VERSION 5.8 ;
BUSBITCHARS "[]" ;
DIVIDERCHAR "/" ;
UNITS
    DATABASE MICRONS 1000 ;
END UNITS

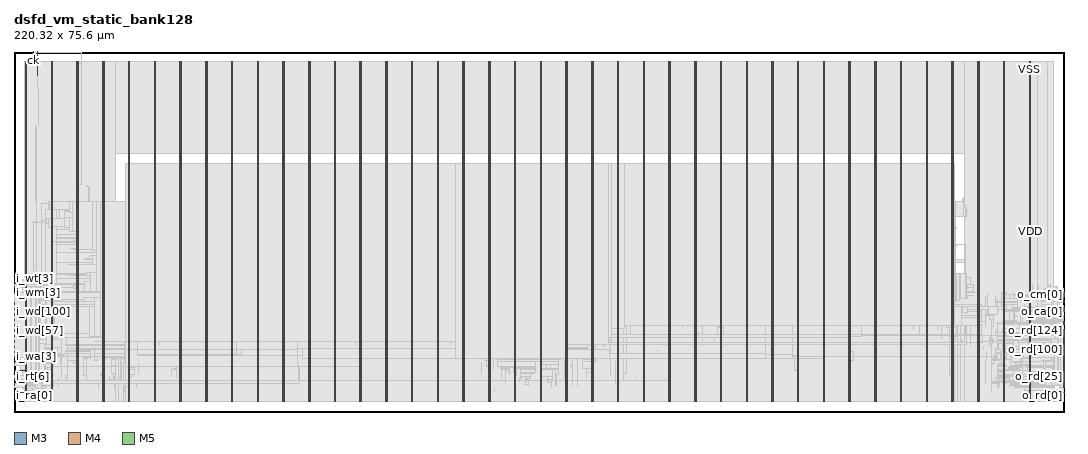
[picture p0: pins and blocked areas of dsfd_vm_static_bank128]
MACRO dsfd_vm_static_bank128
  FOREIGN dsfd_vm_static_bank128 0 0 ;
  CLASS BLOCK ;
  SIZE 220.32 BY 75.6 ;
  PIN ck
    DIRECTION INPUT ;
    USE SIGNAL ;
    PORT
      LAYER M3 ;
        RECT  4.032 75.562 4.05 75.6 ;
    END
    PORT
      LAYER M3 ;
        RECT  4.032 75.451 4.05 75.581 ;
    END
  END ck
  PIN i_ra[0]
    DIRECTION INPUT ;
    USE SIGNAL ;
    PORT
      LAYER M4 ;
        RECT  0 5.088 0.084 5.112 ;
    END
  END i_ra[0]
  PIN i_ra[1]
    DIRECTION INPUT ;
    USE SIGNAL ;
    PORT
      LAYER M4 ;
        RECT  0 5.184 0.084 5.208 ;
    END
  END i_ra[1]
  PIN i_ra[2]
    DIRECTION INPUT ;
    USE SIGNAL ;
    PORT
      LAYER M4 ;
        RECT  0 5.28 0.084 5.304 ;
    END
  END i_ra[2]
  PIN i_ra[3]
    DIRECTION INPUT ;
    USE SIGNAL ;
    PORT
      LAYER M4 ;
        RECT  0 5.376 0.084 5.4 ;
    END
  END i_ra[3]
  PIN i_ra[4]
    DIRECTION INPUT ;
    USE SIGNAL ;
    PORT
      LAYER M4 ;
        RECT  0 5.472 0.084 5.496 ;
    END
  END i_ra[4]
  PIN i_ra[5]
    DIRECTION INPUT ;
    USE SIGNAL ;
    PORT
      LAYER M4 ;
        RECT  0 5.568 0.084 5.592 ;
    END
  END i_ra[5]
  PIN i_ra[6]
    DIRECTION INPUT ;
    USE SIGNAL ;
    PORT
      LAYER M4 ;
        RECT  0 5.664 0.084 5.688 ;
    END
  END i_ra[6]
  PIN i_ra[7]
    DIRECTION INPUT ;
    USE SIGNAL ;
    PORT
      LAYER M4 ;
        RECT  0 5.76 0.084 5.784 ;
    END
  END i_ra[7]
  PIN i_ra[8]
    DIRECTION INPUT ;
    USE SIGNAL ;
    PORT
      LAYER M4 ;
        RECT  0 5.856 0.084 5.88 ;
    END
  END i_ra[8]
  PIN i_rt[0]
    DIRECTION INPUT ;
    USE SIGNAL ;
    PORT
      LAYER M4 ;
        RECT  0 6.912 0.084 6.936 ;
    END
  END i_rt[0]
  PIN i_rt[1]
    DIRECTION INPUT ;
    USE SIGNAL ;
    PORT
      LAYER M4 ;
        RECT  0 7.008 0.084 7.032 ;
    END
  END i_rt[1]
  PIN i_rt[2]
    DIRECTION INPUT ;
    USE SIGNAL ;
    PORT
      LAYER M4 ;
        RECT  0 7.104 0.084 7.128 ;
    END
  END i_rt[2]
  PIN i_rt[3]
    DIRECTION INPUT ;
    USE SIGNAL ;
    PORT
      LAYER M4 ;
        RECT  0 7.2 0.084 7.224 ;
    END
  END i_rt[3]
  PIN i_rt[4]
    DIRECTION INPUT ;
    USE SIGNAL ;
    PORT
      LAYER M4 ;
        RECT  0 7.296 0.084 7.32 ;
    END
  END i_rt[4]
  PIN i_rt[5]
    DIRECTION INPUT ;
    USE SIGNAL ;
    PORT
      LAYER M4 ;
        RECT  0 7.392 0.084 7.416 ;
    END
  END i_rt[5]
  PIN i_rt[6]
    DIRECTION INPUT ;
    USE SIGNAL ;
    PORT
      LAYER M4 ;
        RECT  0 7.488 0.084 7.512 ;
    END
  END i_rt[6]
  PIN i_rt[7]
    DIRECTION INPUT ;
    USE SIGNAL ;
    PORT
      LAYER M4 ;
        RECT  0 7.584 0.084 7.608 ;
    END
  END i_rt[7]
  PIN i_rv
    DIRECTION INPUT ;
    USE SIGNAL ;
    PORT
      LAYER M4 ;
        RECT  0 4.032 0.084 4.056 ;
    END
    PORT
      LAYER M4 ;
        RECT  0.06 4.032 2.408 4.056 ;
    END
  END i_rv
  PIN i_wa[0]
    DIRECTION INPUT ;
    USE SIGNAL ;
    PORT
      LAYER M4 ;
        RECT  0 9.696 0.084 9.72 ;
    END
  END i_wa[0]
  PIN i_wa[1]
    DIRECTION INPUT ;
    USE SIGNAL ;
    PORT
      LAYER M4 ;
        RECT  0 9.792 0.084 9.816 ;
    END
  END i_wa[1]
  PIN i_wa[2]
    DIRECTION INPUT ;
    USE SIGNAL ;
    PORT
      LAYER M4 ;
        RECT  0 9.888 0.084 9.912 ;
    END
  END i_wa[2]
  PIN i_wa[3]
    DIRECTION INPUT ;
    USE SIGNAL ;
    PORT
      LAYER M4 ;
        RECT  0 9.984 0.084 10.008 ;
    END
  END i_wa[3]
  PIN i_wa[4]
    DIRECTION INPUT ;
    USE SIGNAL ;
    PORT
      LAYER M4 ;
        RECT  0 10.08 0.084 10.104 ;
    END
  END i_wa[4]
  PIN i_wa[5]
    DIRECTION INPUT ;
    USE SIGNAL ;
    PORT
      LAYER M4 ;
        RECT  0 10.176 0.084 10.2 ;
    END
  END i_wa[5]
  PIN i_wa[6]
    DIRECTION INPUT ;
    USE SIGNAL ;
    PORT
      LAYER M4 ;
        RECT  0 10.272 0.084 10.296 ;
    END
  END i_wa[6]
  PIN i_wa[7]
    DIRECTION INPUT ;
    USE SIGNAL ;
    PORT
      LAYER M4 ;
        RECT  0 10.368 0.084 10.392 ;
    END
  END i_wa[7]
  PIN i_wa[8]
    DIRECTION INPUT ;
    USE SIGNAL ;
    PORT
      LAYER M4 ;
        RECT  0 10.464 0.084 10.488 ;
    END
  END i_wa[8]
  PIN i_wd[0]
    DIRECTION INPUT ;
    USE SIGNAL ;
    PORT
      LAYER M4 ;
        RECT  0 11.52 0.084 11.544 ;
    END
  END i_wd[0]
  PIN i_wd[100]
    DIRECTION INPUT ;
    USE SIGNAL ;
    PORT
      LAYER M4 ;
        RECT  0 21.12 0.084 21.144 ;
    END
  END i_wd[100]
  PIN i_wd[101]
    DIRECTION INPUT ;
    USE SIGNAL ;
    PORT
      LAYER M4 ;
        RECT  0 21.216 0.084 21.24 ;
    END
  END i_wd[101]
  PIN i_wd[102]
    DIRECTION INPUT ;
    USE SIGNAL ;
    PORT
      LAYER M4 ;
        RECT  0 21.312 0.084 21.336 ;
    END
  END i_wd[102]
  PIN i_wd[103]
    DIRECTION INPUT ;
    USE SIGNAL ;
    PORT
      LAYER M4 ;
        RECT  0 21.408 0.084 21.432 ;
    END
  END i_wd[103]
  PIN i_wd[104]
    DIRECTION INPUT ;
    USE SIGNAL ;
    PORT
      LAYER M4 ;
        RECT  0 21.504 0.084 21.528 ;
    END
  END i_wd[104]
  PIN i_wd[105]
    DIRECTION INPUT ;
    USE SIGNAL ;
    PORT
      LAYER M4 ;
        RECT  0 21.6 0.084 21.624 ;
    END
  END i_wd[105]
  PIN i_wd[106]
    DIRECTION INPUT ;
    USE SIGNAL ;
    PORT
      LAYER M4 ;
        RECT  0 21.696 0.084 21.72 ;
    END
  END i_wd[106]
  PIN i_wd[107]
    DIRECTION INPUT ;
    USE SIGNAL ;
    PORT
      LAYER M4 ;
        RECT  0 21.792 0.084 21.816 ;
    END
  END i_wd[107]
  PIN i_wd[108]
    DIRECTION INPUT ;
    USE SIGNAL ;
    PORT
      LAYER M4 ;
        RECT  0 21.888 0.084 21.912 ;
    END
  END i_wd[108]
  PIN i_wd[109]
    DIRECTION INPUT ;
    USE SIGNAL ;
    PORT
      LAYER M4 ;
        RECT  0 21.984 0.084 22.008 ;
    END
  END i_wd[109]
  PIN i_wd[10]
    DIRECTION INPUT ;
    USE SIGNAL ;
    PORT
      LAYER M4 ;
        RECT  0 12.48 0.084 12.504 ;
    END
  END i_wd[10]
  PIN i_wd[110]
    DIRECTION INPUT ;
    USE SIGNAL ;
    PORT
      LAYER M4 ;
        RECT  0 22.08 0.084 22.104 ;
    END
  END i_wd[110]
  PIN i_wd[111]
    DIRECTION INPUT ;
    USE SIGNAL ;
    PORT
      LAYER M4 ;
        RECT  0 22.176 0.084 22.2 ;
    END
  END i_wd[111]
  PIN i_wd[112]
    DIRECTION INPUT ;
    USE SIGNAL ;
    PORT
      LAYER M4 ;
        RECT  0 22.272 0.084 22.296 ;
    END
  END i_wd[112]
  PIN i_wd[113]
    DIRECTION INPUT ;
    USE SIGNAL ;
    PORT
      LAYER M4 ;
        RECT  0 22.368 0.084 22.392 ;
    END
  END i_wd[113]
  PIN i_wd[114]
    DIRECTION INPUT ;
    USE SIGNAL ;
    PORT
      LAYER M4 ;
        RECT  0 22.464 0.084 22.488 ;
    END
  END i_wd[114]
  PIN i_wd[115]
    DIRECTION INPUT ;
    USE SIGNAL ;
    PORT
      LAYER M4 ;
        RECT  0 22.56 0.084 22.584 ;
    END
  END i_wd[115]
  PIN i_wd[116]
    DIRECTION INPUT ;
    USE SIGNAL ;
    PORT
      LAYER M4 ;
        RECT  0 22.656 0.084 22.68 ;
    END
  END i_wd[116]
  PIN i_wd[117]
    DIRECTION INPUT ;
    USE SIGNAL ;
    PORT
      LAYER M4 ;
        RECT  0 22.752 0.084 22.776 ;
    END
  END i_wd[117]
  PIN i_wd[118]
    DIRECTION INPUT ;
    USE SIGNAL ;
    PORT
      LAYER M4 ;
        RECT  0 22.848 0.084 22.872 ;
    END
  END i_wd[118]
  PIN i_wd[119]
    DIRECTION INPUT ;
    USE SIGNAL ;
    PORT
      LAYER M4 ;
        RECT  0 22.944 0.084 22.968 ;
    END
  END i_wd[119]
  PIN i_wd[11]
    DIRECTION INPUT ;
    USE SIGNAL ;
    PORT
      LAYER M4 ;
        RECT  0 12.576 0.084 12.6 ;
    END
  END i_wd[11]
  PIN i_wd[120]
    DIRECTION INPUT ;
    USE SIGNAL ;
    PORT
      LAYER M4 ;
        RECT  0 23.04 0.084 23.064 ;
    END
  END i_wd[120]
  PIN i_wd[121]
    DIRECTION INPUT ;
    USE SIGNAL ;
    PORT
      LAYER M4 ;
        RECT  0 23.136 0.084 23.16 ;
    END
  END i_wd[121]
  PIN i_wd[122]
    DIRECTION INPUT ;
    USE SIGNAL ;
    PORT
      LAYER M4 ;
        RECT  0 23.232 0.084 23.256 ;
    END
  END i_wd[122]
  PIN i_wd[123]
    DIRECTION INPUT ;
    USE SIGNAL ;
    PORT
      LAYER M4 ;
        RECT  0 23.328 0.084 23.352 ;
    END
  END i_wd[123]
  PIN i_wd[124]
    DIRECTION INPUT ;
    USE SIGNAL ;
    PORT
      LAYER M4 ;
        RECT  0 23.424 0.084 23.448 ;
    END
  END i_wd[124]
  PIN i_wd[125]
    DIRECTION INPUT ;
    USE SIGNAL ;
    PORT
      LAYER M4 ;
        RECT  0 23.52 0.084 23.544 ;
    END
  END i_wd[125]
  PIN i_wd[126]
    DIRECTION INPUT ;
    USE SIGNAL ;
    PORT
      LAYER M4 ;
        RECT  0 23.616 0.084 23.64 ;
    END
  END i_wd[126]
  PIN i_wd[127]
    DIRECTION INPUT ;
    USE SIGNAL ;
    PORT
      LAYER M4 ;
        RECT  0 23.712 0.084 23.736 ;
    END
  END i_wd[127]
  PIN i_wd[12]
    DIRECTION INPUT ;
    USE SIGNAL ;
    PORT
      LAYER M4 ;
        RECT  0 12.672 0.084 12.696 ;
    END
  END i_wd[12]
  PIN i_wd[13]
    DIRECTION INPUT ;
    USE SIGNAL ;
    PORT
      LAYER M4 ;
        RECT  0 12.768 0.084 12.792 ;
    END
  END i_wd[13]
  PIN i_wd[14]
    DIRECTION INPUT ;
    USE SIGNAL ;
    PORT
      LAYER M4 ;
        RECT  0 12.864 0.084 12.888 ;
    END
  END i_wd[14]
  PIN i_wd[15]
    DIRECTION INPUT ;
    USE SIGNAL ;
    PORT
      LAYER M4 ;
        RECT  0 12.96 0.084 12.984 ;
    END
  END i_wd[15]
  PIN i_wd[16]
    DIRECTION INPUT ;
    USE SIGNAL ;
    PORT
      LAYER M4 ;
        RECT  0 13.056 0.084 13.08 ;
    END
  END i_wd[16]
  PIN i_wd[17]
    DIRECTION INPUT ;
    USE SIGNAL ;
    PORT
      LAYER M4 ;
        RECT  0 13.152 0.084 13.176 ;
    END
  END i_wd[17]
  PIN i_wd[18]
    DIRECTION INPUT ;
    USE SIGNAL ;
    PORT
      LAYER M4 ;
        RECT  0 13.248 0.084 13.272 ;
    END
  END i_wd[18]
  PIN i_wd[19]
    DIRECTION INPUT ;
    USE SIGNAL ;
    PORT
      LAYER M4 ;
        RECT  0 13.344 0.084 13.368 ;
    END
  END i_wd[19]
  PIN i_wd[1]
    DIRECTION INPUT ;
    USE SIGNAL ;
    PORT
      LAYER M4 ;
        RECT  0 11.616 0.084 11.64 ;
    END
  END i_wd[1]
  PIN i_wd[20]
    DIRECTION INPUT ;
    USE SIGNAL ;
    PORT
      LAYER M4 ;
        RECT  0 13.44 0.084 13.464 ;
    END
  END i_wd[20]
  PIN i_wd[21]
    DIRECTION INPUT ;
    USE SIGNAL ;
    PORT
      LAYER M4 ;
        RECT  0 13.536 0.084 13.56 ;
    END
  END i_wd[21]
  PIN i_wd[22]
    DIRECTION INPUT ;
    USE SIGNAL ;
    PORT
      LAYER M4 ;
        RECT  0 13.632 0.084 13.656 ;
    END
  END i_wd[22]
  PIN i_wd[23]
    DIRECTION INPUT ;
    USE SIGNAL ;
    PORT
      LAYER M4 ;
        RECT  0 13.728 0.084 13.752 ;
    END
  END i_wd[23]
  PIN i_wd[24]
    DIRECTION INPUT ;
    USE SIGNAL ;
    PORT
      LAYER M4 ;
        RECT  0 13.824 0.084 13.848 ;
    END
  END i_wd[24]
  PIN i_wd[25]
    DIRECTION INPUT ;
    USE SIGNAL ;
    PORT
      LAYER M4 ;
        RECT  0 13.92 0.084 13.944 ;
    END
  END i_wd[25]
  PIN i_wd[26]
    DIRECTION INPUT ;
    USE SIGNAL ;
    PORT
      LAYER M4 ;
        RECT  0 14.016 0.084 14.04 ;
    END
  END i_wd[26]
  PIN i_wd[27]
    DIRECTION INPUT ;
    USE SIGNAL ;
    PORT
      LAYER M4 ;
        RECT  0 14.112 0.084 14.136 ;
    END
  END i_wd[27]
  PIN i_wd[28]
    DIRECTION INPUT ;
    USE SIGNAL ;
    PORT
      LAYER M4 ;
        RECT  0 14.208 0.084 14.232 ;
    END
  END i_wd[28]
  PIN i_wd[29]
    DIRECTION INPUT ;
    USE SIGNAL ;
    PORT
      LAYER M4 ;
        RECT  0 14.304 0.084 14.328 ;
    END
  END i_wd[29]
  PIN i_wd[2]
    DIRECTION INPUT ;
    USE SIGNAL ;
    PORT
      LAYER M4 ;
        RECT  0 11.712 0.084 11.736 ;
    END
  END i_wd[2]
  PIN i_wd[30]
    DIRECTION INPUT ;
    USE SIGNAL ;
    PORT
      LAYER M4 ;
        RECT  0 14.4 0.084 14.424 ;
    END
  END i_wd[30]
  PIN i_wd[31]
    DIRECTION INPUT ;
    USE SIGNAL ;
    PORT
      LAYER M4 ;
        RECT  0 14.496 0.084 14.52 ;
    END
  END i_wd[31]
  PIN i_wd[32]
    DIRECTION INPUT ;
    USE SIGNAL ;
    PORT
      LAYER M4 ;
        RECT  0 14.592 0.084 14.616 ;
    END
  END i_wd[32]
  PIN i_wd[33]
    DIRECTION INPUT ;
    USE SIGNAL ;
    PORT
      LAYER M4 ;
        RECT  0 14.688 0.084 14.712 ;
    END
  END i_wd[33]
  PIN i_wd[34]
    DIRECTION INPUT ;
    USE SIGNAL ;
    PORT
      LAYER M4 ;
        RECT  0 14.784 0.084 14.808 ;
    END
  END i_wd[34]
  PIN i_wd[35]
    DIRECTION INPUT ;
    USE SIGNAL ;
    PORT
      LAYER M4 ;
        RECT  0 14.88 0.084 14.904 ;
    END
  END i_wd[35]
  PIN i_wd[36]
    DIRECTION INPUT ;
    USE SIGNAL ;
    PORT
      LAYER M4 ;
        RECT  0 14.976 0.084 15 ;
    END
  END i_wd[36]
  PIN i_wd[37]
    DIRECTION INPUT ;
    USE SIGNAL ;
    PORT
      LAYER M4 ;
        RECT  0 15.072 0.084 15.096 ;
    END
  END i_wd[37]
  PIN i_wd[38]
    DIRECTION INPUT ;
    USE SIGNAL ;
    PORT
      LAYER M4 ;
        RECT  0 15.168 0.084 15.192 ;
    END
  END i_wd[38]
  PIN i_wd[39]
    DIRECTION INPUT ;
    USE SIGNAL ;
    PORT
      LAYER M4 ;
        RECT  0 15.264 0.084 15.288 ;
    END
  END i_wd[39]
  PIN i_wd[3]
    DIRECTION INPUT ;
    USE SIGNAL ;
    PORT
      LAYER M4 ;
        RECT  0 11.808 0.084 11.832 ;
    END
  END i_wd[3]
  PIN i_wd[40]
    DIRECTION INPUT ;
    USE SIGNAL ;
    PORT
      LAYER M4 ;
        RECT  0 15.36 0.084 15.384 ;
    END
  END i_wd[40]
  PIN i_wd[41]
    DIRECTION INPUT ;
    USE SIGNAL ;
    PORT
      LAYER M4 ;
        RECT  0 15.456 0.084 15.48 ;
    END
  END i_wd[41]
  PIN i_wd[42]
    DIRECTION INPUT ;
    USE SIGNAL ;
    PORT
      LAYER M4 ;
        RECT  0 15.552 0.084 15.576 ;
    END
  END i_wd[42]
  PIN i_wd[43]
    DIRECTION INPUT ;
    USE SIGNAL ;
    PORT
      LAYER M4 ;
        RECT  0 15.648 0.084 15.672 ;
    END
  END i_wd[43]
  PIN i_wd[44]
    DIRECTION INPUT ;
    USE SIGNAL ;
    PORT
      LAYER M4 ;
        RECT  0 15.744 0.084 15.768 ;
    END
  END i_wd[44]
  PIN i_wd[45]
    DIRECTION INPUT ;
    USE SIGNAL ;
    PORT
      LAYER M4 ;
        RECT  0 15.84 0.084 15.864 ;
    END
  END i_wd[45]
  PIN i_wd[46]
    DIRECTION INPUT ;
    USE SIGNAL ;
    PORT
      LAYER M4 ;
        RECT  0 15.936 0.084 15.96 ;
    END
  END i_wd[46]
  PIN i_wd[47]
    DIRECTION INPUT ;
    USE SIGNAL ;
    PORT
      LAYER M4 ;
        RECT  0 16.032 0.084 16.056 ;
    END
  END i_wd[47]
  PIN i_wd[48]
    DIRECTION INPUT ;
    USE SIGNAL ;
    PORT
      LAYER M4 ;
        RECT  0 16.128 0.084 16.152 ;
    END
  END i_wd[48]
  PIN i_wd[49]
    DIRECTION INPUT ;
    USE SIGNAL ;
    PORT
      LAYER M4 ;
        RECT  0 16.224 0.084 16.248 ;
    END
  END i_wd[49]
  PIN i_wd[4]
    DIRECTION INPUT ;
    USE SIGNAL ;
    PORT
      LAYER M4 ;
        RECT  0 11.904 0.084 11.928 ;
    END
  END i_wd[4]
  PIN i_wd[50]
    DIRECTION INPUT ;
    USE SIGNAL ;
    PORT
      LAYER M4 ;
        RECT  0 16.32 0.084 16.344 ;
    END
  END i_wd[50]
  PIN i_wd[51]
    DIRECTION INPUT ;
    USE SIGNAL ;
    PORT
      LAYER M4 ;
        RECT  0 16.416 0.084 16.44 ;
    END
  END i_wd[51]
  PIN i_wd[52]
    DIRECTION INPUT ;
    USE SIGNAL ;
    PORT
      LAYER M4 ;
        RECT  0 16.512 0.084 16.536 ;
    END
  END i_wd[52]
  PIN i_wd[53]
    DIRECTION INPUT ;
    USE SIGNAL ;
    PORT
      LAYER M4 ;
        RECT  0 16.608 0.084 16.632 ;
    END
  END i_wd[53]
  PIN i_wd[54]
    DIRECTION INPUT ;
    USE SIGNAL ;
    PORT
      LAYER M4 ;
        RECT  0 16.704 0.084 16.728 ;
    END
  END i_wd[54]
  PIN i_wd[55]
    DIRECTION INPUT ;
    USE SIGNAL ;
    PORT
      LAYER M4 ;
        RECT  0 16.8 0.084 16.824 ;
    END
  END i_wd[55]
  PIN i_wd[56]
    DIRECTION INPUT ;
    USE SIGNAL ;
    PORT
      LAYER M4 ;
        RECT  0 16.896 0.084 16.92 ;
    END
  END i_wd[56]
  PIN i_wd[57]
    DIRECTION INPUT ;
    USE SIGNAL ;
    PORT
      LAYER M4 ;
        RECT  0 16.992 0.084 17.016 ;
    END
  END i_wd[57]
  PIN i_wd[58]
    DIRECTION INPUT ;
    USE SIGNAL ;
    PORT
      LAYER M4 ;
        RECT  0 17.088 0.084 17.112 ;
    END
  END i_wd[58]
  PIN i_wd[59]
    DIRECTION INPUT ;
    USE SIGNAL ;
    PORT
      LAYER M4 ;
        RECT  0 17.184 0.084 17.208 ;
    END
  END i_wd[59]
  PIN i_wd[5]
    DIRECTION INPUT ;
    USE SIGNAL ;
    PORT
      LAYER M4 ;
        RECT  0 12 0.084 12.024 ;
    END
  END i_wd[5]
  PIN i_wd[60]
    DIRECTION INPUT ;
    USE SIGNAL ;
    PORT
      LAYER M4 ;
        RECT  0 17.28 0.084 17.304 ;
    END
  END i_wd[60]
  PIN i_wd[61]
    DIRECTION INPUT ;
    USE SIGNAL ;
    PORT
      LAYER M4 ;
        RECT  0 17.376 0.084 17.4 ;
    END
  END i_wd[61]
  PIN i_wd[62]
    DIRECTION INPUT ;
    USE SIGNAL ;
    PORT
      LAYER M4 ;
        RECT  0 17.472 0.084 17.496 ;
    END
  END i_wd[62]
  PIN i_wd[63]
    DIRECTION INPUT ;
    USE SIGNAL ;
    PORT
      LAYER M4 ;
        RECT  0 17.568 0.084 17.592 ;
    END
  END i_wd[63]
  PIN i_wd[64]
    DIRECTION INPUT ;
    USE SIGNAL ;
    PORT
      LAYER M4 ;
        RECT  0 17.664 0.084 17.688 ;
    END
  END i_wd[64]
  PIN i_wd[65]
    DIRECTION INPUT ;
    USE SIGNAL ;
    PORT
      LAYER M4 ;
        RECT  0 17.76 0.084 17.784 ;
    END
  END i_wd[65]
  PIN i_wd[66]
    DIRECTION INPUT ;
    USE SIGNAL ;
    PORT
      LAYER M4 ;
        RECT  0 17.856 0.084 17.88 ;
    END
  END i_wd[66]
  PIN i_wd[67]
    DIRECTION INPUT ;
    USE SIGNAL ;
    PORT
      LAYER M4 ;
        RECT  0 17.952 0.084 17.976 ;
    END
  END i_wd[67]
  PIN i_wd[68]
    DIRECTION INPUT ;
    USE SIGNAL ;
    PORT
      LAYER M4 ;
        RECT  0 18.048 0.084 18.072 ;
    END
  END i_wd[68]
  PIN i_wd[69]
    DIRECTION INPUT ;
    USE SIGNAL ;
    PORT
      LAYER M4 ;
        RECT  0 18.144 0.084 18.168 ;
    END
  END i_wd[69]
  PIN i_wd[6]
    DIRECTION INPUT ;
    USE SIGNAL ;
    PORT
      LAYER M4 ;
        RECT  0 12.096 0.084 12.12 ;
    END
  END i_wd[6]
  PIN i_wd[70]
    DIRECTION INPUT ;
    USE SIGNAL ;
    PORT
      LAYER M4 ;
        RECT  0 18.24 0.084 18.264 ;
    END
  END i_wd[70]
  PIN i_wd[71]
    DIRECTION INPUT ;
    USE SIGNAL ;
    PORT
      LAYER M4 ;
        RECT  0 18.336 0.084 18.36 ;
    END
  END i_wd[71]
  PIN i_wd[72]
    DIRECTION INPUT ;
    USE SIGNAL ;
    PORT
      LAYER M4 ;
        RECT  0 18.432 0.084 18.456 ;
    END
  END i_wd[72]
  PIN i_wd[73]
    DIRECTION INPUT ;
    USE SIGNAL ;
    PORT
      LAYER M4 ;
        RECT  0 18.528 0.084 18.552 ;
    END
  END i_wd[73]
  PIN i_wd[74]
    DIRECTION INPUT ;
    USE SIGNAL ;
    PORT
      LAYER M4 ;
        RECT  0 18.624 0.084 18.648 ;
    END
  END i_wd[74]
  PIN i_wd[75]
    DIRECTION INPUT ;
    USE SIGNAL ;
    PORT
      LAYER M4 ;
        RECT  0 18.72 0.084 18.744 ;
    END
  END i_wd[75]
  PIN i_wd[76]
    DIRECTION INPUT ;
    USE SIGNAL ;
    PORT
      LAYER M4 ;
        RECT  0 18.816 0.084 18.84 ;
    END
  END i_wd[76]
  PIN i_wd[77]
    DIRECTION INPUT ;
    USE SIGNAL ;
    PORT
      LAYER M4 ;
        RECT  0 18.912 0.084 18.936 ;
    END
  END i_wd[77]
  PIN i_wd[78]
    DIRECTION INPUT ;
    USE SIGNAL ;
    PORT
      LAYER M4 ;
        RECT  0 19.008 0.084 19.032 ;
    END
  END i_wd[78]
  PIN i_wd[79]
    DIRECTION INPUT ;
    USE SIGNAL ;
    PORT
      LAYER M4 ;
        RECT  0 19.104 0.084 19.128 ;
    END
  END i_wd[79]
  PIN i_wd[7]
    DIRECTION INPUT ;
    USE SIGNAL ;
    PORT
      LAYER M4 ;
        RECT  0 12.192 0.084 12.216 ;
    END
  END i_wd[7]
  PIN i_wd[80]
    DIRECTION INPUT ;
    USE SIGNAL ;
    PORT
      LAYER M4 ;
        RECT  0 19.2 0.084 19.224 ;
    END
  END i_wd[80]
  PIN i_wd[81]
    DIRECTION INPUT ;
    USE SIGNAL ;
    PORT
      LAYER M4 ;
        RECT  0 19.296 0.084 19.32 ;
    END
  END i_wd[81]
  PIN i_wd[82]
    DIRECTION INPUT ;
    USE SIGNAL ;
    PORT
      LAYER M4 ;
        RECT  0 19.392 0.084 19.416 ;
    END
  END i_wd[82]
  PIN i_wd[83]
    DIRECTION INPUT ;
    USE SIGNAL ;
    PORT
      LAYER M4 ;
        RECT  0 19.488 0.084 19.512 ;
    END
  END i_wd[83]
  PIN i_wd[84]
    DIRECTION INPUT ;
    USE SIGNAL ;
    PORT
      LAYER M4 ;
        RECT  0 19.584 0.084 19.608 ;
    END
  END i_wd[84]
  PIN i_wd[85]
    DIRECTION INPUT ;
    USE SIGNAL ;
    PORT
      LAYER M4 ;
        RECT  0 19.68 0.084 19.704 ;
    END
  END i_wd[85]
  PIN i_wd[86]
    DIRECTION INPUT ;
    USE SIGNAL ;
    PORT
      LAYER M4 ;
        RECT  0 19.776 0.084 19.8 ;
    END
  END i_wd[86]
  PIN i_wd[87]
    DIRECTION INPUT ;
    USE SIGNAL ;
    PORT
      LAYER M4 ;
        RECT  0 19.872 0.084 19.896 ;
    END
  END i_wd[87]
  PIN i_wd[88]
    DIRECTION INPUT ;
    USE SIGNAL ;
    PORT
      LAYER M4 ;
        RECT  0 19.968 0.084 19.992 ;
    END
  END i_wd[88]
  PIN i_wd[89]
    DIRECTION INPUT ;
    USE SIGNAL ;
    PORT
      LAYER M4 ;
        RECT  0 20.064 0.084 20.088 ;
    END
  END i_wd[89]
  PIN i_wd[8]
    DIRECTION INPUT ;
    USE SIGNAL ;
    PORT
      LAYER M4 ;
        RECT  0 12.288 0.084 12.312 ;
    END
  END i_wd[8]
  PIN i_wd[90]
    DIRECTION INPUT ;
    USE SIGNAL ;
    PORT
      LAYER M4 ;
        RECT  0 20.16 0.084 20.184 ;
    END
  END i_wd[90]
  PIN i_wd[91]
    DIRECTION INPUT ;
    USE SIGNAL ;
    PORT
      LAYER M4 ;
        RECT  0 20.256 0.084 20.28 ;
    END
  END i_wd[91]
  PIN i_wd[92]
    DIRECTION INPUT ;
    USE SIGNAL ;
    PORT
      LAYER M4 ;
        RECT  0 20.352 0.084 20.376 ;
    END
  END i_wd[92]
  PIN i_wd[93]
    DIRECTION INPUT ;
    USE SIGNAL ;
    PORT
      LAYER M4 ;
        RECT  0 20.448 0.084 20.472 ;
    END
  END i_wd[93]
  PIN i_wd[94]
    DIRECTION INPUT ;
    USE SIGNAL ;
    PORT
      LAYER M4 ;
        RECT  0 20.544 0.084 20.568 ;
    END
  END i_wd[94]
  PIN i_wd[95]
    DIRECTION INPUT ;
    USE SIGNAL ;
    PORT
      LAYER M4 ;
        RECT  0 20.64 0.084 20.664 ;
    END
  END i_wd[95]
  PIN i_wd[96]
    DIRECTION INPUT ;
    USE SIGNAL ;
    PORT
      LAYER M4 ;
        RECT  0 20.736 0.084 20.76 ;
    END
  END i_wd[96]
  PIN i_wd[97]
    DIRECTION INPUT ;
    USE SIGNAL ;
    PORT
      LAYER M4 ;
        RECT  0 20.832 0.084 20.856 ;
    END
  END i_wd[97]
  PIN i_wd[98]
    DIRECTION INPUT ;
    USE SIGNAL ;
    PORT
      LAYER M4 ;
        RECT  0 20.928 0.084 20.952 ;
    END
  END i_wd[98]
  PIN i_wd[99]
    DIRECTION INPUT ;
    USE SIGNAL ;
    PORT
      LAYER M4 ;
        RECT  0 21.024 0.084 21.048 ;
    END
  END i_wd[99]
  PIN i_wd[9]
    DIRECTION INPUT ;
    USE SIGNAL ;
    PORT
      LAYER M4 ;
        RECT  0 12.384 0.084 12.408 ;
    END
  END i_wd[9]
  PIN i_wm[0]
    DIRECTION INPUT ;
    USE SIGNAL ;
    PORT
      LAYER M4 ;
        RECT  0 24.768 0.084 24.792 ;
    END
  END i_wm[0]
  PIN i_wm[1]
    DIRECTION INPUT ;
    USE SIGNAL ;
    PORT
      LAYER M4 ;
        RECT  0 24.864 0.084 24.888 ;
    END
  END i_wm[1]
  PIN i_wm[2]
    DIRECTION INPUT ;
    USE SIGNAL ;
    PORT
      LAYER M4 ;
        RECT  0 24.96 0.084 24.984 ;
    END
  END i_wm[2]
  PIN i_wm[3]
    DIRECTION INPUT ;
    USE SIGNAL ;
    PORT
      LAYER M4 ;
        RECT  0 25.056 0.084 25.08 ;
    END
  END i_wm[3]
  PIN i_wt[0]
    DIRECTION INPUT ;
    USE SIGNAL ;
    PORT
      LAYER M4 ;
        RECT  0 26.112 0.084 26.136 ;
    END
  END i_wt[0]
  PIN i_wt[1]
    DIRECTION INPUT ;
    USE SIGNAL ;
    PORT
      LAYER M4 ;
        RECT  0 26.208 0.084 26.232 ;
    END
  END i_wt[1]
  PIN i_wt[2]
    DIRECTION INPUT ;
    USE SIGNAL ;
    PORT
      LAYER M4 ;
        RECT  0 26.304 0.084 26.328 ;
    END
  END i_wt[2]
  PIN i_wt[3]
    DIRECTION INPUT ;
    USE SIGNAL ;
    PORT
      LAYER M4 ;
        RECT  0 26.4 0.084 26.424 ;
    END
  END i_wt[3]
  PIN i_wt[4]
    DIRECTION INPUT ;
    USE SIGNAL ;
    PORT
      LAYER M4 ;
        RECT  0 26.496 0.084 26.52 ;
    END
  END i_wt[4]
  PIN i_wt[5]
    DIRECTION INPUT ;
    USE SIGNAL ;
    PORT
      LAYER M4 ;
        RECT  0 26.592 0.084 26.616 ;
    END
  END i_wt[5]
  PIN i_wt[6]
    DIRECTION INPUT ;
    USE SIGNAL ;
    PORT
      LAYER M4 ;
        RECT  0 26.688 0.084 26.712 ;
    END
  END i_wt[6]
  PIN i_wt[7]
    DIRECTION INPUT ;
    USE SIGNAL ;
    PORT
      LAYER M4 ;
        RECT  0 26.784 0.084 26.808 ;
    END
  END i_wt[7]
  PIN i_wv
    DIRECTION INPUT ;
    USE SIGNAL ;
    PORT
      LAYER M4 ;
        RECT  0 8.64 0.084 8.664 ;
    END
    PORT
      LAYER M4 ;
        RECT  0.06 8.64 2.408 8.664 ;
    END
  END i_wv
  PIN o_ca[0]
    DIRECTION OUTPUT ;
    USE SIGNAL ;
    PORT
      LAYER M4 ;
        RECT  220.236 21.12 220.32 21.144 ;
    END
  END o_ca[0]
  PIN o_ca[1]
    DIRECTION OUTPUT ;
    USE SIGNAL ;
    PORT
      LAYER M4 ;
        RECT  220.236 21.216 220.32 21.24 ;
    END
  END o_ca[1]
  PIN o_ca[2]
    DIRECTION OUTPUT ;
    USE SIGNAL ;
    PORT
      LAYER M4 ;
        RECT  220.236 21.312 220.32 21.336 ;
    END
  END o_ca[2]
  PIN o_ca[3]
    DIRECTION OUTPUT ;
    USE SIGNAL ;
    PORT
      LAYER M4 ;
        RECT  220.236 21.408 220.32 21.432 ;
    END
  END o_ca[3]
  PIN o_ca[4]
    DIRECTION OUTPUT ;
    USE SIGNAL ;
    PORT
      LAYER M4 ;
        RECT  220.236 21.504 220.32 21.528 ;
    END
  END o_ca[4]
  PIN o_ca[5]
    DIRECTION OUTPUT ;
    USE SIGNAL ;
    PORT
      LAYER M4 ;
        RECT  220.236 21.6 220.32 21.624 ;
    END
  END o_ca[5]
  PIN o_ca[6]
    DIRECTION OUTPUT ;
    USE SIGNAL ;
    PORT
      LAYER M4 ;
        RECT  220.236 21.696 220.32 21.72 ;
    END
  END o_ca[6]
  PIN o_ca[7]
    DIRECTION OUTPUT ;
    USE SIGNAL ;
    PORT
      LAYER M4 ;
        RECT  220.236 21.792 220.32 21.816 ;
    END
  END o_ca[7]
  PIN o_ca[8]
    DIRECTION OUTPUT ;
    USE SIGNAL ;
    PORT
      LAYER M4 ;
        RECT  220.236 21.888 220.32 21.912 ;
    END
  END o_ca[8]
  PIN o_cm[0]
    DIRECTION OUTPUT ;
    USE SIGNAL ;
    PORT
      LAYER M4 ;
        RECT  220.236 22.944 220.32 22.968 ;
    END
  END o_cm[0]
  PIN o_cm[1]
    DIRECTION OUTPUT ;
    USE SIGNAL ;
    PORT
      LAYER M4 ;
        RECT  220.236 23.04 220.32 23.064 ;
    END
  END o_cm[1]
  PIN o_cm[2]
    DIRECTION OUTPUT ;
    USE SIGNAL ;
    PORT
      LAYER M4 ;
        RECT  220.236 23.136 220.32 23.16 ;
    END
  END o_cm[2]
  PIN o_cm[3]
    DIRECTION OUTPUT ;
    USE SIGNAL ;
    PORT
      LAYER M4 ;
        RECT  220.236 23.232 220.32 23.256 ;
    END
  END o_cm[3]
  PIN o_commit
    DIRECTION OUTPUT ;
    USE SIGNAL ;
    PORT
      LAYER M4 ;
        RECT  220.236 20.064 220.32 20.088 ;
    END
    PORT
      LAYER M4 ;
        RECT  219.409 20.064 220.284 20.088 ;
    END
  END o_commit
  PIN o_ct[0]
    DIRECTION OUTPUT ;
    USE SIGNAL ;
    PORT
      LAYER M4 ;
        RECT  220.236 24.288 220.32 24.312 ;
    END
  END o_ct[0]
  PIN o_ct[1]
    DIRECTION OUTPUT ;
    USE SIGNAL ;
    PORT
      LAYER M4 ;
        RECT  220.236 24.384 220.32 24.408 ;
    END
  END o_ct[1]
  PIN o_ct[2]
    DIRECTION OUTPUT ;
    USE SIGNAL ;
    PORT
      LAYER M4 ;
        RECT  220.236 24.48 220.32 24.504 ;
    END
  END o_ct[2]
  PIN o_ct[3]
    DIRECTION OUTPUT ;
    USE SIGNAL ;
    PORT
      LAYER M4 ;
        RECT  220.236 24.576 220.32 24.6 ;
    END
  END o_ct[3]
  PIN o_ct[4]
    DIRECTION OUTPUT ;
    USE SIGNAL ;
    PORT
      LAYER M4 ;
        RECT  220.236 24.672 220.32 24.696 ;
    END
  END o_ct[4]
  PIN o_ct[5]
    DIRECTION OUTPUT ;
    USE SIGNAL ;
    PORT
      LAYER M4 ;
        RECT  220.236 24.768 220.32 24.792 ;
    END
  END o_ct[5]
  PIN o_ct[6]
    DIRECTION OUTPUT ;
    USE SIGNAL ;
    PORT
      LAYER M4 ;
        RECT  220.236 24.864 220.32 24.888 ;
    END
  END o_ct[6]
  PIN o_ct[7]
    DIRECTION OUTPUT ;
    USE SIGNAL ;
    PORT
      LAYER M4 ;
        RECT  220.236 24.96 220.32 24.984 ;
    END
  END o_ct[7]
  PIN o_rd[0]
    DIRECTION OUTPUT ;
    USE SIGNAL ;
    PORT
      LAYER M4 ;
        RECT  220.236 5.088 220.32 5.112 ;
    END
  END o_rd[0]
  PIN o_rd[100]
    DIRECTION OUTPUT ;
    USE SIGNAL ;
    PORT
      LAYER M4 ;
        RECT  220.236 14.688 220.32 14.712 ;
    END
  END o_rd[100]
  PIN o_rd[101]
    DIRECTION OUTPUT ;
    USE SIGNAL ;
    PORT
      LAYER M4 ;
        RECT  220.236 14.784 220.32 14.808 ;
    END
  END o_rd[101]
  PIN o_rd[102]
    DIRECTION OUTPUT ;
    USE SIGNAL ;
    PORT
      LAYER M4 ;
        RECT  220.236 14.88 220.32 14.904 ;
    END
  END o_rd[102]
  PIN o_rd[103]
    DIRECTION OUTPUT ;
    USE SIGNAL ;
    PORT
      LAYER M4 ;
        RECT  220.236 14.976 220.32 15 ;
    END
  END o_rd[103]
  PIN o_rd[104]
    DIRECTION OUTPUT ;
    USE SIGNAL ;
    PORT
      LAYER M4 ;
        RECT  220.236 15.072 220.32 15.096 ;
    END
  END o_rd[104]
  PIN o_rd[105]
    DIRECTION OUTPUT ;
    USE SIGNAL ;
    PORT
      LAYER M4 ;
        RECT  220.236 15.168 220.32 15.192 ;
    END
  END o_rd[105]
  PIN o_rd[106]
    DIRECTION OUTPUT ;
    USE SIGNAL ;
    PORT
      LAYER M4 ;
        RECT  220.236 15.264 220.32 15.288 ;
    END
  END o_rd[106]
  PIN o_rd[107]
    DIRECTION OUTPUT ;
    USE SIGNAL ;
    PORT
      LAYER M4 ;
        RECT  220.236 15.36 220.32 15.384 ;
    END
  END o_rd[107]
  PIN o_rd[108]
    DIRECTION OUTPUT ;
    USE SIGNAL ;
    PORT
      LAYER M4 ;
        RECT  220.236 15.456 220.32 15.48 ;
    END
  END o_rd[108]
  PIN o_rd[109]
    DIRECTION OUTPUT ;
    USE SIGNAL ;
    PORT
      LAYER M4 ;
        RECT  220.236 15.552 220.32 15.576 ;
    END
  END o_rd[109]
  PIN o_rd[10]
    DIRECTION OUTPUT ;
    USE SIGNAL ;
    PORT
      LAYER M4 ;
        RECT  220.236 6.048 220.32 6.072 ;
    END
  END o_rd[10]
  PIN o_rd[110]
    DIRECTION OUTPUT ;
    USE SIGNAL ;
    PORT
      LAYER M4 ;
        RECT  220.236 15.648 220.32 15.672 ;
    END
  END o_rd[110]
  PIN o_rd[111]
    DIRECTION OUTPUT ;
    USE SIGNAL ;
    PORT
      LAYER M4 ;
        RECT  220.236 15.744 220.32 15.768 ;
    END
  END o_rd[111]
  PIN o_rd[112]
    DIRECTION OUTPUT ;
    USE SIGNAL ;
    PORT
      LAYER M4 ;
        RECT  220.236 15.84 220.32 15.864 ;
    END
  END o_rd[112]
  PIN o_rd[113]
    DIRECTION OUTPUT ;
    USE SIGNAL ;
    PORT
      LAYER M4 ;
        RECT  220.236 15.936 220.32 15.96 ;
    END
  END o_rd[113]
  PIN o_rd[114]
    DIRECTION OUTPUT ;
    USE SIGNAL ;
    PORT
      LAYER M4 ;
        RECT  220.236 16.032 220.32 16.056 ;
    END
  END o_rd[114]
  PIN o_rd[115]
    DIRECTION OUTPUT ;
    USE SIGNAL ;
    PORT
      LAYER M4 ;
        RECT  220.236 16.128 220.32 16.152 ;
    END
  END o_rd[115]
  PIN o_rd[116]
    DIRECTION OUTPUT ;
    USE SIGNAL ;
    PORT
      LAYER M4 ;
        RECT  220.236 16.224 220.32 16.248 ;
    END
  END o_rd[116]
  PIN o_rd[117]
    DIRECTION OUTPUT ;
    USE SIGNAL ;
    PORT
      LAYER M4 ;
        RECT  220.236 16.32 220.32 16.344 ;
    END
  END o_rd[117]
  PIN o_rd[118]
    DIRECTION OUTPUT ;
    USE SIGNAL ;
    PORT
      LAYER M4 ;
        RECT  220.236 16.416 220.32 16.44 ;
    END
  END o_rd[118]
  PIN o_rd[119]
    DIRECTION OUTPUT ;
    USE SIGNAL ;
    PORT
      LAYER M4 ;
        RECT  220.236 16.512 220.32 16.536 ;
    END
  END o_rd[119]
  PIN o_rd[11]
    DIRECTION OUTPUT ;
    USE SIGNAL ;
    PORT
      LAYER M4 ;
        RECT  220.236 6.144 220.32 6.168 ;
    END
  END o_rd[11]
  PIN o_rd[120]
    DIRECTION OUTPUT ;
    USE SIGNAL ;
    PORT
      LAYER M4 ;
        RECT  220.236 16.608 220.32 16.632 ;
    END
  END o_rd[120]
  PIN o_rd[121]
    DIRECTION OUTPUT ;
    USE SIGNAL ;
    PORT
      LAYER M4 ;
        RECT  220.236 16.704 220.32 16.728 ;
    END
  END o_rd[121]
  PIN o_rd[122]
    DIRECTION OUTPUT ;
    USE SIGNAL ;
    PORT
      LAYER M4 ;
        RECT  220.236 16.8 220.32 16.824 ;
    END
  END o_rd[122]
  PIN o_rd[123]
    DIRECTION OUTPUT ;
    USE SIGNAL ;
    PORT
      LAYER M4 ;
        RECT  220.236 16.896 220.32 16.92 ;
    END
  END o_rd[123]
  PIN o_rd[124]
    DIRECTION OUTPUT ;
    USE SIGNAL ;
    PORT
      LAYER M4 ;
        RECT  220.236 16.992 220.32 17.016 ;
    END
  END o_rd[124]
  PIN o_rd[125]
    DIRECTION OUTPUT ;
    USE SIGNAL ;
    PORT
      LAYER M4 ;
        RECT  220.236 17.088 220.32 17.112 ;
    END
  END o_rd[125]
  PIN o_rd[126]
    DIRECTION OUTPUT ;
    USE SIGNAL ;
    PORT
      LAYER M4 ;
        RECT  220.236 17.184 220.32 17.208 ;
    END
  END o_rd[126]
  PIN o_rd[127]
    DIRECTION OUTPUT ;
    USE SIGNAL ;
    PORT
      LAYER M4 ;
        RECT  220.236 17.28 220.32 17.304 ;
    END
  END o_rd[127]
  PIN o_rd[12]
    DIRECTION OUTPUT ;
    USE SIGNAL ;
    PORT
      LAYER M4 ;
        RECT  220.236 6.24 220.32 6.264 ;
    END
  END o_rd[12]
  PIN o_rd[13]
    DIRECTION OUTPUT ;
    USE SIGNAL ;
    PORT
      LAYER M4 ;
        RECT  220.236 6.336 220.32 6.36 ;
    END
  END o_rd[13]
  PIN o_rd[14]
    DIRECTION OUTPUT ;
    USE SIGNAL ;
    PORT
      LAYER M4 ;
        RECT  220.236 6.432 220.32 6.456 ;
    END
  END o_rd[14]
  PIN o_rd[15]
    DIRECTION OUTPUT ;
    USE SIGNAL ;
    PORT
      LAYER M4 ;
        RECT  220.236 6.528 220.32 6.552 ;
    END
  END o_rd[15]
  PIN o_rd[16]
    DIRECTION OUTPUT ;
    USE SIGNAL ;
    PORT
      LAYER M4 ;
        RECT  220.236 6.624 220.32 6.648 ;
    END
  END o_rd[16]
  PIN o_rd[17]
    DIRECTION OUTPUT ;
    USE SIGNAL ;
    PORT
      LAYER M4 ;
        RECT  220.236 6.72 220.32 6.744 ;
    END
  END o_rd[17]
  PIN o_rd[18]
    DIRECTION OUTPUT ;
    USE SIGNAL ;
    PORT
      LAYER M4 ;
        RECT  220.236 6.816 220.32 6.84 ;
    END
  END o_rd[18]
  PIN o_rd[19]
    DIRECTION OUTPUT ;
    USE SIGNAL ;
    PORT
      LAYER M4 ;
        RECT  220.236 6.912 220.32 6.936 ;
    END
  END o_rd[19]
  PIN o_rd[1]
    DIRECTION OUTPUT ;
    USE SIGNAL ;
    PORT
      LAYER M4 ;
        RECT  220.236 5.184 220.32 5.208 ;
    END
  END o_rd[1]
  PIN o_rd[20]
    DIRECTION OUTPUT ;
    USE SIGNAL ;
    PORT
      LAYER M4 ;
        RECT  220.236 7.008 220.32 7.032 ;
    END
  END o_rd[20]
  PIN o_rd[21]
    DIRECTION OUTPUT ;
    USE SIGNAL ;
    PORT
      LAYER M4 ;
        RECT  220.236 7.104 220.32 7.128 ;
    END
  END o_rd[21]
  PIN o_rd[22]
    DIRECTION OUTPUT ;
    USE SIGNAL ;
    PORT
      LAYER M4 ;
        RECT  220.236 7.2 220.32 7.224 ;
    END
  END o_rd[22]
  PIN o_rd[23]
    DIRECTION OUTPUT ;
    USE SIGNAL ;
    PORT
      LAYER M4 ;
        RECT  220.236 7.296 220.32 7.32 ;
    END
  END o_rd[23]
  PIN o_rd[24]
    DIRECTION OUTPUT ;
    USE SIGNAL ;
    PORT
      LAYER M4 ;
        RECT  220.236 7.392 220.32 7.416 ;
    END
  END o_rd[24]
  PIN o_rd[25]
    DIRECTION OUTPUT ;
    USE SIGNAL ;
    PORT
      LAYER M4 ;
        RECT  220.236 7.488 220.32 7.512 ;
    END
  END o_rd[25]
  PIN o_rd[26]
    DIRECTION OUTPUT ;
    USE SIGNAL ;
    PORT
      LAYER M4 ;
        RECT  220.236 7.584 220.32 7.608 ;
    END
  END o_rd[26]
  PIN o_rd[27]
    DIRECTION OUTPUT ;
    USE SIGNAL ;
    PORT
      LAYER M4 ;
        RECT  220.236 7.68 220.32 7.704 ;
    END
  END o_rd[27]
  PIN o_rd[28]
    DIRECTION OUTPUT ;
    USE SIGNAL ;
    PORT
      LAYER M4 ;
        RECT  220.236 7.776 220.32 7.8 ;
    END
  END o_rd[28]
  PIN o_rd[29]
    DIRECTION OUTPUT ;
    USE SIGNAL ;
    PORT
      LAYER M4 ;
        RECT  220.236 7.872 220.32 7.896 ;
    END
  END o_rd[29]
  PIN o_rd[2]
    DIRECTION OUTPUT ;
    USE SIGNAL ;
    PORT
      LAYER M4 ;
        RECT  220.236 5.28 220.32 5.304 ;
    END
  END o_rd[2]
  PIN o_rd[30]
    DIRECTION OUTPUT ;
    USE SIGNAL ;
    PORT
      LAYER M4 ;
        RECT  220.236 7.968 220.32 7.992 ;
    END
  END o_rd[30]
  PIN o_rd[31]
    DIRECTION OUTPUT ;
    USE SIGNAL ;
    PORT
      LAYER M4 ;
        RECT  220.236 8.064 220.32 8.088 ;
    END
  END o_rd[31]
  PIN o_rd[32]
    DIRECTION OUTPUT ;
    USE SIGNAL ;
    PORT
      LAYER M4 ;
        RECT  220.236 8.16 220.32 8.184 ;
    END
  END o_rd[32]
  PIN o_rd[33]
    DIRECTION OUTPUT ;
    USE SIGNAL ;
    PORT
      LAYER M4 ;
        RECT  220.236 8.256 220.32 8.28 ;
    END
  END o_rd[33]
  PIN o_rd[34]
    DIRECTION OUTPUT ;
    USE SIGNAL ;
    PORT
      LAYER M4 ;
        RECT  220.236 8.352 220.32 8.376 ;
    END
  END o_rd[34]
  PIN o_rd[35]
    DIRECTION OUTPUT ;
    USE SIGNAL ;
    PORT
      LAYER M4 ;
        RECT  220.236 8.448 220.32 8.472 ;
    END
  END o_rd[35]
  PIN o_rd[36]
    DIRECTION OUTPUT ;
    USE SIGNAL ;
    PORT
      LAYER M4 ;
        RECT  220.236 8.544 220.32 8.568 ;
    END
  END o_rd[36]
  PIN o_rd[37]
    DIRECTION OUTPUT ;
    USE SIGNAL ;
    PORT
      LAYER M4 ;
        RECT  220.236 8.64 220.32 8.664 ;
    END
  END o_rd[37]
  PIN o_rd[38]
    DIRECTION OUTPUT ;
    USE SIGNAL ;
    PORT
      LAYER M4 ;
        RECT  220.236 8.736 220.32 8.76 ;
    END
  END o_rd[38]
  PIN o_rd[39]
    DIRECTION OUTPUT ;
    USE SIGNAL ;
    PORT
      LAYER M4 ;
        RECT  220.236 8.832 220.32 8.856 ;
    END
  END o_rd[39]
  PIN o_rd[3]
    DIRECTION OUTPUT ;
    USE SIGNAL ;
    PORT
      LAYER M4 ;
        RECT  220.236 5.376 220.32 5.4 ;
    END
  END o_rd[3]
  PIN o_rd[40]
    DIRECTION OUTPUT ;
    USE SIGNAL ;
    PORT
      LAYER M4 ;
        RECT  220.236 8.928 220.32 8.952 ;
    END
  END o_rd[40]
  PIN o_rd[41]
    DIRECTION OUTPUT ;
    USE SIGNAL ;
    PORT
      LAYER M4 ;
        RECT  220.236 9.024 220.32 9.048 ;
    END
  END o_rd[41]
  PIN o_rd[42]
    DIRECTION OUTPUT ;
    USE SIGNAL ;
    PORT
      LAYER M4 ;
        RECT  220.236 9.12 220.32 9.144 ;
    END
  END o_rd[42]
  PIN o_rd[43]
    DIRECTION OUTPUT ;
    USE SIGNAL ;
    PORT
      LAYER M4 ;
        RECT  220.236 9.216 220.32 9.24 ;
    END
  END o_rd[43]
  PIN o_rd[44]
    DIRECTION OUTPUT ;
    USE SIGNAL ;
    PORT
      LAYER M4 ;
        RECT  220.236 9.312 220.32 9.336 ;
    END
  END o_rd[44]
  PIN o_rd[45]
    DIRECTION OUTPUT ;
    USE SIGNAL ;
    PORT
      LAYER M4 ;
        RECT  220.236 9.408 220.32 9.432 ;
    END
  END o_rd[45]
  PIN o_rd[46]
    DIRECTION OUTPUT ;
    USE SIGNAL ;
    PORT
      LAYER M4 ;
        RECT  220.236 9.504 220.32 9.528 ;
    END
  END o_rd[46]
  PIN o_rd[47]
    DIRECTION OUTPUT ;
    USE SIGNAL ;
    PORT
      LAYER M4 ;
        RECT  220.236 9.6 220.32 9.624 ;
    END
  END o_rd[47]
  PIN o_rd[48]
    DIRECTION OUTPUT ;
    USE SIGNAL ;
    PORT
      LAYER M4 ;
        RECT  220.236 9.696 220.32 9.72 ;
    END
  END o_rd[48]
  PIN o_rd[49]
    DIRECTION OUTPUT ;
    USE SIGNAL ;
    PORT
      LAYER M4 ;
        RECT  220.236 9.792 220.32 9.816 ;
    END
  END o_rd[49]
  PIN o_rd[4]
    DIRECTION OUTPUT ;
    USE SIGNAL ;
    PORT
      LAYER M4 ;
        RECT  220.236 5.472 220.32 5.496 ;
    END
  END o_rd[4]
  PIN o_rd[50]
    DIRECTION OUTPUT ;
    USE SIGNAL ;
    PORT
      LAYER M4 ;
        RECT  220.236 9.888 220.32 9.912 ;
    END
  END o_rd[50]
  PIN o_rd[51]
    DIRECTION OUTPUT ;
    USE SIGNAL ;
    PORT
      LAYER M4 ;
        RECT  220.236 9.984 220.32 10.008 ;
    END
  END o_rd[51]
  PIN o_rd[52]
    DIRECTION OUTPUT ;
    USE SIGNAL ;
    PORT
      LAYER M4 ;
        RECT  220.236 10.08 220.32 10.104 ;
    END
  END o_rd[52]
  PIN o_rd[53]
    DIRECTION OUTPUT ;
    USE SIGNAL ;
    PORT
      LAYER M4 ;
        RECT  220.236 10.176 220.32 10.2 ;
    END
  END o_rd[53]
  PIN o_rd[54]
    DIRECTION OUTPUT ;
    USE SIGNAL ;
    PORT
      LAYER M4 ;
        RECT  220.236 10.272 220.32 10.296 ;
    END
  END o_rd[54]
  PIN o_rd[55]
    DIRECTION OUTPUT ;
    USE SIGNAL ;
    PORT
      LAYER M4 ;
        RECT  220.236 10.368 220.32 10.392 ;
    END
  END o_rd[55]
  PIN o_rd[56]
    DIRECTION OUTPUT ;
    USE SIGNAL ;
    PORT
      LAYER M4 ;
        RECT  220.236 10.464 220.32 10.488 ;
    END
  END o_rd[56]
  PIN o_rd[57]
    DIRECTION OUTPUT ;
    USE SIGNAL ;
    PORT
      LAYER M4 ;
        RECT  220.236 10.56 220.32 10.584 ;
    END
  END o_rd[57]
  PIN o_rd[58]
    DIRECTION OUTPUT ;
    USE SIGNAL ;
    PORT
      LAYER M4 ;
        RECT  220.236 10.656 220.32 10.68 ;
    END
  END o_rd[58]
  PIN o_rd[59]
    DIRECTION OUTPUT ;
    USE SIGNAL ;
    PORT
      LAYER M4 ;
        RECT  220.236 10.752 220.32 10.776 ;
    END
  END o_rd[59]
  PIN o_rd[5]
    DIRECTION OUTPUT ;
    USE SIGNAL ;
    PORT
      LAYER M4 ;
        RECT  220.236 5.568 220.32 5.592 ;
    END
  END o_rd[5]
  PIN o_rd[60]
    DIRECTION OUTPUT ;
    USE SIGNAL ;
    PORT
      LAYER M4 ;
        RECT  220.236 10.848 220.32 10.872 ;
    END
  END o_rd[60]
  PIN o_rd[61]
    DIRECTION OUTPUT ;
    USE SIGNAL ;
    PORT
      LAYER M4 ;
        RECT  220.236 10.944 220.32 10.968 ;
    END
  END o_rd[61]
  PIN o_rd[62]
    DIRECTION OUTPUT ;
    USE SIGNAL ;
    PORT
      LAYER M4 ;
        RECT  220.236 11.04 220.32 11.064 ;
    END
  END o_rd[62]
  PIN o_rd[63]
    DIRECTION OUTPUT ;
    USE SIGNAL ;
    PORT
      LAYER M4 ;
        RECT  220.236 11.136 220.32 11.16 ;
    END
  END o_rd[63]
  PIN o_rd[64]
    DIRECTION OUTPUT ;
    USE SIGNAL ;
    PORT
      LAYER M4 ;
        RECT  220.236 11.232 220.32 11.256 ;
    END
  END o_rd[64]
  PIN o_rd[65]
    DIRECTION OUTPUT ;
    USE SIGNAL ;
    PORT
      LAYER M4 ;
        RECT  220.236 11.328 220.32 11.352 ;
    END
  END o_rd[65]
  PIN o_rd[66]
    DIRECTION OUTPUT ;
    USE SIGNAL ;
    PORT
      LAYER M4 ;
        RECT  220.236 11.424 220.32 11.448 ;
    END
  END o_rd[66]
  PIN o_rd[67]
    DIRECTION OUTPUT ;
    USE SIGNAL ;
    PORT
      LAYER M4 ;
        RECT  220.236 11.52 220.32 11.544 ;
    END
  END o_rd[67]
  PIN o_rd[68]
    DIRECTION OUTPUT ;
    USE SIGNAL ;
    PORT
      LAYER M4 ;
        RECT  220.236 11.616 220.32 11.64 ;
    END
  END o_rd[68]
  PIN o_rd[69]
    DIRECTION OUTPUT ;
    USE SIGNAL ;
    PORT
      LAYER M4 ;
        RECT  220.236 11.712 220.32 11.736 ;
    END
  END o_rd[69]
  PIN o_rd[6]
    DIRECTION OUTPUT ;
    USE SIGNAL ;
    PORT
      LAYER M4 ;
        RECT  220.236 5.664 220.32 5.688 ;
    END
  END o_rd[6]
  PIN o_rd[70]
    DIRECTION OUTPUT ;
    USE SIGNAL ;
    PORT
      LAYER M4 ;
        RECT  220.236 11.808 220.32 11.832 ;
    END
  END o_rd[70]
  PIN o_rd[71]
    DIRECTION OUTPUT ;
    USE SIGNAL ;
    PORT
      LAYER M4 ;
        RECT  220.236 11.904 220.32 11.928 ;
    END
  END o_rd[71]
  PIN o_rd[72]
    DIRECTION OUTPUT ;
    USE SIGNAL ;
    PORT
      LAYER M4 ;
        RECT  220.236 12 220.32 12.024 ;
    END
  END o_rd[72]
  PIN o_rd[73]
    DIRECTION OUTPUT ;
    USE SIGNAL ;
    PORT
      LAYER M4 ;
        RECT  220.236 12.096 220.32 12.12 ;
    END
  END o_rd[73]
  PIN o_rd[74]
    DIRECTION OUTPUT ;
    USE SIGNAL ;
    PORT
      LAYER M4 ;
        RECT  220.236 12.192 220.32 12.216 ;
    END
  END o_rd[74]
  PIN o_rd[75]
    DIRECTION OUTPUT ;
    USE SIGNAL ;
    PORT
      LAYER M4 ;
        RECT  220.236 12.288 220.32 12.312 ;
    END
  END o_rd[75]
  PIN o_rd[76]
    DIRECTION OUTPUT ;
    USE SIGNAL ;
    PORT
      LAYER M4 ;
        RECT  220.236 12.384 220.32 12.408 ;
    END
  END o_rd[76]
  PIN o_rd[77]
    DIRECTION OUTPUT ;
    USE SIGNAL ;
    PORT
      LAYER M4 ;
        RECT  220.236 12.48 220.32 12.504 ;
    END
  END o_rd[77]
  PIN o_rd[78]
    DIRECTION OUTPUT ;
    USE SIGNAL ;
    PORT
      LAYER M4 ;
        RECT  220.236 12.576 220.32 12.6 ;
    END
  END o_rd[78]
  PIN o_rd[79]
    DIRECTION OUTPUT ;
    USE SIGNAL ;
    PORT
      LAYER M4 ;
        RECT  220.236 12.672 220.32 12.696 ;
    END
  END o_rd[79]
  PIN o_rd[7]
    DIRECTION OUTPUT ;
    USE SIGNAL ;
    PORT
      LAYER M4 ;
        RECT  220.236 5.76 220.32 5.784 ;
    END
  END o_rd[7]
  PIN o_rd[80]
    DIRECTION OUTPUT ;
    USE SIGNAL ;
    PORT
      LAYER M4 ;
        RECT  220.236 12.768 220.32 12.792 ;
    END
  END o_rd[80]
  PIN o_rd[81]
    DIRECTION OUTPUT ;
    USE SIGNAL ;
    PORT
      LAYER M4 ;
        RECT  220.236 12.864 220.32 12.888 ;
    END
  END o_rd[81]
  PIN o_rd[82]
    DIRECTION OUTPUT ;
    USE SIGNAL ;
    PORT
      LAYER M4 ;
        RECT  220.236 12.96 220.32 12.984 ;
    END
  END o_rd[82]
  PIN o_rd[83]
    DIRECTION OUTPUT ;
    USE SIGNAL ;
    PORT
      LAYER M4 ;
        RECT  220.236 13.056 220.32 13.08 ;
    END
  END o_rd[83]
  PIN o_rd[84]
    DIRECTION OUTPUT ;
    USE SIGNAL ;
    PORT
      LAYER M4 ;
        RECT  220.236 13.152 220.32 13.176 ;
    END
  END o_rd[84]
  PIN o_rd[85]
    DIRECTION OUTPUT ;
    USE SIGNAL ;
    PORT
      LAYER M4 ;
        RECT  220.236 13.248 220.32 13.272 ;
    END
  END o_rd[85]
  PIN o_rd[86]
    DIRECTION OUTPUT ;
    USE SIGNAL ;
    PORT
      LAYER M4 ;
        RECT  220.236 13.344 220.32 13.368 ;
    END
  END o_rd[86]
  PIN o_rd[87]
    DIRECTION OUTPUT ;
    USE SIGNAL ;
    PORT
      LAYER M4 ;
        RECT  220.236 13.44 220.32 13.464 ;
    END
  END o_rd[87]
  PIN o_rd[88]
    DIRECTION OUTPUT ;
    USE SIGNAL ;
    PORT
      LAYER M4 ;
        RECT  220.236 13.536 220.32 13.56 ;
    END
  END o_rd[88]
  PIN o_rd[89]
    DIRECTION OUTPUT ;
    USE SIGNAL ;
    PORT
      LAYER M4 ;
        RECT  220.236 13.632 220.32 13.656 ;
    END
  END o_rd[89]
  PIN o_rd[8]
    DIRECTION OUTPUT ;
    USE SIGNAL ;
    PORT
      LAYER M4 ;
        RECT  220.236 5.856 220.32 5.88 ;
    END
  END o_rd[8]
  PIN o_rd[90]
    DIRECTION OUTPUT ;
    USE SIGNAL ;
    PORT
      LAYER M4 ;
        RECT  220.236 13.728 220.32 13.752 ;
    END
  END o_rd[90]
  PIN o_rd[91]
    DIRECTION OUTPUT ;
    USE SIGNAL ;
    PORT
      LAYER M4 ;
        RECT  220.236 13.824 220.32 13.848 ;
    END
  END o_rd[91]
  PIN o_rd[92]
    DIRECTION OUTPUT ;
    USE SIGNAL ;
    PORT
      LAYER M4 ;
        RECT  220.236 13.92 220.32 13.944 ;
    END
  END o_rd[92]
  PIN o_rd[93]
    DIRECTION OUTPUT ;
    USE SIGNAL ;
    PORT
      LAYER M4 ;
        RECT  220.236 14.016 220.32 14.04 ;
    END
  END o_rd[93]
  PIN o_rd[94]
    DIRECTION OUTPUT ;
    USE SIGNAL ;
    PORT
      LAYER M4 ;
        RECT  220.236 14.112 220.32 14.136 ;
    END
  END o_rd[94]
  PIN o_rd[95]
    DIRECTION OUTPUT ;
    USE SIGNAL ;
    PORT
      LAYER M4 ;
        RECT  220.236 14.208 220.32 14.232 ;
    END
  END o_rd[95]
  PIN o_rd[96]
    DIRECTION OUTPUT ;
    USE SIGNAL ;
    PORT
      LAYER M4 ;
        RECT  220.236 14.304 220.32 14.328 ;
    END
  END o_rd[96]
  PIN o_rd[97]
    DIRECTION OUTPUT ;
    USE SIGNAL ;
    PORT
      LAYER M4 ;
        RECT  220.236 14.4 220.32 14.424 ;
    END
  END o_rd[97]
  PIN o_rd[98]
    DIRECTION OUTPUT ;
    USE SIGNAL ;
    PORT
      LAYER M4 ;
        RECT  220.236 14.496 220.32 14.52 ;
    END
  END o_rd[98]
  PIN o_rd[99]
    DIRECTION OUTPUT ;
    USE SIGNAL ;
    PORT
      LAYER M4 ;
        RECT  220.236 14.592 220.32 14.616 ;
    END
  END o_rd[99]
  PIN o_rd[9]
    DIRECTION OUTPUT ;
    USE SIGNAL ;
    PORT
      LAYER M4 ;
        RECT  220.236 5.952 220.32 5.976 ;
    END
  END o_rd[9]
  PIN o_rt[0]
    DIRECTION OUTPUT ;
    USE SIGNAL ;
    PORT
      LAYER M4 ;
        RECT  220.236 18.336 220.32 18.36 ;
    END
  END o_rt[0]
  PIN o_rt[1]
    DIRECTION OUTPUT ;
    USE SIGNAL ;
    PORT
      LAYER M4 ;
        RECT  220.236 18.432 220.32 18.456 ;
    END
  END o_rt[1]
  PIN o_rt[2]
    DIRECTION OUTPUT ;
    USE SIGNAL ;
    PORT
      LAYER M4 ;
        RECT  220.236 18.528 220.32 18.552 ;
    END
  END o_rt[2]
  PIN o_rt[3]
    DIRECTION OUTPUT ;
    USE SIGNAL ;
    PORT
      LAYER M4 ;
        RECT  220.236 18.624 220.32 18.648 ;
    END
  END o_rt[3]
  PIN o_rt[4]
    DIRECTION OUTPUT ;
    USE SIGNAL ;
    PORT
      LAYER M4 ;
        RECT  220.236 18.72 220.32 18.744 ;
    END
  END o_rt[4]
  PIN o_rt[5]
    DIRECTION OUTPUT ;
    USE SIGNAL ;
    PORT
      LAYER M4 ;
        RECT  220.236 18.816 220.32 18.84 ;
    END
  END o_rt[5]
  PIN o_rt[6]
    DIRECTION OUTPUT ;
    USE SIGNAL ;
    PORT
      LAYER M4 ;
        RECT  220.236 18.912 220.32 18.936 ;
    END
  END o_rt[6]
  PIN o_rt[7]
    DIRECTION OUTPUT ;
    USE SIGNAL ;
    PORT
      LAYER M4 ;
        RECT  220.236 19.008 220.32 19.032 ;
    END
  END o_rt[7]
  PIN o_rv
    DIRECTION OUTPUT ;
    USE SIGNAL ;
    PORT
      LAYER M4 ;
        RECT  220.236 4.032 220.32 4.056 ;
    END
    PORT
      LAYER M4 ;
        RECT  220.277 4.032 220.284 4.056 ;
    END
  END o_rv
  PIN rst_n
    DIRECTION INPUT ;
    USE SIGNAL ;
    PORT
      LAYER M3 ;
        RECT  5.004 75.562 5.022 75.6 ;
    END
    PORT
      LAYER M3 ;
        RECT  5.004 70.709 5.022 75.581 ;
    END
  END rst_n
  PIN VDD
    DIRECTION INOUT ;
    USE POWER ;
    PORT
      LAYER M5 ;
        RECT  213.192 2.151 213.312 73.449 ;
        RECT  207.792 2.151 207.912 73.449 ;
        RECT  202.392 2.151 202.512 73.449 ;
        RECT  196.992 2.151 197.112 73.449 ;
        RECT  191.592 2.151 191.712 73.449 ;
        RECT  186.192 2.151 186.312 73.449 ;
        RECT  180.792 2.151 180.912 73.449 ;
        RECT  175.392 2.151 175.512 73.449 ;
        RECT  169.992 2.151 170.112 73.449 ;
        RECT  164.592 2.151 164.712 73.449 ;
        RECT  159.192 2.151 159.312 73.449 ;
        RECT  153.792 2.151 153.912 73.449 ;
        RECT  148.392 2.151 148.512 73.449 ;
        RECT  142.992 2.151 143.112 73.449 ;
        RECT  137.592 2.151 137.712 73.449 ;
        RECT  132.192 2.151 132.312 73.449 ;
        RECT  126.792 2.151 126.912 73.449 ;
        RECT  121.392 2.151 121.512 73.449 ;
        RECT  115.992 2.151 116.112 73.449 ;
        RECT  110.592 2.151 110.712 73.449 ;
        RECT  105.192 2.151 105.312 73.449 ;
        RECT  99.792 2.151 99.912 73.449 ;
        RECT  94.392 2.151 94.512 73.449 ;
        RECT  88.992 2.151 89.112 73.449 ;
        RECT  83.592 2.151 83.712 73.449 ;
        RECT  78.192 2.151 78.312 73.449 ;
        RECT  72.792 2.151 72.912 73.449 ;
        RECT  67.392 2.151 67.512 73.449 ;
        RECT  61.992 2.151 62.112 73.449 ;
        RECT  56.592 2.151 56.712 73.449 ;
        RECT  51.192 2.151 51.312 73.449 ;
        RECT  45.792 2.151 45.912 73.449 ;
        RECT  40.392 2.151 40.512 73.449 ;
        RECT  34.992 2.151 35.112 73.449 ;
        RECT  29.592 2.151 29.712 73.449 ;
        RECT  24.192 2.151 24.312 73.449 ;
        RECT  18.792 2.151 18.912 73.449 ;
        RECT  13.392 2.151 13.512 73.449 ;
        RECT  7.992 2.151 8.112 73.449 ;
        RECT  2.592 2.151 2.712 73.449 ;
    END
  END VDD
  PIN VSS
    DIRECTION INOUT ;
    USE GROUND ;
    PORT
      LAYER M5 ;
        RECT  213 2.137 213.12 73.463 ;
        RECT  207.6 2.137 207.72 73.463 ;
        RECT  202.2 2.137 202.32 73.463 ;
        RECT  196.8 2.137 196.92 73.463 ;
        RECT  191.4 2.137 191.52 73.463 ;
        RECT  186 2.137 186.12 73.463 ;
        RECT  180.6 2.137 180.72 73.463 ;
        RECT  175.2 2.137 175.32 73.463 ;
        RECT  169.8 2.137 169.92 73.463 ;
        RECT  164.4 2.137 164.52 73.463 ;
        RECT  159 2.137 159.12 73.463 ;
        RECT  153.6 2.137 153.72 73.463 ;
        RECT  148.2 2.137 148.32 73.463 ;
        RECT  142.8 2.137 142.92 73.463 ;
        RECT  137.4 2.137 137.52 73.463 ;
        RECT  132 2.137 132.12 73.463 ;
        RECT  126.6 2.137 126.72 73.463 ;
        RECT  121.2 2.137 121.32 73.463 ;
        RECT  115.8 2.137 115.92 73.463 ;
        RECT  110.4 2.137 110.52 73.463 ;
        RECT  105 2.137 105.12 73.463 ;
        RECT  99.6 2.137 99.72 73.463 ;
        RECT  94.2 2.137 94.32 73.463 ;
        RECT  88.8 2.137 88.92 73.463 ;
        RECT  83.4 2.137 83.52 73.463 ;
        RECT  78 2.137 78.12 73.463 ;
        RECT  72.6 2.137 72.72 73.463 ;
        RECT  67.2 2.137 67.32 73.463 ;
        RECT  61.8 2.137 61.92 73.463 ;
        RECT  56.4 2.137 56.52 73.463 ;
        RECT  51 2.137 51.12 73.463 ;
        RECT  45.6 2.137 45.72 73.463 ;
        RECT  40.2 2.137 40.32 73.463 ;
        RECT  34.8 2.137 34.92 73.463 ;
        RECT  29.4 2.137 29.52 73.463 ;
        RECT  24 2.137 24.12 73.463 ;
        RECT  18.6 2.137 18.72 73.463 ;
        RECT  13.2 2.137 13.32 73.463 ;
        RECT  7.8 2.137 7.92 73.463 ;
        RECT  2.4 2.137 2.52 73.463 ;
    END
  END VSS
  # OT_OBS_CLOSED layer=M5 d_um=1.536 added=0
  OBS
    LAYER RVTN ;
     RECT  2.16 2.16 218.16 2.295 ;
     RECT  2.16 2.565 218.16 2.835 ;
     RECT  2.16 3.105 218.16 3.375 ;
     RECT  2.16 3.645 218.16 3.915 ;
     RECT  2.16 4.185 218.16 4.455 ;
     RECT  2.16 4.725 218.16 4.995 ;
     RECT  2.16 5.265 218.16 5.535 ;
     RECT  2.16 5.805 218.16 6.075 ;
     RECT  2.16 6.345 218.16 6.615 ;
     RECT  2.16 6.885 218.16 7.155 ;
     RECT  2.16 7.425 218.16 7.695 ;
     RECT  2.16 7.965 218.16 8.235 ;
     RECT  2.16 8.505 218.16 8.775 ;
     RECT  2.16 9.045 218.16 9.315 ;
     RECT  2.16 9.585 218.16 9.855 ;
     RECT  2.16 10.125 218.16 10.395 ;
     RECT  2.16 10.665 218.16 10.935 ;
     RECT  2.16 11.205 218.16 11.475 ;
     RECT  2.16 11.745 218.16 12.015 ;
     RECT  2.16 12.285 218.16 12.555 ;
     RECT  2.16 12.825 218.16 13.095 ;
     RECT  2.16 13.365 218.16 13.635 ;
     RECT  2.16 13.905 218.16 14.175 ;
     RECT  2.16 14.445 218.16 14.715 ;
     RECT  2.16 14.985 218.16 15.255 ;
     RECT  2.16 15.525 218.16 15.795 ;
     RECT  2.16 16.065 218.16 16.335 ;
     RECT  2.16 16.605 218.16 16.875 ;
     RECT  2.16 17.145 218.16 17.415 ;
     RECT  2.16 17.685 218.16 17.955 ;
     RECT  2.16 18.225 218.16 18.495 ;
     RECT  2.16 18.765 218.16 19.035 ;
     RECT  2.16 19.305 218.16 19.575 ;
     RECT  2.16 19.845 218.16 20.115 ;
     RECT  2.16 20.385 21.276 20.655 ;
     RECT  199.476 20.385 218.16 20.655 ;
     RECT  2.16 20.925 21.276 21.195 ;
     RECT  199.476 20.925 218.16 21.195 ;
     RECT  2.16 21.465 21.276 21.735 ;
     RECT  199.476 21.465 218.16 21.735 ;
     RECT  2.16 22.005 21.276 22.275 ;
     RECT  199.476 22.005 218.16 22.275 ;
     RECT  2.16 22.545 21.276 22.815 ;
     RECT  199.476 22.545 218.16 22.815 ;
     RECT  2.16 23.085 21.276 23.355 ;
     RECT  199.476 23.085 218.16 23.355 ;
     RECT  2.16 23.625 21.276 23.895 ;
     RECT  199.476 23.625 218.16 23.895 ;
     RECT  2.16 24.165 21.276 24.435 ;
     RECT  199.476 24.165 218.16 24.435 ;
     RECT  2.16 24.705 21.276 24.975 ;
     RECT  199.476 24.705 218.16 24.975 ;
     RECT  2.16 25.245 21.276 25.515 ;
     RECT  199.476 25.245 218.16 25.515 ;
     RECT  2.16 25.785 21.276 26.055 ;
     RECT  199.476 25.785 218.16 26.055 ;
     RECT  2.16 26.325 21.276 26.595 ;
     RECT  199.476 26.325 218.16 26.595 ;
     RECT  2.16 26.865 21.276 27.135 ;
     RECT  199.476 26.865 218.16 27.135 ;
     RECT  2.16 27.405 21.276 27.675 ;
     RECT  199.476 27.405 218.16 27.675 ;
     RECT  2.16 27.945 21.276 28.215 ;
     RECT  199.476 27.945 218.16 28.215 ;
     RECT  2.16 28.485 21.276 28.755 ;
     RECT  199.476 28.485 218.16 28.755 ;
     RECT  2.16 29.025 21.276 29.295 ;
     RECT  199.476 29.025 218.16 29.295 ;
     RECT  2.16 29.565 21.276 29.835 ;
     RECT  199.476 29.565 218.16 29.835 ;
     RECT  2.16 30.105 21.276 30.375 ;
     RECT  199.476 30.105 218.16 30.375 ;
     RECT  2.16 30.645 21.276 30.915 ;
     RECT  199.476 30.645 218.16 30.915 ;
     RECT  2.16 31.185 21.276 31.455 ;
     RECT  199.476 31.185 218.16 31.455 ;
     RECT  2.16 31.725 21.276 31.995 ;
     RECT  199.476 31.725 218.16 31.995 ;
     RECT  2.16 32.265 21.276 32.535 ;
     RECT  199.476 32.265 218.16 32.535 ;
     RECT  2.16 32.805 21.276 33.075 ;
     RECT  199.476 32.805 218.16 33.075 ;
     RECT  2.16 33.345 21.276 33.615 ;
     RECT  199.476 33.345 218.16 33.615 ;
     RECT  2.16 33.885 21.276 34.155 ;
     RECT  199.476 33.885 218.16 34.155 ;
     RECT  2.16 34.425 21.276 34.695 ;
     RECT  199.476 34.425 218.16 34.695 ;
     RECT  2.16 34.965 21.276 35.235 ;
     RECT  199.476 34.965 218.16 35.235 ;
     RECT  2.16 35.505 21.276 35.775 ;
     RECT  199.476 35.505 218.16 35.775 ;
     RECT  2.16 36.045 21.276 36.315 ;
     RECT  199.476 36.045 218.16 36.315 ;
     RECT  2.16 36.585 21.276 36.855 ;
     RECT  199.476 36.585 218.16 36.855 ;
     RECT  2.16 37.125 21.276 37.395 ;
     RECT  199.476 37.125 218.16 37.395 ;
     RECT  2.16 37.665 21.276 37.935 ;
     RECT  199.476 37.665 218.16 37.935 ;
     RECT  2.16 38.205 21.276 38.475 ;
     RECT  199.476 38.205 218.16 38.475 ;
     RECT  2.16 38.745 21.276 39.015 ;
     RECT  199.476 38.745 218.16 39.015 ;
     RECT  2.16 39.285 21.276 39.555 ;
     RECT  199.476 39.285 218.16 39.555 ;
     RECT  2.16 39.825 21.276 40.095 ;
     RECT  199.476 39.825 218.16 40.095 ;
     RECT  2.16 40.365 21.276 40.635 ;
     RECT  199.476 40.365 218.16 40.635 ;
     RECT  2.16 40.905 21.276 41.175 ;
     RECT  199.476 40.905 218.16 41.175 ;
     RECT  2.16 41.445 21.276 41.715 ;
     RECT  199.476 41.445 218.16 41.715 ;
     RECT  2.16 41.985 21.276 42.255 ;
     RECT  199.476 41.985 218.16 42.255 ;
     RECT  2.16 42.525 21.276 42.795 ;
     RECT  199.476 42.525 218.16 42.795 ;
     RECT  2.16 43.065 21.276 43.335 ;
     RECT  199.476 43.065 218.16 43.335 ;
     RECT  2.16 43.605 21.276 43.875 ;
     RECT  199.476 43.605 218.16 43.875 ;
     RECT  2.16 44.145 21.276 44.415 ;
     RECT  199.476 44.145 218.16 44.415 ;
     RECT  2.16 44.685 21.276 44.955 ;
     RECT  199.476 44.685 218.16 44.955 ;
     RECT  2.16 45.225 21.276 45.495 ;
     RECT  199.476 45.225 218.16 45.495 ;
     RECT  2.16 45.765 21.276 46.035 ;
     RECT  199.476 45.765 218.16 46.035 ;
     RECT  2.16 46.305 21.276 46.575 ;
     RECT  199.476 46.305 218.16 46.575 ;
     RECT  2.16 46.845 21.276 47.115 ;
     RECT  199.476 46.845 218.16 47.115 ;
     RECT  2.16 47.385 21.276 47.655 ;
     RECT  199.476 47.385 218.16 47.655 ;
     RECT  2.16 47.925 21.276 48.195 ;
     RECT  199.476 47.925 218.16 48.195 ;
     RECT  2.16 48.465 21.276 48.735 ;
     RECT  199.476 48.465 218.16 48.735 ;
     RECT  2.16 49.005 21.276 49.275 ;
     RECT  199.476 49.005 218.16 49.275 ;
     RECT  2.16 49.545 21.276 49.815 ;
     RECT  199.476 49.545 218.16 49.815 ;
     RECT  2.16 50.085 21.276 50.355 ;
     RECT  199.476 50.085 218.16 50.355 ;
     RECT  2.16 50.625 21.276 50.895 ;
     RECT  199.476 50.625 218.16 50.895 ;
     RECT  2.16 51.165 21.276 51.435 ;
     RECT  199.476 51.165 218.16 51.435 ;
     RECT  2.16 51.705 21.276 51.975 ;
     RECT  199.476 51.705 218.16 51.975 ;
     RECT  2.16 52.245 21.276 52.515 ;
     RECT  199.476 52.245 218.16 52.515 ;
     RECT  2.16 52.785 21.276 53.055 ;
     RECT  199.476 52.785 218.16 53.055 ;
     RECT  2.16 53.325 21.276 53.595 ;
     RECT  199.476 53.325 218.16 53.595 ;
     RECT  2.16 53.865 21.276 54.135 ;
     RECT  199.476 53.865 218.16 54.135 ;
     RECT  2.16 54.405 218.16 54.675 ;
     RECT  2.16 54.945 218.16 55.215 ;
     RECT  2.16 55.485 218.16 55.755 ;
     RECT  2.16 56.025 218.16 56.295 ;
     RECT  2.16 56.565 218.16 56.835 ;
     RECT  2.16 57.105 218.16 57.375 ;
     RECT  2.16 57.645 218.16 57.915 ;
     RECT  2.16 58.185 218.16 58.455 ;
     RECT  2.16 58.725 218.16 58.995 ;
     RECT  2.16 59.265 218.16 59.535 ;
     RECT  2.16 59.805 218.16 60.075 ;
     RECT  2.16 60.345 218.16 60.615 ;
     RECT  2.16 60.885 218.16 61.155 ;
     RECT  2.16 61.425 218.16 61.695 ;
     RECT  2.16 61.965 218.16 62.235 ;
     RECT  2.16 62.505 218.16 62.775 ;
     RECT  2.16 63.045 218.16 63.315 ;
     RECT  2.16 63.585 218.16 63.855 ;
     RECT  2.16 64.125 218.16 64.395 ;
     RECT  2.16 64.665 218.16 64.935 ;
     RECT  2.16 65.205 218.16 65.475 ;
     RECT  2.16 65.745 218.16 66.015 ;
     RECT  2.16 66.285 218.16 66.555 ;
     RECT  2.16 66.825 218.16 67.095 ;
     RECT  2.16 67.365 218.16 67.635 ;
     RECT  2.16 67.905 218.16 68.175 ;
     RECT  2.16 68.445 218.16 68.715 ;
     RECT  2.16 68.985 218.16 69.255 ;
     RECT  2.16 69.525 218.16 69.795 ;
     RECT  2.16 70.065 218.16 70.335 ;
     RECT  2.16 70.605 218.16 70.875 ;
     RECT  2.16 71.145 218.16 71.415 ;
     RECT  2.16 71.685 218.16 71.955 ;
     RECT  2.16 72.225 218.16 72.495 ;
     RECT  2.16 72.765 218.16 73.035 ;
     RECT  2.16 73.305 218.16 73.44 ;
    LAYER RVTP ;
     RECT  2.16 2.295 218.16 2.565 ;
     RECT  2.16 2.835 218.16 3.105 ;
     RECT  2.16 3.375 218.16 3.645 ;
     RECT  2.16 3.915 218.16 4.185 ;
     RECT  2.16 4.455 218.16 4.725 ;
     RECT  2.16 4.995 218.16 5.265 ;
     RECT  2.16 5.535 218.16 5.805 ;
     RECT  2.16 6.075 218.16 6.345 ;
     RECT  2.16 6.615 218.16 6.885 ;
     RECT  2.16 7.155 218.16 7.425 ;
     RECT  2.16 7.695 218.16 7.965 ;
     RECT  2.16 8.235 218.16 8.505 ;
     RECT  2.16 8.775 218.16 9.045 ;
     RECT  2.16 9.315 218.16 9.585 ;
     RECT  2.16 9.855 218.16 10.125 ;
     RECT  2.16 10.395 218.16 10.665 ;
     RECT  2.16 10.935 218.16 11.205 ;
     RECT  2.16 11.475 218.16 11.745 ;
     RECT  2.16 12.015 218.16 12.285 ;
     RECT  2.16 12.555 218.16 12.825 ;
     RECT  2.16 13.095 218.16 13.365 ;
     RECT  2.16 13.635 218.16 13.905 ;
     RECT  2.16 14.175 218.16 14.445 ;
     RECT  2.16 14.715 218.16 14.985 ;
     RECT  2.16 15.255 218.16 15.525 ;
     RECT  2.16 15.795 218.16 16.065 ;
     RECT  2.16 16.335 218.16 16.605 ;
     RECT  2.16 16.875 218.16 17.145 ;
     RECT  2.16 17.415 218.16 17.685 ;
     RECT  2.16 17.955 218.16 18.225 ;
     RECT  2.16 18.495 218.16 18.765 ;
     RECT  2.16 19.035 218.16 19.305 ;
     RECT  2.16 19.575 218.16 19.845 ;
     RECT  2.16 20.115 218.16 20.25 ;
     RECT  2.16 20.25 21.276 20.385 ;
     RECT  199.476 20.25 218.16 20.385 ;
     RECT  2.16 20.655 21.276 20.925 ;
     RECT  199.476 20.655 218.16 20.925 ;
     RECT  2.16 21.195 21.276 21.465 ;
     RECT  199.476 21.195 218.16 21.465 ;
     RECT  2.16 21.735 21.276 22.005 ;
     RECT  199.476 21.735 218.16 22.005 ;
     RECT  2.16 22.275 21.276 22.545 ;
     RECT  199.476 22.275 218.16 22.545 ;
     RECT  2.16 22.815 21.276 23.085 ;
     RECT  199.476 22.815 218.16 23.085 ;
     RECT  2.16 23.355 21.276 23.625 ;
     RECT  199.476 23.355 218.16 23.625 ;
     RECT  2.16 23.895 21.276 24.165 ;
     RECT  199.476 23.895 218.16 24.165 ;
     RECT  2.16 24.435 21.276 24.705 ;
     RECT  199.476 24.435 218.16 24.705 ;
     RECT  2.16 24.975 21.276 25.245 ;
     RECT  199.476 24.975 218.16 25.245 ;
     RECT  2.16 25.515 21.276 25.785 ;
     RECT  199.476 25.515 218.16 25.785 ;
     RECT  2.16 26.055 21.276 26.325 ;
     RECT  199.476 26.055 218.16 26.325 ;
     RECT  2.16 26.595 21.276 26.865 ;
     RECT  199.476 26.595 218.16 26.865 ;
     RECT  2.16 27.135 21.276 27.405 ;
     RECT  199.476 27.135 218.16 27.405 ;
     RECT  2.16 27.675 21.276 27.945 ;
     RECT  199.476 27.675 218.16 27.945 ;
     RECT  2.16 28.215 21.276 28.485 ;
     RECT  199.476 28.215 218.16 28.485 ;
     RECT  2.16 28.755 21.276 29.025 ;
     RECT  199.476 28.755 218.16 29.025 ;
     RECT  2.16 29.295 21.276 29.565 ;
     RECT  199.476 29.295 218.16 29.565 ;
     RECT  2.16 29.835 21.276 30.105 ;
     RECT  199.476 29.835 218.16 30.105 ;
     RECT  2.16 30.375 21.276 30.645 ;
     RECT  199.476 30.375 218.16 30.645 ;
     RECT  2.16 30.915 21.276 31.185 ;
     RECT  199.476 30.915 218.16 31.185 ;
     RECT  2.16 31.455 21.276 31.725 ;
     RECT  199.476 31.455 218.16 31.725 ;
     RECT  2.16 31.995 21.276 32.265 ;
     RECT  199.476 31.995 218.16 32.265 ;
     RECT  2.16 32.535 21.276 32.805 ;
     RECT  199.476 32.535 218.16 32.805 ;
     RECT  2.16 33.075 21.276 33.345 ;
     RECT  199.476 33.075 218.16 33.345 ;
     RECT  2.16 33.615 21.276 33.885 ;
     RECT  199.476 33.615 218.16 33.885 ;
     RECT  2.16 34.155 21.276 34.425 ;
     RECT  199.476 34.155 218.16 34.425 ;
     RECT  2.16 34.695 21.276 34.965 ;
     RECT  199.476 34.695 218.16 34.965 ;
     RECT  2.16 35.235 21.276 35.505 ;
     RECT  199.476 35.235 218.16 35.505 ;
     RECT  2.16 35.775 21.276 36.045 ;
     RECT  199.476 35.775 218.16 36.045 ;
     RECT  2.16 36.315 21.276 36.585 ;
     RECT  199.476 36.315 218.16 36.585 ;
     RECT  2.16 36.855 21.276 37.125 ;
     RECT  199.476 36.855 218.16 37.125 ;
     RECT  2.16 37.395 21.276 37.665 ;
     RECT  199.476 37.395 218.16 37.665 ;
     RECT  2.16 37.935 21.276 38.205 ;
     RECT  199.476 37.935 218.16 38.205 ;
     RECT  2.16 38.475 21.276 38.745 ;
     RECT  199.476 38.475 218.16 38.745 ;
     RECT  2.16 39.015 21.276 39.285 ;
     RECT  199.476 39.015 218.16 39.285 ;
     RECT  2.16 39.555 21.276 39.825 ;
     RECT  199.476 39.555 218.16 39.825 ;
     RECT  2.16 40.095 21.276 40.365 ;
     RECT  199.476 40.095 218.16 40.365 ;
     RECT  2.16 40.635 21.276 40.905 ;
     RECT  199.476 40.635 218.16 40.905 ;
     RECT  2.16 41.175 21.276 41.445 ;
     RECT  199.476 41.175 218.16 41.445 ;
     RECT  2.16 41.715 21.276 41.985 ;
     RECT  199.476 41.715 218.16 41.985 ;
     RECT  2.16 42.255 21.276 42.525 ;
     RECT  199.476 42.255 218.16 42.525 ;
     RECT  2.16 42.795 21.276 43.065 ;
     RECT  199.476 42.795 218.16 43.065 ;
     RECT  2.16 43.335 21.276 43.605 ;
     RECT  199.476 43.335 218.16 43.605 ;
     RECT  2.16 43.875 21.276 44.145 ;
     RECT  199.476 43.875 218.16 44.145 ;
     RECT  2.16 44.415 21.276 44.685 ;
     RECT  199.476 44.415 218.16 44.685 ;
     RECT  2.16 44.955 21.276 45.225 ;
     RECT  199.476 44.955 218.16 45.225 ;
     RECT  2.16 45.495 21.276 45.765 ;
     RECT  199.476 45.495 218.16 45.765 ;
     RECT  2.16 46.035 21.276 46.305 ;
     RECT  199.476 46.035 218.16 46.305 ;
     RECT  2.16 46.575 21.276 46.845 ;
     RECT  199.476 46.575 218.16 46.845 ;
     RECT  2.16 47.115 21.276 47.385 ;
     RECT  199.476 47.115 218.16 47.385 ;
     RECT  2.16 47.655 21.276 47.925 ;
     RECT  199.476 47.655 218.16 47.925 ;
     RECT  2.16 48.195 21.276 48.465 ;
     RECT  199.476 48.195 218.16 48.465 ;
     RECT  2.16 48.735 21.276 49.005 ;
     RECT  199.476 48.735 218.16 49.005 ;
     RECT  2.16 49.275 21.276 49.545 ;
     RECT  199.476 49.275 218.16 49.545 ;
     RECT  2.16 49.815 21.276 50.085 ;
     RECT  199.476 49.815 218.16 50.085 ;
     RECT  2.16 50.355 21.276 50.625 ;
     RECT  199.476 50.355 218.16 50.625 ;
     RECT  2.16 50.895 21.276 51.165 ;
     RECT  199.476 50.895 218.16 51.165 ;
     RECT  2.16 51.435 21.276 51.705 ;
     RECT  199.476 51.435 218.16 51.705 ;
     RECT  2.16 51.975 21.276 52.245 ;
     RECT  199.476 51.975 218.16 52.245 ;
     RECT  2.16 52.515 21.276 52.785 ;
     RECT  199.476 52.515 218.16 52.785 ;
     RECT  2.16 53.055 21.276 53.325 ;
     RECT  199.476 53.055 218.16 53.325 ;
     RECT  2.16 53.595 21.276 53.865 ;
     RECT  199.476 53.595 218.16 53.865 ;
     RECT  2.16 54.135 21.276 54.27 ;
     RECT  199.476 54.135 218.16 54.27 ;
     RECT  2.16 54.27 218.16 54.405 ;
     RECT  2.16 54.675 218.16 54.945 ;
     RECT  2.16 55.215 218.16 55.485 ;
     RECT  2.16 55.755 218.16 56.025 ;
     RECT  2.16 56.295 218.16 56.565 ;
     RECT  2.16 56.835 218.16 57.105 ;
     RECT  2.16 57.375 218.16 57.645 ;
     RECT  2.16 57.915 218.16 58.185 ;
     RECT  2.16 58.455 218.16 58.725 ;
     RECT  2.16 58.995 218.16 59.265 ;
     RECT  2.16 59.535 218.16 59.805 ;
     RECT  2.16 60.075 218.16 60.345 ;
     RECT  2.16 60.615 218.16 60.885 ;
     RECT  2.16 61.155 218.16 61.425 ;
     RECT  2.16 61.695 218.16 61.965 ;
     RECT  2.16 62.235 218.16 62.505 ;
     RECT  2.16 62.775 218.16 63.045 ;
     RECT  2.16 63.315 218.16 63.585 ;
     RECT  2.16 63.855 218.16 64.125 ;
     RECT  2.16 64.395 218.16 64.665 ;
     RECT  2.16 64.935 218.16 65.205 ;
     RECT  2.16 65.475 218.16 65.745 ;
     RECT  2.16 66.015 218.16 66.285 ;
     RECT  2.16 66.555 218.16 66.825 ;
     RECT  2.16 67.095 218.16 67.365 ;
     RECT  2.16 67.635 218.16 67.905 ;
     RECT  2.16 68.175 218.16 68.445 ;
     RECT  2.16 68.715 218.16 68.985 ;
     RECT  2.16 69.255 218.16 69.525 ;
     RECT  2.16 69.795 218.16 70.065 ;
     RECT  2.16 70.335 218.16 70.605 ;
     RECT  2.16 70.875 218.16 71.145 ;
     RECT  2.16 71.415 218.16 71.685 ;
     RECT  2.16 71.955 218.16 72.225 ;
     RECT  2.16 72.495 218.16 72.765 ;
     RECT  2.16 73.035 218.16 73.305 ;
    LAYER M1 ;
     RECT  2.16 2.151 218.16 20.259 ;
     RECT  23.328 22.464 197.448 52.2 ;
     RECT  2.16 20.259 21.276 54.261 ;
     RECT  199.476 20.259 218.16 54.261 ;
     RECT  2.16 54.261 218.16 73.449 ;
    LAYER M2 ;
     RECT  1.399 8.82 1.723 8.838 ;
     RECT  1.651 25.056 1.723 25.074 ;
     RECT  0.571 26.532 1.723 26.55 ;
     RECT  1.723 5.04 1.759 5.328 ;
     RECT  1.723 6.12 1.759 6.138 ;
     RECT  1.723 7.362 1.759 7.65 ;
     RECT  1.723 8.748 1.759 8.838 ;
     RECT  1.723 11.682 1.759 15.012 ;
     RECT  1.723 16.11 1.759 16.56 ;
     RECT  1.723 17.622 1.759 18.99 ;
     RECT  1.723 19.782 1.759 20.88 ;
     RECT  1.723 22.788 1.759 23.58 ;
     RECT  1.723 24.642 1.759 25.2 ;
     RECT  1.723 27.612 1.759 27.63 ;
     RECT  1.759 7.092 1.795 7.758 ;
     RECT  1.723 9.864 1.795 9.882 ;
     RECT  1.759 11.682 1.795 15.21 ;
     RECT  1.759 16.11 1.795 20.88 ;
     RECT  1.723 21.672 1.795 21.69 ;
     RECT  1.759 22.626 1.795 23.58 ;
     RECT  1.723 26.262 1.795 26.55 ;
     RECT  1.759 8.748 1.831 9.108 ;
     RECT  1.795 9.864 1.831 9.918 ;
     RECT  1.759 24.642 1.831 25.308 ;
     RECT  1.795 26.064 1.831 26.55 ;
     RECT  1.831 24.642 2.011 26.55 ;
     RECT  2.011 24.642 2.047 26.658 ;
     RECT  1.759 27.612 2.047 27.9 ;
     RECT  1.759 5.04 2.16 6.138 ;
     RECT  1.795 7.092 2.16 7.92 ;
     RECT  1.831 8.748 2.16 9.918 ;
     RECT  1.795 11.682 2.16 20.88 ;
     RECT  1.795 21.672 2.16 23.85 ;
     RECT  2.047 24.642 2.16 27.9 ;
     RECT  2.16 2.151 21.276 73.449 ;
     RECT  21.276 28.494 21.551 28.512 ;
     RECT  21.276 2.151 21.947 23.382 ;
     RECT  22.999 36.594 23.035 36.612 ;
     RECT  21.947 2.151 23.071 22.806 ;
     RECT  23.035 24.876 23.107 25.119 ;
     RECT  23.071 2.151 23.328 22.878 ;
     RECT  23.107 24.876 23.328 25.2 ;
     RECT  23.035 26.946 23.328 26.964 ;
     RECT  23.035 29.07 23.328 29.088 ;
     RECT  23.035 31.23 23.328 31.248 ;
     RECT  23.107 33.084 23.328 33.102 ;
     RECT  21.276 35.046 23.328 35.064 ;
     RECT  23.035 36.594 23.328 36.684 ;
     RECT  23.328 2.151 197.448 52.2 ;
     RECT  197.448 34.74 197.663 35.154 ;
     RECT  197.448 2.151 197.879 22.914 ;
     RECT  197.879 2.151 198.599 22.032 ;
     RECT  198.679 26.226 198.715 26.244 ;
     RECT  198.859 25.146 198.895 25.164 ;
     RECT  197.879 22.824 198.931 22.914 ;
     RECT  198.931 41.382 198.967 43.56 ;
     RECT  198.967 41.382 199.003 44.1 ;
     RECT  198.931 44.856 199.003 44.874 ;
     RECT  199.003 41.382 199.147 44.874 ;
     RECT  198.931 22.824 199.183 23.274 ;
     RECT  199.147 41.382 199.435 44.946 ;
     RECT  198.599 2.151 199.476 21.996 ;
     RECT  199.183 22.788 199.476 23.274 ;
     RECT  198.895 24.606 199.476 25.164 ;
     RECT  198.715 26.136 199.476 26.244 ;
     RECT  197.448 28.656 199.476 28.674 ;
     RECT  197.448 31.356 199.476 32.022 ;
     RECT  197.663 35.136 199.476 35.154 ;
     RECT  199.399 40.14 199.476 40.158 ;
     RECT  199.435 41.076 199.476 44.946 ;
     RECT  21.276 54.261 199.476 73.449 ;
     RECT  199.476 2.151 214.663 73.449 ;
     RECT  214.663 2.106 216.923 73.449 ;
     RECT  216.923 2.151 218.16 73.449 ;
     RECT  218.16 3.348 218.327 18.684 ;
     RECT  218.16 19.548 218.867 23.274 ;
     RECT  218.16 24.174 218.867 26.244 ;
     RECT  218.327 5.58 218.903 18.684 ;
     RECT  218.867 19.656 218.903 23.274 ;
     RECT  218.903 5.58 218.939 9.954 ;
     RECT  218.903 10.836 218.939 18.684 ;
     RECT  218.939 7.596 218.975 8.424 ;
     RECT  218.939 5.58 219.191 6.642 ;
     RECT  218.939 15.426 219.335 18.684 ;
     RECT  219.335 15.426 219.371 18.594 ;
     RECT  218.903 19.89 219.407 23.274 ;
     RECT  218.939 9.216 219.443 9.846 ;
     RECT  218.939 10.836 219.443 11.394 ;
     RECT  218.939 12.186 219.443 14.634 ;
     RECT  219.371 15.426 219.443 18.054 ;
     RECT  218.867 24.174 219.443 25.974 ;
     RECT  219.443 10.836 219.479 11.304 ;
     RECT  218.327 3.348 219.551 4.752 ;
     RECT  219.191 5.58 219.551 6.138 ;
     RECT  218.975 7.596 219.551 8.226 ;
     RECT  219.551 4.086 219.587 4.752 ;
     RECT  219.551 8.208 219.587 8.226 ;
     RECT  219.587 4.086 219.623 4.374 ;
     RECT  219.551 5.58 219.623 6.102 ;
     RECT  219.623 5.58 219.659 5.598 ;
     RECT  219.623 4.356 219.695 4.374 ;
     RECT  219.443 15.534 220.055 17.244 ;
     RECT  219.443 18 220.091 18.054 ;
     RECT  220.091 18 220.127 18.018 ;
     RECT  219.407 19.89 220.127 22.374 ;
     RECT  219.443 14.184 220.163 14.634 ;
     RECT  220.055 15.534 220.163 16.668 ;
     RECT  220.127 19.926 220.163 22.374 ;
     RECT  219.443 25.146 220.163 25.974 ;
     RECT  219.479 10.836 220.199 11.232 ;
     RECT  220.163 14.454 220.199 14.634 ;
     RECT  220.163 15.606 220.199 16.479 ;
     RECT  220.163 20.016 220.199 22.374 ;
     RECT  220.163 25.146 220.199 25.704 ;
     RECT  219.443 9.828 220.235 9.846 ;
     RECT  220.199 10.836 220.235 10.854 ;
     RECT  219.443 12.33 220.235 12.654 ;
     RECT  220.199 14.454 220.235 14.472 ;
     RECT  220.199 15.876 220.235 16.479 ;
     RECT  220.199 20.016 220.235 20.178 ;
     RECT  220.199 21.24 220.235 21.762 ;
     RECT  220.199 25.146 220.235 25.164 ;
     RECT  218.16 2.232 220.271 2.592 ;
     RECT  220.271 2.232 220.307 2.25 ;
     RECT  220.207 5.274 220.307 5.292 ;
     RECT  220.235 16.461 220.307 16.479 ;
     RECT  220.235 20.16 220.307 20.178 ;
    LAYER M3 ;
     RECT  214.668 2.101 214.686 2.191 ;
     RECT  216.9 2.101 216.918 2.227 ;
     RECT  214.668 2.191 214.83 2.263 ;
     RECT  216.9 2.227 217.53 2.299 ;
     RECT  216.9 2.299 217.782 2.335 ;
     RECT  2.415 2.143 2.505 2.413 ;
     RECT  7.815 2.143 7.905 2.413 ;
     RECT  13.215 2.143 13.305 2.413 ;
     RECT  18.615 2.143 18.705 2.413 ;
     RECT  24.015 2.143 24.105 2.413 ;
     RECT  29.415 2.143 29.505 2.413 ;
     RECT  34.815 2.143 34.905 2.413 ;
     RECT  40.215 2.143 40.305 2.413 ;
     RECT  45.615 2.143 45.705 2.413 ;
     RECT  51.015 2.143 51.105 2.413 ;
     RECT  56.415 2.143 56.505 2.413 ;
     RECT  61.815 2.143 61.905 2.413 ;
     RECT  67.215 2.143 67.305 2.413 ;
     RECT  72.615 2.143 72.705 2.413 ;
     RECT  78.015 2.143 78.105 2.413 ;
     RECT  83.415 2.143 83.505 2.413 ;
     RECT  88.815 2.143 88.905 2.413 ;
     RECT  94.215 2.143 94.305 2.413 ;
     RECT  99.615 2.143 99.705 2.413 ;
     RECT  105.015 2.143 105.105 2.413 ;
     RECT  110.415 2.143 110.505 2.413 ;
     RECT  115.815 2.143 115.905 2.413 ;
     RECT  121.215 2.143 121.305 2.413 ;
     RECT  126.615 2.143 126.705 2.413 ;
     RECT  132.015 2.143 132.105 2.413 ;
     RECT  137.415 2.143 137.505 2.413 ;
     RECT  142.815 2.143 142.905 2.413 ;
     RECT  148.215 2.143 148.305 2.413 ;
     RECT  153.615 2.143 153.705 2.413 ;
     RECT  159.015 2.143 159.105 2.413 ;
     RECT  164.415 2.143 164.505 2.413 ;
     RECT  169.815 2.143 169.905 2.413 ;
     RECT  175.215 2.143 175.305 2.413 ;
     RECT  180.615 2.143 180.705 2.413 ;
     RECT  186.015 2.143 186.105 2.413 ;
     RECT  191.415 2.143 191.505 2.413 ;
     RECT  196.815 2.143 196.905 2.413 ;
     RECT  202.215 2.143 202.305 2.413 ;
     RECT  207.615 2.143 207.705 2.413 ;
     RECT  213.015 2.143 213.105 2.413 ;
     RECT  214.452 2.263 214.83 2.461 ;
     RECT  216.576 2.335 217.782 2.461 ;
     RECT  214.272 2.461 214.83 2.533 ;
     RECT  216.108 2.461 217.782 2.533 ;
     RECT  213.015 2.413 213.297 2.569 ;
     RECT  220.284 2.227 220.302 2.569 ;
     RECT  214.272 2.533 217.782 2.641 ;
     RECT  214.272 2.641 217.998 2.803 ;
     RECT  214.128 2.803 217.998 3.145 ;
     RECT  220.248 2.569 220.302 3.343 ;
     RECT  219.528 3.343 220.302 3.721 ;
     RECT  2.415 2.413 2.697 3.955 ;
     RECT  212.904 2.569 213.297 3.955 ;
     RECT  2.304 3.955 2.697 3.991 ;
     RECT  2.304 3.991 3.294 4.117 ;
     RECT  2.304 4.117 4.05 4.153 ;
     RECT  212.616 3.955 213.297 4.387 ;
     RECT  2.304 4.153 4.194 4.415 ;
     RECT  214.128 3.145 218.034 4.459 ;
     RECT  212.616 4.387 213.39 4.495 ;
     RECT  219.456 3.721 220.302 4.495 ;
     RECT  211.932 4.495 213.39 4.531 ;
     RECT  214.128 4.459 218.43 4.531 ;
     RECT  6.552 4.261 6.57 4.801 ;
     RECT  5.976 4.801 6.57 4.891 ;
     RECT  100.908 4.387 100.926 4.919 ;
     RECT  2.304 4.415 3.906 5.035 ;
     RECT  211.932 4.531 218.43 5.161 ;
     RECT  23.184 4.117 23.202 5.189 ;
     RECT  210.168 4.891 210.186 5.197 ;
     RECT  206.46 5.197 206.478 5.233 ;
     RECT  210.168 5.197 210.222 5.233 ;
     RECT  211.356 5.161 218.43 5.233 ;
     RECT  206.388 5.233 206.478 5.269 ;
     RECT  210.168 5.233 218.43 5.269 ;
     RECT  219.348 4.495 220.302 5.297 ;
     RECT  7.815 2.413 8.097 5.305 ;
     RECT  219.348 5.297 220.23 5.309 ;
     RECT  7.815 5.305 8.154 5.341 ;
     RECT  24.015 2.413 24.297 5.341 ;
     RECT  5.796 4.891 6.57 5.419 ;
     RECT  208.836 5.341 208.854 5.459 ;
     RECT  210.024 5.269 218.43 5.467 ;
     RECT  7.815 5.341 8.298 5.501 ;
     RECT  206.388 5.269 206.55 5.503 ;
     RECT  1.728 5.035 3.906 5.611 ;
     RECT  4.716 4.891 4.734 5.611 ;
     RECT  5.76 5.419 6.57 5.611 ;
     RECT  209.772 5.467 218.43 5.611 ;
     RECT  1.728 5.611 4.734 5.729 ;
     RECT  5.544 5.611 6.57 5.729 ;
     RECT  126.615 2.413 126.897 5.737 ;
     RECT  107.964 5.611 107.982 5.845 ;
     RECT  209.16 5.611 218.43 5.845 ;
     RECT  219.348 5.309 219.69 5.845 ;
     RECT  205.02 4.459 205.038 5.881 ;
     RECT  206.388 5.503 206.874 5.881 ;
     RECT  209.16 5.845 219.69 5.885 ;
     RECT  21.852 5.701 21.87 5.971 ;
     RECT  5.724 5.729 6.57 5.995 ;
     RECT  25.668 5.071 25.686 5.999 ;
     RECT  5.724 5.995 7.074 6.007 ;
     RECT  7.815 5.501 8.154 6.007 ;
     RECT  18.615 2.413 18.897 6.007 ;
     RECT  207.615 2.413 207.897 6.007 ;
     RECT  1.728 5.729 4.59 6.035 ;
     RECT  23.4 5.341 24.297 6.037 ;
     RECT  117.144 5.467 117.162 6.043 ;
     RECT  23.4 6.037 24.39 6.077 ;
     RECT  205.02 5.881 206.874 6.107 ;
     RECT  1.728 6.035 4.554 6.143 ;
     RECT  112.68 5.161 112.698 6.151 ;
     RECT  206.856 6.107 206.874 6.151 ;
     RECT  207.615 6.007 208.314 6.151 ;
     RECT  23.4 6.077 24.297 6.179 ;
     RECT  25.092 6.079 25.254 6.269 ;
     RECT  209.16 5.885 219.654 6.269 ;
     RECT  205.02 6.107 205.794 6.305 ;
     RECT  205.776 6.305 205.794 6.317 ;
     RECT  211.428 6.269 219.654 6.365 ;
     RECT  137.415 2.413 137.697 6.421 ;
     RECT  206.856 6.151 208.314 6.421 ;
     RECT  209.16 6.269 210.474 6.421 ;
     RECT  206.856 6.421 210.474 6.539 ;
     RECT  137.34 6.421 137.697 6.547 ;
     RECT  23.904 6.179 24.297 6.557 ;
     RECT  25.092 6.269 25.11 6.605 ;
     RECT  137.088 6.547 137.697 6.605 ;
     RECT  19.944 6.583 19.962 6.691 ;
     RECT  5.724 6.007 8.154 6.719 ;
     RECT  17.676 4.927 17.694 6.719 ;
     RECT  5.724 6.719 6.858 6.781 ;
     RECT  19.944 6.691 20.358 6.781 ;
     RECT  21.096 4.963 21.114 6.781 ;
     RECT  111.996 6.151 112.698 6.781 ;
     RECT  19.944 6.781 21.114 6.809 ;
     RECT  211.428 6.365 217.962 6.809 ;
     RECT  2.304 6.143 4.554 6.811 ;
     RECT  5.328 6.781 6.858 6.811 ;
     RECT  211.536 6.809 217.962 6.845 ;
     RECT  107.424 5.845 107.982 6.889 ;
     RECT  2.304 6.811 6.858 6.907 ;
     RECT  202.215 2.413 202.497 6.907 ;
     RECT  107.424 6.889 108.018 6.961 ;
     RECT  206.856 6.539 208.854 6.961 ;
     RECT  21.852 5.971 22.41 7.051 ;
     RECT  106.02 6.385 106.038 7.051 ;
     RECT  209.664 6.539 210.474 7.051 ;
     RECT  9.252 5.341 9.27 7.079 ;
     RECT  21.852 7.051 22.59 7.079 ;
     RECT  11.268 7.051 11.286 7.087 ;
     RECT  202.215 6.907 202.518 7.087 ;
     RECT  115.815 2.413 116.097 7.123 ;
     RECT  106.02 7.051 106.398 7.151 ;
     RECT  206.1 6.961 208.854 7.195 ;
     RECT  1.728 6.907 6.858 7.196 ;
     RECT  23.94 6.557 24.297 7.231 ;
     RECT  205.884 7.195 208.854 7.232 ;
     RECT  202.215 7.087 202.554 7.259 ;
     RECT  1.728 7.196 6.786 7.349 ;
     RECT  19.944 6.809 19.962 7.349 ;
     RECT  20.808 6.809 21.114 7.393 ;
     RECT  106.38 7.151 106.398 7.393 ;
     RECT  107.424 6.961 108.342 7.393 ;
     RECT  211.752 6.845 217.962 7.421 ;
     RECT  110.415 2.413 110.697 7.501 ;
     RECT  111.996 6.781 112.95 7.501 ;
     RECT  206.352 7.232 208.854 7.501 ;
     RECT  209.664 7.051 210.51 7.501 ;
     RECT  10.908 7.087 11.286 7.591 ;
     RECT  206.352 7.501 210.51 7.591 ;
     RECT  211.752 7.421 211.842 7.619 ;
     RECT  18.615 6.007 18.954 7.627 ;
     RECT  1.728 7.349 6.57 7.655 ;
     RECT  7.815 6.719 8.154 7.663 ;
     RECT  15.228 6.547 15.246 7.663 ;
     RECT  105.015 2.413 105.297 7.663 ;
     RECT  196.815 2.413 197.097 7.663 ;
     RECT  212.616 7.421 217.962 7.663 ;
     RECT  218.772 6.365 219.654 7.663 ;
     RECT  10.8 7.591 11.286 7.691 ;
     RECT  130.536 7.321 130.554 7.691 ;
     RECT  1.764 7.655 6.57 7.763 ;
     RECT  206.352 7.591 210.978 7.765 ;
     RECT  113.724 5.503 113.742 7.771 ;
     RECT  206.352 7.765 211.698 7.799 ;
     RECT  206.424 7.799 211.698 7.805 ;
     RECT  7.815 7.663 8.19 7.889 ;
     RECT  18.252 7.627 18.954 7.889 ;
     RECT  206.424 7.805 211.302 7.889 ;
     RECT  23.94 7.231 24.57 7.933 ;
     RECT  212.616 7.663 219.654 7.963 ;
     RECT  127.944 6.583 127.962 8.005 ;
     RECT  20.808 7.393 21.258 8.041 ;
     RECT  212.616 7.963 220.014 8.059 ;
     RECT  106.38 7.393 108.342 8.131 ;
     RECT  18.252 7.889 18.897 8.159 ;
     RECT  206.424 7.889 211.05 8.189 ;
     RECT  206.424 8.189 210.942 8.195 ;
     RECT  106.38 8.131 108.918 8.203 ;
     RECT  212.616 8.059 220.122 8.237 ;
     RECT  105.015 7.663 105.498 8.239 ;
     RECT  120.024 7.231 120.042 8.311 ;
     RECT  121.215 2.413 121.497 8.311 ;
     RECT  103.212 6.241 103.23 8.401 ;
     RECT  103.968 7.861 103.986 8.401 ;
     RECT  212.616 8.237 219.582 8.477 ;
     RECT  1.8 7.763 6.57 8.491 ;
     RECT  212.616 8.477 217.818 8.525 ;
     RECT  206.424 8.195 210.906 8.581 ;
     RECT  1.8 8.491 6.642 8.635 ;
     RECT  211.68 8.683 211.734 8.735 ;
     RECT  164.415 2.413 164.697 8.743 ;
     RECT  206.352 8.581 210.906 8.771 ;
     RECT  1.728 8.635 6.642 8.815 ;
     RECT  7.815 7.889 8.097 8.815 ;
     RECT  206.388 8.771 210.906 8.843 ;
     RECT  1.404 8.815 8.097 8.851 ;
     RECT  106.38 8.203 109.458 8.851 ;
     RECT  117.108 6.043 117.162 8.879 ;
     RECT  110.415 7.501 112.95 8.941 ;
     RECT  113.724 7.771 114.282 8.941 ;
     RECT  218.88 8.477 219.582 8.957 ;
     RECT  1.404 8.851 8.154 8.969 ;
     RECT  33.12 7.357 33.138 8.977 ;
     RECT  34.056 7.195 34.074 8.977 ;
     RECT  23.94 7.933 25.218 9.005 ;
     RECT  33.12 8.977 34.074 9.005 ;
     RECT  102.276 7.123 102.294 9.013 ;
     RECT  103.212 8.401 103.986 9.013 ;
     RECT  104.832 8.239 105.498 9.049 ;
     RECT  106.38 8.851 109.494 9.049 ;
     RECT  120.024 8.311 121.497 9.049 ;
     RECT  110.415 8.941 114.282 9.077 ;
     RECT  208.62 8.843 210.906 9.085 ;
     RECT  33.372 9.005 34.074 9.149 ;
     RECT  102.276 9.013 103.986 9.211 ;
     RECT  24.015 9.005 25.218 9.275 ;
     RECT  218.88 8.957 219.438 9.307 ;
     RECT  212.652 8.525 217.818 9.319 ;
     RECT  218.844 9.307 219.438 9.319 ;
     RECT  208.62 9.085 210.942 9.355 ;
     RECT  211.68 8.735 211.698 9.355 ;
     RECT  102.024 9.211 103.986 9.391 ;
     RECT  104.832 9.049 109.494 9.391 ;
     RECT  59.796 6.043 59.814 9.481 ;
     RECT  72.615 2.413 72.897 9.499 ;
     RECT  59.652 9.481 59.814 9.509 ;
     RECT  208.62 9.355 211.698 9.509 ;
     RECT  102.024 9.391 109.494 9.517 ;
     RECT  58.248 9.481 58.266 9.533 ;
     RECT  24.015 9.275 24.57 9.545 ;
     RECT  34.056 9.149 34.074 9.545 ;
     RECT  7.815 8.969 8.154 9.547 ;
     RECT  99.615 2.413 99.897 9.553 ;
     RECT  209.16 9.509 211.698 9.553 ;
     RECT  212.436 9.319 219.438 9.553 ;
     RECT  25.38 9.481 25.398 9.581 ;
     RECT  206.388 8.843 207.897 9.589 ;
     RECT  117.108 8.879 117.126 9.625 ;
     RECT  206.388 9.589 208.17 9.689 ;
     RECT  59.652 9.509 59.67 9.751 ;
     RECT  206.388 9.689 207.954 9.751 ;
     RECT  59.544 9.751 59.67 9.779 ;
     RECT  209.16 9.553 219.438 9.779 ;
     RECT  24.015 9.545 24.534 9.815 ;
     RECT  209.16 9.779 219.006 9.815 ;
     RECT  1.404 8.969 6.858 9.823 ;
     RECT  206.352 9.751 207.954 9.851 ;
     RECT  220.212 9.787 220.23 9.851 ;
     RECT  20.556 8.041 21.258 9.859 ;
     RECT  110.415 9.077 111.762 9.895 ;
     RECT  112.536 9.077 114.282 9.895 ;
     RECT  1.404 9.823 6.93 9.931 ;
     RECT  7.815 9.547 8.37 9.931 ;
     RECT  205.02 6.305 205.038 9.931 ;
     RECT  116.856 9.625 117.126 9.959 ;
     RECT  206.64 9.851 207.954 10.049 ;
     RECT  26.172 8.167 26.19 10.085 ;
     RECT  206.64 10.049 207.897 10.085 ;
     RECT  9.972 7.087 9.99 10.201 ;
     RECT  13.215 2.413 13.497 10.201 ;
     RECT  205.02 9.931 205.218 10.201 ;
     RECT  22.356 7.079 22.59 10.291 ;
     RECT  1.404 9.931 8.37 10.301 ;
     RECT  98.064 8.131 98.082 10.319 ;
     RECT  2.34 10.301 8.37 10.471 ;
     RECT  209.196 9.815 219.006 10.493 ;
     RECT  101.484 9.517 109.494 10.597 ;
     RECT  110.415 9.895 114.282 10.597 ;
     RECT  119.376 9.049 121.497 10.597 ;
     RECT  126.216 5.737 126.897 10.625 ;
     RECT  218.916 10.493 219.006 10.685 ;
     RECT  11.268 7.691 11.286 10.741 ;
     RECT  12.528 10.201 13.497 10.741 ;
     RECT  175.215 2.413 175.497 10.831 ;
     RECT  207.108 10.085 207.897 10.831 ;
     RECT  16.884 10.705 16.902 10.867 ;
     RECT  203.76 5.971 203.778 10.867 ;
     RECT  205.02 10.201 205.794 10.867 ;
     RECT  206.856 10.831 207.897 10.867 ;
     RECT  99.18 9.553 99.897 10.903 ;
     RECT  205.02 10.867 207.897 10.987 ;
     RECT  203.76 10.867 203.85 11.003 ;
     RECT  2.34 10.471 8.55 11.011 ;
     RECT  20.376 9.859 21.258 11.011 ;
     RECT  101.484 10.597 114.282 11.011 ;
     RECT  119.376 10.597 122.022 11.011 ;
     RECT  203.832 11.003 203.85 11.039 ;
     RECT  205.02 10.987 208.35 11.039 ;
     RECT  18.615 8.159 18.897 11.101 ;
     RECT  119.196 11.011 122.022 11.129 ;
     RECT  220.212 10.747 220.23 11.131 ;
     RECT  20.376 11.011 21.546 11.137 ;
     RECT  22.356 10.291 23.094 11.137 ;
     RECT  60.588 11.101 60.606 11.165 ;
     RECT  205.02 11.039 208.314 11.237 ;
     RECT  220.176 11.131 220.23 11.237 ;
     RECT  2.34 11.011 8.658 11.245 ;
     RECT  14.58 7.663 15.246 11.245 ;
     RECT  18.615 11.101 18.954 11.281 ;
     RECT  59.544 9.779 59.562 11.281 ;
     RECT  219.42 10.939 219.438 11.281 ;
     RECT  14.58 11.245 15.318 11.371 ;
     RECT  16.128 11.209 16.146 11.371 ;
     RECT  209.196 10.493 217.818 11.407 ;
     RECT  205.776 11.237 208.314 11.435 ;
     RECT  18.615 11.281 19.386 11.443 ;
     RECT  20.376 11.137 23.094 11.443 ;
     RECT  219.42 11.281 219.474 11.453 ;
     RECT  209.124 11.407 217.818 11.515 ;
     RECT  219.42 11.453 219.438 11.515 ;
     RECT  11.268 10.741 13.497 11.551 ;
     RECT  14.58 11.371 16.146 11.551 ;
     RECT  119.376 11.129 122.022 11.551 ;
     RECT  98.82 10.903 99.897 11.669 ;
     RECT  119.376 11.551 122.562 11.669 ;
     RECT  1.404 10.301 1.422 11.677 ;
     RECT  2.304 11.245 8.658 11.677 ;
     RECT  98.82 11.669 98.838 11.677 ;
     RECT  207.108 11.435 208.314 11.693 ;
     RECT  9.684 10.201 9.99 11.713 ;
     RECT  16.884 10.867 17.622 11.749 ;
     RECT  18.615 11.443 23.094 11.749 ;
     RECT  98.676 11.677 98.838 11.777 ;
     RECT  1.404 11.677 8.658 11.785 ;
     RECT  9.684 11.713 10.494 11.785 ;
     RECT  126.615 10.625 126.897 11.785 ;
     RECT  205.776 11.435 206.37 11.849 ;
     RECT  0.144 11.755 0.162 11.933 ;
     RECT  163.836 8.743 164.697 11.947 ;
     RECT  1.404 11.785 10.494 11.975 ;
     RECT  118.224 5.269 118.242 11.983 ;
     RECT  101.484 11.011 114.678 12.019 ;
     RECT  115.416 7.123 116.097 12.019 ;
     RECT  100.656 8.815 100.674 12.055 ;
     RECT  101.484 12.019 116.097 12.055 ;
     RECT  100.656 12.055 116.097 12.181 ;
     RECT  117.108 9.959 117.126 12.181 ;
     RECT  207.216 11.693 208.314 12.181 ;
     RECT  209.052 11.515 219.438 12.181 ;
     RECT  220.212 11.237 220.23 12.187 ;
     RECT  1.404 11.975 9.99 12.209 ;
     RECT  117.936 11.983 118.242 12.209 ;
     RECT  1.404 12.209 9.126 12.221 ;
     RECT  47.736 12.181 47.754 12.221 ;
     RECT  16.884 11.749 23.094 12.289 ;
     RECT  125.964 11.785 126.897 12.317 ;
     RECT  11.268 11.551 16.146 12.325 ;
     RECT  119.376 11.669 122.022 12.325 ;
     RECT  204.084 11.137 204.102 12.389 ;
     RECT  207.216 12.181 219.438 12.413 ;
     RECT  100.656 12.181 117.126 12.479 ;
     RECT  112.536 12.479 117.126 12.487 ;
     RECT  205.884 11.849 206.37 12.487 ;
     RECT  207.216 12.413 217.818 12.487 ;
     RECT  175.215 10.831 176.166 12.623 ;
     RECT  10.8 12.325 16.146 12.721 ;
     RECT  97.164 12.595 97.182 12.749 ;
     RECT  135.108 12.523 135.126 12.821 ;
     RECT  118.224 12.209 118.242 12.829 ;
     RECT  119.052 12.325 122.022 12.829 ;
     RECT  10.764 12.721 16.146 12.857 ;
     RECT  125.1 7.735 125.118 12.901 ;
     RECT  118.224 12.829 122.022 13.019 ;
     RECT  123.084 12.865 123.102 13.019 ;
     RECT  125.1 12.901 125.19 13.019 ;
     RECT  205.884 12.487 217.818 13.019 ;
     RECT  125.1 13.019 125.118 13.027 ;
     RECT  124.92 13.027 125.118 13.085 ;
     RECT  98.82 11.777 98.838 13.289 ;
     RECT  11.268 12.857 16.146 13.297 ;
     RECT  16.884 12.289 23.13 13.297 ;
     RECT  205.884 13.019 206.622 13.325 ;
     RECT  112.536 12.487 117.45 13.369 ;
     RECT  118.224 13.019 120.33 13.369 ;
     RECT  59.472 11.281 59.562 13.373 ;
     RECT  207.468 13.019 217.818 13.405 ;
     RECT  218.808 12.413 219.438 13.405 ;
     RECT  203.508 13.027 203.526 13.433 ;
     RECT  0.216 13.387 0.234 13.435 ;
     RECT  1.728 12.221 9.126 13.441 ;
     RECT  9.972 12.209 9.99 13.441 ;
     RECT  0.144 13.435 0.234 13.565 ;
     RECT  112.536 13.369 120.33 13.595 ;
     RECT  98.676 13.567 98.766 13.627 ;
     RECT  98.604 13.627 98.766 13.661 ;
     RECT  207.468 13.405 219.438 13.661 ;
     RECT  98.604 13.661 98.694 13.667 ;
     RECT  218.844 13.661 219.438 13.667 ;
     RECT  98.676 13.667 98.694 13.865 ;
     RECT  123.84 13.711 123.858 13.865 ;
     RECT  11.268 13.297 23.13 13.909 ;
     RECT  205.02 11.237 205.038 13.909 ;
     RECT  218.88 13.667 219.438 13.915 ;
     RECT  220.176 12.187 220.23 13.915 ;
     RECT  100.656 12.479 111.726 13.981 ;
     RECT  112.536 13.595 114.282 13.981 ;
     RECT  0.144 13.565 0.162 14.045 ;
     RECT  123.768 13.981 123.786 14.099 ;
     RECT  92.736 14.071 92.754 14.141 ;
     RECT  100.656 13.981 114.282 14.207 ;
     RECT  10.908 13.909 23.13 14.243 ;
     RECT  125.1 13.085 125.118 14.251 ;
     RECT  218.88 13.915 220.23 14.279 ;
     RECT  115.092 13.595 120.33 14.377 ;
     RECT  121.215 13.019 122.022 14.377 ;
     RECT  202.215 7.259 202.497 14.413 ;
     RECT  204.624 13.909 205.038 14.413 ;
     RECT  206.352 13.325 206.622 14.485 ;
     RECT  207.468 13.661 217.89 14.485 ;
     RECT  206.352 14.485 217.89 14.491 ;
     RECT  218.88 14.279 219.438 14.491 ;
     RECT  206.352 14.491 219.438 14.513 ;
     RECT  202.215 14.413 202.518 14.521 ;
     RECT  115.092 14.377 122.634 14.549 ;
     RECT  202.215 14.521 203.238 14.549 ;
     RECT  124.956 14.251 125.118 14.587 ;
     RECT  203.22 14.549 203.238 14.635 ;
     RECT  199.008 14.611 199.026 14.719 ;
     RECT  124.884 14.587 125.118 14.731 ;
     RECT  198.936 14.719 199.026 14.747 ;
     RECT  124.704 14.731 125.118 14.755 ;
     RECT  198.936 14.747 198.954 14.791 ;
     RECT  203.22 14.635 203.274 14.819 ;
     RECT  124.56 14.755 125.118 14.881 ;
     RECT  101.448 14.207 114.282 14.909 ;
     RECT  115.092 14.549 122.022 14.909 ;
     RECT  206.352 14.513 219.402 14.957 ;
     RECT  101.7 14.909 114.282 15.017 ;
     RECT  117.432 14.909 122.022 15.053 ;
     RECT  198.612 14.791 198.954 15.053 ;
     RECT  204.624 14.413 205.398 15.061 ;
     RECT  211.428 14.957 219.402 15.101 ;
     RECT  0.144 15.115 0.162 15.163 ;
     RECT  220.176 14.279 220.23 15.163 ;
     RECT  204.624 15.061 205.47 15.179 ;
     RECT  206.352 14.957 210.654 15.179 ;
     RECT  124.56 14.881 125.298 15.215 ;
     RECT  220.14 15.163 220.23 15.259 ;
     RECT  211.428 15.101 218.574 15.287 ;
     RECT  0.144 15.163 0.342 15.293 ;
     RECT  211.464 15.287 218.574 15.359 ;
     RECT  204.624 15.179 205.398 15.485 ;
     RECT  1.728 13.441 9.99 15.601 ;
     RECT  11.088 14.243 23.13 15.601 ;
     RECT  124.56 15.215 125.118 15.601 ;
     RECT  204.624 15.485 205.038 15.629 ;
     RECT  124.488 15.601 125.118 15.719 ;
     RECT  206.388 15.179 210.654 15.755 ;
     RECT  174.42 15.691 174.438 15.821 ;
     RECT  78.015 2.413 78.297 15.871 ;
     RECT  196.344 7.663 197.097 15.871 ;
     RECT  64.8 15.787 64.818 15.899 ;
     RECT  142.815 2.413 143.097 15.961 ;
     RECT  206.388 15.755 206.658 15.961 ;
     RECT  211.536 15.359 218.574 15.961 ;
     RECT  219.42 15.259 220.23 15.961 ;
     RECT  202.215 14.549 202.497 15.979 ;
     RECT  203.22 14.819 203.238 15.979 ;
     RECT  72.615 9.499 72.99 15.989 ;
     RECT  147.06 14.989 147.078 15.997 ;
     RECT  148.215 2.413 148.497 15.997 ;
     RECT  202.215 15.979 203.238 16.013 ;
     RECT  147.06 15.997 148.497 16.025 ;
     RECT  142.815 15.961 143.694 16.027 ;
     RECT  101.7 15.017 109.494 16.069 ;
     RECT  110.304 15.017 114.282 16.069 ;
     RECT  138.528 15.961 138.546 16.069 ;
     RECT  138.528 16.069 138.618 16.097 ;
     RECT  142.74 16.027 143.694 16.097 ;
     RECT  123.156 15.223 123.174 16.105 ;
     RECT  207.54 15.755 210.654 16.105 ;
     RECT  211.536 15.961 220.23 16.105 ;
     RECT  206.352 15.961 206.658 16.157 ;
     RECT  138.6 16.097 138.618 16.169 ;
     RECT  88.815 2.413 89.097 16.231 ;
     RECT  144.468 13.945 144.486 16.231 ;
     RECT  147.636 16.025 148.497 16.231 ;
     RECT  101.7 16.069 114.282 16.259 ;
     RECT  142.74 16.097 143.658 16.259 ;
     RECT  144.396 16.231 144.486 16.301 ;
     RECT  199.908 14.107 199.926 16.315 ;
     RECT  88.344 16.231 89.097 16.349 ;
     RECT  117.468 15.053 122.022 16.367 ;
     RECT  72.615 15.989 72.954 16.397 ;
     RECT  207.54 16.105 220.23 16.456 ;
     RECT  124.56 15.719 125.118 16.507 ;
     RECT  123.12 16.105 123.174 16.529 ;
     RECT  207.54 16.456 220.302 16.529 ;
     RECT  117.468 16.367 120.294 16.565 ;
     RECT  117.468 16.565 120.042 16.573 ;
     RECT  207.54 16.529 218.142 16.645 ;
     RECT  206.352 16.157 206.442 16.651 ;
     RECT  142.815 16.259 143.658 16.673 ;
     RECT  121.215 16.367 122.022 16.681 ;
     RECT  123.12 16.529 123.138 16.681 ;
     RECT  207.18 16.645 218.142 16.685 ;
     RECT  117.144 16.573 120.042 16.709 ;
     RECT  117.216 16.709 120.042 16.799 ;
     RECT  102.6 16.259 114.282 16.835 ;
     RECT  206.172 16.651 206.442 17.035 ;
     RECT  121.215 16.681 123.138 17.069 ;
     RECT  1.728 15.601 23.13 17.083 ;
     RECT  102.6 16.835 112.95 17.105 ;
     RECT  117.468 16.799 120.042 17.105 ;
     RECT  206.028 17.035 206.442 17.105 ;
     RECT  121.215 17.069 122.022 17.221 ;
     RECT  118.08 17.105 120.042 17.249 ;
     RECT  1.152 17.083 23.13 17.261 ;
     RECT  219.24 16.529 220.302 17.339 ;
     RECT  123.12 17.069 123.138 17.411 ;
     RECT  71.676 13.909 71.694 17.419 ;
     RECT  207.504 16.685 218.142 17.519 ;
     RECT  120.024 17.249 120.042 17.608 ;
     RECT  120.924 17.221 122.022 17.608 ;
     RECT  120.024 17.608 122.022 17.645 ;
     RECT  63.684 15.871 63.702 17.653 ;
     RECT  64.656 16.375 64.674 17.653 ;
     RECT  196.344 15.871 197.73 17.653 ;
     RECT  97.812 17.383 97.83 17.689 ;
     RECT  46.62 12.361 46.638 17.707 ;
     RECT  29.415 2.413 29.697 17.725 ;
     RECT  102.6 17.105 112.698 17.725 ;
     RECT  147.636 16.231 148.806 17.753 ;
     RECT  147.672 17.753 148.806 17.789 ;
     RECT  219.276 17.339 220.302 17.789 ;
     RECT  87.228 16.411 87.246 17.885 ;
     RECT  118.08 17.249 118.998 17.887 ;
     RECT  147.672 17.789 148.497 17.915 ;
     RECT  97.812 17.689 98.334 17.923 ;
     RECT  89.82 17.455 89.838 17.995 ;
     RECT  205.02 15.629 205.038 17.995 ;
     RECT  219.312 17.789 220.302 18.059 ;
     RECT  29.415 17.725 29.754 18.139 ;
     RECT  30.528 13.945 30.546 18.139 ;
     RECT  48.276 17.707 48.294 18.139 ;
     RECT  206.352 17.105 206.442 18.149 ;
     RECT  91.62 14.251 91.638 18.173 ;
     RECT  71.676 17.419 71.802 18.187 ;
     RECT  72.615 16.397 72.897 18.187 ;
     RECT  200.664 13.909 200.682 18.187 ;
     RECT  190.08 16.375 190.098 18.193 ;
     RECT  102.564 17.725 112.698 18.257 ;
     RECT  67.215 2.413 67.497 18.265 ;
     RECT  124.56 16.507 125.442 18.265 ;
     RECT  108.828 18.257 112.698 18.329 ;
     RECT  210.888 17.519 218.142 18.331 ;
     RECT  74.916 18.031 74.934 18.391 ;
     RECT  121.215 17.645 122.022 18.391 ;
     RECT  126.615 12.317 126.897 18.391 ;
     RECT  127.944 8.005 128.538 18.391 ;
     RECT  108.828 18.329 109.53 18.419 ;
     RECT  124.56 18.265 125.694 18.419 ;
     RECT  206.388 18.149 206.442 18.419 ;
     RECT  207.54 17.519 209.682 18.421 ;
     RECT  94.215 2.413 94.497 18.427 ;
     RECT  210.888 18.331 218.286 18.427 ;
     RECT  124.56 18.419 125.442 18.455 ;
     RECT  140.22 17.617 140.238 18.455 ;
     RECT  202.215 16.013 202.95 18.455 ;
     RECT  117.684 17.887 118.998 18.463 ;
     RECT  110.415 18.329 112.698 18.491 ;
     RECT  94.215 18.427 94.662 18.499 ;
     RECT  102.564 18.257 108.09 18.499 ;
     RECT  206.424 18.419 206.442 18.499 ;
     RECT  210.528 18.427 218.286 18.523 ;
     RECT  219.312 18.059 219.366 18.523 ;
     RECT  121.215 18.391 122.562 18.527 ;
     RECT  129.384 16.267 129.402 18.527 ;
     RECT  200.664 18.187 201.33 18.535 ;
     RECT  202.215 18.455 202.497 18.535 ;
     RECT  97.812 17.923 98.874 18.571 ;
     RECT  69.336 14.791 69.354 18.661 ;
     RECT  207.468 18.421 209.682 18.661 ;
     RECT  210.528 18.523 219.366 18.661 ;
     RECT  117.288 18.463 118.998 18.689 ;
     RECT  126.615 18.391 128.538 18.689 ;
     RECT  206.424 18.499 206.586 18.689 ;
     RECT  207.36 18.661 219.366 18.689 ;
     RECT  94.215 18.499 94.77 18.697 ;
     RECT  68.94 18.661 69.354 18.701 ;
     RECT  97.56 18.571 98.874 18.725 ;
     RECT  206.424 18.689 206.442 18.725 ;
     RECT  211.248 18.689 219.366 18.749 ;
     RECT  97.884 18.725 98.874 18.797 ;
     RECT  117.792 18.689 118.998 18.797 ;
     RECT  207.36 18.689 210.402 18.797 ;
     RECT  61.815 2.413 62.097 18.805 ;
     RECT  112.536 18.491 112.698 18.805 ;
     RECT  113.724 16.835 114.282 18.805 ;
     RECT  120.024 17.645 120.042 18.805 ;
     RECT  63.684 17.653 64.674 18.811 ;
     RECT  65.736 18.193 65.754 18.811 ;
     RECT  66.708 18.265 67.95 18.811 ;
     RECT  112.536 18.805 114.282 18.833 ;
     RECT  163.26 11.947 164.697 18.833 ;
     RECT  220.14 18.059 220.302 18.907 ;
     RECT  66.708 18.811 68.526 18.931 ;
     RECT  74.916 18.391 75.582 18.931 ;
     RECT  76.32 15.331 76.338 18.931 ;
     RECT  34.815 2.413 35.097 18.955 ;
     RECT  203.796 17.923 203.814 18.955 ;
     RECT  71.676 18.187 72.897 18.959 ;
     RECT  108.828 18.419 109.494 18.959 ;
     RECT  114.264 18.833 114.282 18.959 ;
     RECT  24.015 9.815 24.297 18.967 ;
     RECT  94.215 18.697 94.806 18.967 ;
     RECT  95.796 17.959 95.814 18.967 ;
     RECT  101.7 16.259 101.718 18.967 ;
     RECT  102.528 18.499 108.09 18.967 ;
     RECT  207.36 18.797 210.366 18.995 ;
     RECT  29.415 18.139 30.546 19.003 ;
     RECT  212.436 18.749 219.366 19.003 ;
     RECT  220.104 18.907 220.302 19.003 ;
     RECT  101.7 18.967 108.09 19.039 ;
     RECT  108.828 18.959 109.17 19.039 ;
     RECT  184.644 18.667 184.662 19.039 ;
     RECT  99.615 11.669 99.897 19.075 ;
     RECT  100.656 14.207 100.674 19.075 ;
     RECT  24.015 18.967 24.498 19.111 ;
     RECT  207.615 18.995 210.366 19.139 ;
     RECT  29.415 19.003 30.726 19.147 ;
     RECT  38.808 18.811 38.826 19.147 ;
     RECT  40.215 2.413 40.497 19.147 ;
     RECT  45.615 2.413 45.897 19.147 ;
     RECT  46.62 17.707 47.07 19.147 ;
     RECT  51.015 2.413 51.297 19.147 ;
     RECT  56.415 2.413 56.697 19.147 ;
     RECT  72.54 18.959 72.897 19.195 ;
     RECT  1.728 17.261 23.13 19.201 ;
     RECT  27.828 18.841 27.846 19.201 ;
     RECT  71.676 18.959 71.802 19.201 ;
     RECT  74.916 18.931 76.986 19.201 ;
     RECT  195.768 17.653 197.73 19.201 ;
     RECT  198.612 15.053 198.63 19.201 ;
     RECT  99.615 19.075 100.674 19.229 ;
     RECT  212.436 19.003 220.302 19.229 ;
     RECT  195.768 19.201 198.63 19.237 ;
     RECT  27.828 19.201 28.098 19.265 ;
     RECT  38.772 19.147 38.826 19.265 ;
     RECT  209.664 19.139 210.366 19.265 ;
     RECT  190.08 18.193 190.674 19.273 ;
     RECT  191.415 2.413 191.697 19.273 ;
     RECT  0.144 19.099 0.162 19.277 ;
     RECT  45.615 19.147 47.07 19.277 ;
     RECT  56.415 19.147 56.862 19.277 ;
     RECT  58.716 19.147 58.734 19.277 ;
     RECT  66.528 18.931 68.526 19.277 ;
     RECT  124.56 18.455 125.298 19.291 ;
     RECT  205.02 17.995 205.47 19.309 ;
     RECT  24.015 19.111 24.714 19.337 ;
     RECT  212.868 19.229 220.302 19.337 ;
     RECT  34.815 18.955 35.37 19.345 ;
     RECT  69.336 18.701 69.354 19.345 ;
     RECT  24.015 19.337 24.642 19.373 ;
     RECT  99.615 19.229 100.53 19.373 ;
     RECT  101.7 19.039 109.17 19.373 ;
     RECT  66.528 19.277 68.418 19.381 ;
     RECT  121.215 18.527 122.022 19.381 ;
     RECT  193.824 17.383 193.842 19.409 ;
     RECT  34.704 19.345 35.37 19.435 ;
     RECT  1.728 19.201 23.166 19.471 ;
     RECT  24.015 19.373 24.606 19.471 ;
     RECT  29.415 19.147 30.798 19.471 ;
     RECT  31.932 19.003 31.95 19.471 ;
     RECT  37.8 17.923 37.818 19.471 ;
     RECT  61.815 18.805 62.73 19.471 ;
     RECT  63.684 18.811 65.754 19.471 ;
     RECT  71.388 19.201 71.802 19.471 ;
     RECT  74.412 19.201 76.986 19.471 ;
     RECT  78.015 15.871 78.498 19.471 ;
     RECT  121.215 19.381 122.454 19.471 ;
     RECT  126.615 18.689 126.99 19.471 ;
     RECT  127.944 18.689 128.538 19.471 ;
     RECT  190.08 19.273 191.697 19.471 ;
     RECT  194.616 15.331 194.634 19.471 ;
     RECT  29.415 19.471 30.906 19.483 ;
     RECT  199.728 16.315 199.926 19.483 ;
     RECT  104.832 19.373 109.17 19.499 ;
     RECT  112.536 18.833 113.31 19.499 ;
     RECT  121.215 19.471 122.526 19.499 ;
     RECT  34.704 19.435 35.406 19.507 ;
     RECT  31.788 19.471 31.986 19.517 ;
     RECT  37.8 19.471 37.962 19.531 ;
     RECT  38.772 19.265 38.79 19.531 ;
     RECT  189.9 19.471 192.33 19.531 ;
     RECT  118.08 18.797 118.998 19.535 ;
     RECT  119.952 18.805 120.042 19.535 ;
     RECT  212.868 19.337 213.297 19.535 ;
     RECT  26.784 19.147 26.802 19.543 ;
     RECT  51.015 19.147 51.462 19.543 ;
     RECT  59.472 13.373 59.49 19.543 ;
     RECT  78.015 19.471 78.642 19.543 ;
     RECT  83.415 2.413 83.697 19.543 ;
     RECT  110.415 18.491 111.618 19.543 ;
     RECT  126.615 19.471 128.61 19.543 ;
     RECT  195.408 19.237 198.63 19.543 ;
     RECT  199.584 19.483 199.926 19.543 ;
     RECT  42.768 19.147 42.786 19.565 ;
     RECT  84.924 18.535 84.942 19.571 ;
     RECT  101.7 19.373 104.058 19.571 ;
     RECT  104.832 19.499 107.118 19.571 ;
     RECT  124.56 19.291 125.442 19.571 ;
     RECT  31.896 19.517 31.986 19.579 ;
     RECT  40.215 19.147 40.662 19.579 ;
     RECT  70.848 19.471 71.802 19.579 ;
     RECT  88.815 16.349 89.097 19.579 ;
     RECT  89.82 17.995 90.486 19.579 ;
     RECT  29.088 19.483 30.906 19.613 ;
     RECT  31.896 19.579 32.022 19.613 ;
     RECT  74.232 19.471 76.986 19.615 ;
     RECT  110.415 19.543 111.726 19.615 ;
     RECT  112.536 19.499 113.13 19.615 ;
     RECT  115.092 14.909 116.097 19.615 ;
     RECT  118.08 19.535 118.494 19.615 ;
     RECT  163.26 18.833 163.278 19.615 ;
     RECT  164.415 18.833 164.697 19.615 ;
     RECT  119.7 19.579 119.718 19.643 ;
     RECT  27.9 19.265 28.098 19.651 ;
     RECT  53.244 19.543 53.262 19.651 ;
     RECT  72.54 19.195 72.99 19.651 ;
     RECT  74.16 19.615 76.986 19.651 ;
     RECT  78.015 19.543 79.398 19.651 ;
     RECT  82.728 19.543 83.697 19.651 ;
     RECT  117.972 19.615 118.494 19.661 ;
     RECT  34.668 19.507 35.406 19.679 ;
     RECT  53.172 19.651 53.262 19.679 ;
     RECT  171.576 19.075 171.594 19.679 ;
     RECT  214.488 19.337 220.302 19.679 ;
     RECT  31.932 19.613 32.022 19.723 ;
     RECT  37.8 19.531 38.79 19.723 ;
     RECT  73.836 19.651 79.398 19.741 ;
     RECT  114.012 19.615 114.03 19.741 ;
     RECT  114.912 19.615 116.097 19.741 ;
     RECT  50.724 19.543 51.462 19.768 ;
     RECT  72.54 19.651 73.062 19.768 ;
     RECT  50.724 19.768 51.894 19.769 ;
     RECT  53.172 19.679 53.19 19.769 ;
     RECT  66.492 19.381 68.418 19.769 ;
     RECT  69.336 19.345 69.57 19.769 ;
     RECT  93.06 19.675 93.078 19.769 ;
     RECT  105.015 19.571 107.118 19.769 ;
     RECT  108.036 19.499 109.17 19.769 ;
     RECT  112.5 19.615 113.13 19.769 ;
     RECT  114.012 19.741 116.097 19.769 ;
     RECT  122.508 19.499 122.526 19.769 ;
     RECT  126.615 19.543 128.682 19.769 ;
     RECT  163.26 19.615 164.697 19.769 ;
     RECT  195.408 19.543 199.926 19.769 ;
     RECT  70.776 19.579 71.802 19.771 ;
     RECT  72.54 19.768 73.098 19.771 ;
     RECT  200.664 18.535 202.497 19.771 ;
     RECT  70.776 19.771 73.098 19.777 ;
     RECT  86.652 19.579 86.67 19.777 ;
     RECT  126.615 19.769 127.962 19.777 ;
     RECT  27.9 19.651 28.17 19.805 ;
     RECT  58.788 19.543 59.49 19.805 ;
     RECT  124.56 19.571 125.046 19.805 ;
     RECT  37.584 19.723 38.79 19.813 ;
     RECT  40.215 19.579 40.734 19.813 ;
     RECT  157.608 12.187 157.626 19.813 ;
     RECT  195.696 19.769 199.926 19.813 ;
     RECT  200.664 19.771 202.95 19.813 ;
     RECT  29.34 19.613 30.906 19.841 ;
     RECT  37.512 19.813 38.79 19.841 ;
     RECT  214.488 19.679 218.286 19.841 ;
     RECT  30.78 19.841 30.906 19.849 ;
     RECT  26.784 19.543 26.946 19.853 ;
     RECT  31.932 19.723 32.13 19.853 ;
     RECT  69.408 19.769 69.57 19.853 ;
     RECT  26.856 19.853 26.946 19.877 ;
     RECT  86.652 19.777 86.778 19.877 ;
     RECT  110.376 19.615 111.726 19.877 ;
     RECT  122.58 19.777 122.598 19.877 ;
     RECT  126.612 19.777 127.962 19.877 ;
     RECT  189.684 19.531 192.33 19.877 ;
     RECT  46.62 19.277 47.07 19.901 ;
     RECT  50.184 19.813 50.202 19.901 ;
     RECT  26.856 19.877 26.874 19.913 ;
     RECT  29.34 19.841 29.934 19.913 ;
     RECT  31.932 19.853 32.058 19.913 ;
     RECT  37.512 19.841 37.53 19.913 ;
     RECT  61.815 19.471 65.754 19.921 ;
     RECT  66.492 19.769 68.382 19.921 ;
     RECT  40.215 19.813 41.382 19.949 ;
     RECT  70.704 19.777 73.098 19.949 ;
     RECT  73.836 19.741 79.794 19.949 ;
     RECT  219.384 19.679 220.302 19.949 ;
     RECT  34.815 19.679 35.406 19.997 ;
     RECT  51.015 19.769 51.894 19.997 ;
     RECT  61.815 19.921 68.382 19.997 ;
     RECT  82.656 19.651 83.862 19.997 ;
     RECT  88.815 19.579 90.486 19.997 ;
     RECT  94.215 18.967 95.814 19.997 ;
     RECT  105.015 19.769 105.426 19.997 ;
     RECT  115.815 19.769 116.097 19.997 ;
     RECT  121.215 19.499 121.77 19.997 ;
     RECT  126.615 19.877 127.71 19.997 ;
     RECT  132.015 2.413 132.297 19.997 ;
     RECT  137.415 6.605 137.697 19.997 ;
     RECT  142.815 16.673 143.097 19.997 ;
     RECT  148.215 17.915 148.497 19.997 ;
     RECT  153.615 2.413 153.897 19.997 ;
     RECT  159.015 2.413 159.297 19.997 ;
     RECT  164.415 19.769 164.697 19.997 ;
     RECT  169.815 2.413 170.097 19.997 ;
     RECT  175.215 12.623 175.497 19.997 ;
     RECT  180.615 2.413 180.897 19.997 ;
     RECT  186.015 2.413 186.297 19.997 ;
     RECT  189.684 19.877 191.934 19.997 ;
     RECT  40.215 19.949 40.497 20.011 ;
     RECT  45.615 19.277 45.897 20.011 ;
     RECT  56.415 19.277 56.697 20.011 ;
     RECT  94.407 19.997 95.814 20.011 ;
     RECT  177.804 15.787 177.822 20.011 ;
     RECT  186.207 19.997 186.297 20.011 ;
     RECT  188.82 17.419 188.838 20.011 ;
     RECT  189.684 19.997 190.746 20.011 ;
     RECT  209.664 19.265 210.006 20.011 ;
     RECT  1.728 19.471 24.606 20.039 ;
     RECT  29.34 19.913 29.79 20.039 ;
     RECT  30.78 19.849 30.942 20.039 ;
     RECT  48.276 18.139 48.798 20.039 ;
     RECT  70.74 19.949 73.098 20.039 ;
     RECT  89.007 19.997 90.486 20.039 ;
     RECT  106.668 19.769 107.118 20.039 ;
     RECT  144.468 16.301 144.486 20.039 ;
     RECT  163.26 19.769 163.278 20.039 ;
     RECT  177.804 20.011 178.002 20.039 ;
     RECT  184.644 19.039 185.274 20.039 ;
     RECT  38.772 19.841 38.79 20.047 ;
     RECT  46.8 19.901 47.07 20.047 ;
     RECT  55.872 20.011 56.697 20.047 ;
     RECT  59.436 19.805 59.49 20.047 ;
     RECT  72.54 20.039 73.098 20.047 ;
     RECT  73.836 19.949 78.297 20.047 ;
     RECT  98.316 18.797 98.874 20.047 ;
     RECT  99.615 19.373 100.35 20.047 ;
     RECT  39.924 20.011 40.497 20.048 ;
     RECT  42.156 20.011 42.174 20.048 ;
     RECT  45.504 20.011 45.897 20.048 ;
     RECT  55.872 20.047 57.042 20.075 ;
     RECT  79.092 19.949 79.794 20.083 ;
     RECT  184.68 20.039 185.274 20.083 ;
     RECT  188.46 20.011 188.838 20.083 ;
     RECT  189.612 20.011 190.746 20.083 ;
     RECT  59.436 20.047 59.526 20.093 ;
     RECT  35.007 19.997 35.406 20.107 ;
     RECT  83.607 19.997 83.862 20.107 ;
     RECT  86.652 19.877 86.706 20.107 ;
     RECT  188.46 20.083 190.746 20.111 ;
     RECT  25.92 11.947 25.938 20.119 ;
     RECT  98.316 20.047 100.35 20.119 ;
     RECT  159.207 19.997 159.297 20.119 ;
     RECT  25.92 20.119 26.01 20.147 ;
     RECT  38.772 20.047 38.862 20.147 ;
     RECT  87.768 19.867 87.786 20.147 ;
     RECT  94.407 20.011 96.246 20.147 ;
     RECT  146.34 20.011 146.358 20.147 ;
     RECT  204.624 19.309 205.47 20.147 ;
     RECT  79.092 20.083 79.902 20.149 ;
     RECT  48.276 20.039 48.654 20.155 ;
     RECT  86.148 20.107 86.706 20.155 ;
     RECT  186.207 20.011 186.57 20.155 ;
     RECT  194.328 19.471 194.634 20.155 ;
     RECT  203.76 18.955 203.814 20.155 ;
     RECT  61.92 19.997 68.382 20.183 ;
     RECT  177.984 20.039 178.002 20.183 ;
     RECT  191.607 19.997 191.934 20.183 ;
     RECT  220.176 19.949 220.302 20.183 ;
     RECT  79.092 20.149 80.622 20.189 ;
     RECT  25.992 20.147 26.01 20.191 ;
     RECT  46.8 20.047 47.142 20.191 ;
     RECT  54.72 19.147 54.738 20.191 ;
     RECT  59.508 20.093 59.526 20.191 ;
     RECT  82.656 19.997 82.746 20.191 ;
     RECT  83.607 20.107 83.97 20.191 ;
     RECT  85.896 20.155 86.706 20.191 ;
     RECT  157.608 19.813 157.914 20.191 ;
     RECT  194.328 20.155 194.706 20.191 ;
     RECT  48.132 20.155 48.654 20.192 ;
     RECT  156.744 20.191 157.914 20.219 ;
     RECT  189.072 20.111 190.674 20.219 ;
     RECT  56.607 20.075 57.042 20.237 ;
     RECT  61.92 20.183 63.918 20.237 ;
     RECT  0.18 20.107 0.198 20.251 ;
     RECT  29.34 20.039 29.697 20.267 ;
     RECT  35.007 20.107 35.442 20.267 ;
     RECT  40.356 20.048 40.497 20.267 ;
     RECT  45.807 20.048 45.897 20.267 ;
     RECT  51.207 19.997 51.894 20.267 ;
     RECT  56.607 20.237 56.697 20.267 ;
     RECT  62.007 20.237 63.918 20.267 ;
     RECT  72.54 20.047 78.297 20.267 ;
     RECT  83.607 20.191 84.222 20.267 ;
     RECT  89.007 20.039 90.414 20.267 ;
     RECT  94.407 20.147 94.77 20.267 ;
     RECT  97.92 20.119 100.35 20.267 ;
     RECT  105.207 19.997 105.426 20.267 ;
     RECT  110.376 19.877 110.697 20.267 ;
     RECT  116.007 19.997 116.097 20.267 ;
     RECT  121.407 19.997 121.77 20.267 ;
     RECT  126.807 19.997 127.71 20.267 ;
     RECT  132.207 19.997 132.297 20.267 ;
     RECT  137.607 19.997 137.697 20.267 ;
     RECT  143.007 19.997 143.097 20.267 ;
     RECT  148.407 19.997 148.497 20.267 ;
     RECT  153.807 19.997 153.897 20.267 ;
     RECT  159.207 20.119 159.642 20.267 ;
     RECT  164.607 19.997 164.697 20.267 ;
     RECT  170.007 19.997 170.097 20.267 ;
     RECT  175.407 19.997 175.497 20.267 ;
     RECT  180.807 19.997 180.897 20.267 ;
     RECT  186.207 20.155 186.606 20.267 ;
     RECT  191.607 20.183 191.862 20.267 ;
     RECT  59.508 20.191 59.706 20.281 ;
     RECT  60.444 19.651 60.462 20.281 ;
     RECT  48.132 20.192 48.618 20.309 ;
     RECT  54.72 20.191 54.81 20.309 ;
     RECT  58.284 20.155 58.626 20.309 ;
     RECT  70.74 20.039 71.766 20.309 ;
     RECT  79.092 20.189 79.902 20.309 ;
     RECT  80.856 20.191 80.874 20.309 ;
     RECT  135.108 19.237 135.126 20.309 ;
     RECT  156.744 20.219 157.806 20.309 ;
     RECT  189.072 20.219 190.458 20.309 ;
     RECT  205.38 20.147 205.47 20.309 ;
     RECT  209.664 20.011 210.366 20.309 ;
     RECT  219.384 19.949 219.438 20.309 ;
     RECT  108.036 19.769 108.846 20.317 ;
     RECT  195.696 19.813 202.95 20.333 ;
     RECT  25.992 20.191 26.082 20.345 ;
     RECT  38.772 20.147 38.79 20.345 ;
     RECT  42.048 20.119 42.066 20.345 ;
     RECT  64.98 20.183 68.382 20.345 ;
     RECT  79.092 20.309 79.83 20.345 ;
     RECT  82.08 20.191 82.746 20.345 ;
     RECT  85.824 20.191 86.706 20.345 ;
     RECT  97.92 20.267 99.306 20.345 ;
     RECT  102.42 19.571 104.058 20.345 ;
     RECT  156.744 20.309 157.554 20.345 ;
     RECT  195.696 20.333 195.714 20.345 ;
     RECT  0.18 20.251 0.306 20.381 ;
     RECT  29.34 20.267 29.502 20.381 ;
     RECT  46.8 20.191 47.286 20.381 ;
     RECT  48.6 20.309 48.618 20.381 ;
     RECT  54.792 20.309 54.81 20.381 ;
     RECT  59.508 20.281 60.462 20.381 ;
     RECT  68.148 20.345 68.382 20.381 ;
     RECT  70.776 20.309 71.766 20.381 ;
     RECT  79.164 20.345 79.83 20.381 ;
     RECT  94.608 20.267 94.77 20.381 ;
     RECT  97.92 20.345 99.234 20.381 ;
     RECT  118.476 19.661 118.494 20.381 ;
     RECT  156.744 20.345 157.338 20.381 ;
     RECT  173.988 20.011 174.006 20.381 ;
     RECT  191.844 20.267 191.862 20.381 ;
     RECT  29.34 20.381 29.358 20.417 ;
     RECT  62.568 20.267 63.918 20.417 ;
     RECT  186.408 20.267 186.606 20.417 ;
     RECT  107.748 20.317 108.846 20.429 ;
     RECT  94.608 20.381 94.662 20.453 ;
     RECT  184.68 20.083 185.31 20.453 ;
     RECT  27.612 20.191 27.63 20.489 ;
     RECT  82.08 20.345 82.674 20.489 ;
     RECT  89.352 20.267 90.414 20.489 ;
     RECT  95.724 20.147 96.246 20.489 ;
     RECT  219.384 20.309 219.402 20.489 ;
     RECT  94.608 20.453 94.626 20.525 ;
     RECT  203.76 20.155 204.498 20.525 ;
     RECT  95.724 20.489 95.742 20.534 ;
     RECT  98.568 20.381 99.234 20.534 ;
     RECT  186.408 20.417 186.426 20.534 ;
     RECT  189.252 20.309 190.458 20.534 ;
     RECT  193.788 20.191 194.706 20.534 ;
     RECT  35.424 20.267 35.442 20.573 ;
     RECT  68.184 20.381 68.382 20.651 ;
     RECT  89.352 20.489 90.054 20.651 ;
     RECT  220.176 20.183 220.194 20.651 ;
     RECT  62.568 20.417 63.234 20.669 ;
     RECT  72.54 20.267 77.742 20.717 ;
     RECT  72.936 20.717 77.742 20.759 ;
     RECT  51.876 20.267 51.894 20.765 ;
     RECT  59.688 20.381 60.462 20.804 ;
     RECT  40.356 20.267 40.374 20.813 ;
     RECT  63.144 20.669 63.234 20.849 ;
     RECT  58.284 20.309 58.554 20.861 ;
     RECT  69.552 19.853 69.57 20.885 ;
     RECT  72.936 20.759 77.526 20.885 ;
     RECT  127.26 20.267 127.71 20.909 ;
     RECT  189.252 20.534 189.306 20.909 ;
     RECT  58.284 20.861 58.302 20.921 ;
     RECT  71.136 20.381 71.766 20.921 ;
     RECT  105.408 20.267 105.426 20.957 ;
     RECT  193.788 20.534 193.842 20.957 ;
     RECT  211.248 18.749 211.662 20.965 ;
     RECT  73.548 20.885 77.526 20.993 ;
     RECT  213.015 19.535 213.297 21.001 ;
     RECT  214.488 19.841 218.142 21.001 ;
     RECT  111.6 19.877 111.726 21.005 ;
     RECT  73.548 20.993 75.582 21.029 ;
     RECT  76.536 20.993 77.526 21.029 ;
     RECT  112.5 19.769 112.518 21.053 ;
     RECT  184.68 20.453 185.274 21.074 ;
     RECT  63.144 20.849 63.162 21.101 ;
     RECT  211.248 20.965 211.95 21.115 ;
     RECT  213.015 21.001 213.462 21.115 ;
     RECT  83.772 20.267 84.222 21.119 ;
     RECT  193.788 20.957 193.806 21.119 ;
     RECT  205.452 20.309 205.47 21.119 ;
     RECT  211.176 21.115 213.462 21.119 ;
     RECT  207.615 19.139 208.926 21.127 ;
     RECT  209.664 20.309 210.006 21.127 ;
     RECT  211.176 21.119 211.194 21.127 ;
     RECT  196.596 20.333 202.95 21.149 ;
     RECT  211.932 21.119 213.462 21.149 ;
     RECT  89.352 20.651 89.91 21.155 ;
     RECT  207.615 21.127 211.194 21.155 ;
     RECT  206.352 20.491 206.37 21.163 ;
     RECT  206.352 21.163 206.406 21.235 ;
     RECT  85.824 20.345 85.914 21.245 ;
     RECT  214.488 21.001 218.322 21.245 ;
     RECT  85.824 21.245 85.842 21.263 ;
     RECT  212.04 21.149 213.462 21.271 ;
     RECT  214.488 21.245 217.782 21.271 ;
     RECT  110.376 20.267 110.394 21.293 ;
     RECT  64.98 20.345 67.194 21.299 ;
     RECT  98.676 20.534 99.234 21.299 ;
     RECT  36.468 19.885 36.486 21.307 ;
     RECT  1.728 20.039 24.57 21.316 ;
     RECT  65.376 21.299 67.194 21.389 ;
     RECT  74.16 21.029 75.582 21.389 ;
     RECT  206.352 21.235 206.55 21.389 ;
     RECT  207.615 21.155 211.014 21.389 ;
     RECT  75.42 21.389 75.582 21.425 ;
     RECT  79.74 20.381 79.83 21.437 ;
     RECT  1.728 21.316 25.074 21.461 ;
     RECT  91.188 20.191 91.206 21.461 ;
     RECT  93.276 19.885 93.294 21.461 ;
     RECT  207.615 21.389 208.314 21.469 ;
     RECT  111.6 21.005 111.618 21.485 ;
     RECT  156.744 20.381 156.762 21.485 ;
     RECT  102.42 20.345 103.194 21.497 ;
     RECT  189.288 20.909 189.306 21.497 ;
     RECT  34.776 21.307 34.794 21.499 ;
     RECT  36.468 21.307 36.81 21.499 ;
     RECT  35.928 21.499 36.81 21.533 ;
     RECT  102.42 21.497 102.978 21.533 ;
     RECT  107.748 20.429 108.306 21.533 ;
     RECT  159.624 20.267 159.642 21.533 ;
     RECT  192.672 20.155 192.69 21.533 ;
     RECT  98.676 21.299 98.694 21.569 ;
     RECT  107.748 21.533 107.766 21.569 ;
     RECT  209.448 21.389 211.014 21.569 ;
     RECT  218.844 21.403 218.862 21.569 ;
     RECT  104.04 20.345 104.058 21.581 ;
     RECT  190.404 20.534 190.422 21.581 ;
     RECT  1.728 21.461 25.002 21.614 ;
     RECT  65.376 21.389 66.618 21.614 ;
     RECT  0.144 21.451 0.162 21.629 ;
     RECT  34.776 21.499 34.902 21.629 ;
     RECT  36.684 21.533 36.81 21.629 ;
     RECT  145.908 20.353 145.926 21.629 ;
     RECT  218.88 21.595 218.898 21.631 ;
     RECT  74.16 21.389 74.25 21.677 ;
     RECT  47.268 20.381 47.286 21.695 ;
     RECT  89.46 21.155 89.91 21.695 ;
     RECT  35.928 21.533 35.946 21.725 ;
     RECT  220.212 21.115 220.23 21.767 ;
     RECT  218.88 21.631 218.934 21.883 ;
     RECT  212.04 21.271 217.782 21.929 ;
     RECT  218.88 21.883 219.438 21.929 ;
     RECT  209.448 21.569 210.942 21.965 ;
     RECT  214.236 21.929 217.782 21.965 ;
     RECT  206.352 21.389 206.37 21.979 ;
     RECT  214.416 21.965 217.782 22.045 ;
     RECT  212.04 21.929 213.426 22.073 ;
     RECT  214.416 22.045 217.818 22.109 ;
     RECT  214.668 22.109 217.818 22.199 ;
     RECT  214.992 22.199 217.782 22.235 ;
     RECT  220.176 21.787 220.194 22.379 ;
     RECT  1.728 21.614 24.894 22.464 ;
     RECT  53.1 19.921 53.118 22.464 ;
     RECT  59.832 20.804 60.462 22.464 ;
     RECT  65.376 21.614 66.114 22.464 ;
     RECT  68.184 20.651 68.202 22.464 ;
     RECT  71.748 20.921 71.766 22.464 ;
     RECT  74.16 21.677 74.178 22.464 ;
     RECT  75.564 21.425 75.582 22.464 ;
     RECT  76.536 21.029 77.022 22.464 ;
     RECT  79.74 21.437 79.758 22.464 ;
     RECT  82.08 20.489 82.098 22.464 ;
     RECT  83.772 21.119 83.79 22.464 ;
     RECT  89.46 21.695 89.478 22.464 ;
     RECT  100.332 20.267 100.35 22.464 ;
     RECT  102.96 21.533 102.978 22.464 ;
     RECT  106.668 20.039 107.01 22.464 ;
     RECT  114.012 19.769 114.498 22.464 ;
     RECT  121.752 20.267 121.77 22.464 ;
     RECT  125.028 19.805 125.046 22.464 ;
     RECT  127.692 20.909 127.71 22.464 ;
     RECT  130.896 19.579 130.914 22.464 ;
     RECT  176.148 20.317 176.166 22.464 ;
     RECT  185.256 21.074 185.274 22.464 ;
     RECT  194.688 20.534 194.706 22.464 ;
     RECT  196.956 21.149 202.95 22.464 ;
     RECT  212.04 22.073 212.058 22.469 ;
     RECT  215.568 22.235 217.782 22.469 ;
     RECT  0.108 22.459 0.126 22.507 ;
     RECT  207.18 21.469 208.314 22.513 ;
     RECT  209.448 21.965 210.654 22.513 ;
     RECT  1.728 22.464 202.95 22.541 ;
     RECT  0.108 22.507 0.198 22.651 ;
     RECT  206.028 21.979 206.37 22.891 ;
     RECT  207.18 22.513 210.654 22.891 ;
     RECT  218.88 21.929 218.898 22.939 ;
     RECT  213.015 22.073 213.297 23.089 ;
     RECT  215.604 22.469 217.782 23.089 ;
     RECT  215.604 23.089 217.818 23.125 ;
     RECT  218.88 22.939 219.438 23.125 ;
     RECT  206.028 22.891 210.654 23.165 ;
     RECT  215.604 23.125 219.438 23.165 ;
     RECT  218.88 23.165 219.438 23.189 ;
     RECT  0.108 22.651 0.306 23.227 ;
     RECT  219.384 23.189 219.438 23.279 ;
     RECT  211.5 23.161 211.518 23.287 ;
     RECT  212.904 23.089 213.297 23.287 ;
     RECT  214.344 23.323 214.362 23.431 ;
     RECT  215.604 23.165 217.818 23.431 ;
     RECT  214.308 23.431 214.506 23.549 ;
     RECT  215.388 23.431 217.818 23.549 ;
     RECT  206.028 23.165 206.262 23.585 ;
     RECT  211.5 23.287 213.297 23.585 ;
     RECT  214.308 23.549 214.362 23.585 ;
     RECT  215.388 23.549 217.746 23.585 ;
     RECT  214.344 23.585 214.362 23.657 ;
     RECT  211.5 23.585 211.59 23.729 ;
     RECT  207.18 23.165 210.654 23.819 ;
     RECT  215.784 23.585 217.746 23.819 ;
     RECT  0.108 23.227 0.594 23.981 ;
     RECT  203.76 20.525 204.354 24.233 ;
     RECT  219.42 23.279 219.438 24.241 ;
     RECT  218.88 24.241 219.438 24.283 ;
     RECT  212.436 23.585 213.297 24.331 ;
     RECT  211.5 23.729 211.518 24.475 ;
     RECT  209.628 23.819 210.654 24.511 ;
     RECT  211.464 24.475 211.518 24.511 ;
     RECT  212.436 24.331 213.822 24.511 ;
     RECT  206.028 23.585 206.046 24.539 ;
     RECT  220.212 24.379 220.23 24.571 ;
     RECT  207.18 23.819 208.818 24.629 ;
     RECT  209.628 24.511 214.434 24.629 ;
     RECT  207.18 24.629 208.674 24.653 ;
     RECT  216.612 23.819 217.746 24.665 ;
     RECT  218.844 24.283 219.438 24.701 ;
     RECT  215.532 24.331 215.766 24.745 ;
     RECT  216.612 24.665 217.602 24.745 ;
     RECT  212.976 24.629 214.434 24.781 ;
     RECT  215.532 24.745 217.602 24.781 ;
     RECT  204.336 24.233 204.354 24.809 ;
     RECT  209.628 24.629 212.022 24.809 ;
     RECT  220.176 24.571 220.23 24.859 ;
     RECT  209.628 24.809 211.014 24.899 ;
     RECT  211.752 24.809 212.022 24.899 ;
     RECT  218.844 24.701 218.898 24.989 ;
     RECT  212.976 24.781 217.602 25.043 ;
     RECT  1.728 22.541 202.497 25.045 ;
     RECT  210.6 24.899 211.014 25.079 ;
     RECT  1.656 25.045 202.497 25.085 ;
     RECT  1.728 25.085 202.497 25.169 ;
     RECT  207.18 24.653 208.314 25.169 ;
     RECT  210.6 25.079 210.978 25.169 ;
     RECT  220.14 24.859 220.23 25.169 ;
     RECT  1.728 25.169 201.33 25.205 ;
     RECT  209.556 25.051 209.574 25.205 ;
     RECT  213.015 25.043 217.602 25.205 ;
     RECT  213.015 25.205 214.902 25.277 ;
     RECT  1.764 25.205 201.33 25.313 ;
     RECT  210.6 25.169 210.942 25.349 ;
     RECT  214.56 25.277 214.902 25.439 ;
     RECT  215.712 25.205 217.602 25.439 ;
     RECT  210.924 25.349 210.942 25.475 ;
     RECT  220.14 25.169 220.194 25.709 ;
     RECT  215.964 25.439 217.602 25.745 ;
     RECT  216.18 25.745 217.566 25.979 ;
     RECT  220.14 25.709 220.158 25.979 ;
     RECT  216.828 25.979 217.566 26.015 ;
     RECT  1.8 25.313 201.33 26.107 ;
     RECT  218.844 24.989 218.862 26.249 ;
     RECT  216.828 26.015 217.422 26.285 ;
     RECT  214.884 25.439 214.902 26.519 ;
     RECT  216.936 26.285 217.422 26.519 ;
     RECT  0.576 23.981 0.594 26.555 ;
     RECT  1.728 26.107 201.33 26.663 ;
     RECT  6.624 26.663 201.33 26.699 ;
     RECT  6.624 26.699 200.754 26.789 ;
     RECT  213.015 25.277 213.786 26.789 ;
     RECT  217.404 26.519 217.422 26.789 ;
     RECT  6.624 26.789 199.89 27.059 ;
     RECT  1.728 26.663 5.85 27.635 ;
     RECT  1.764 27.635 5.85 27.869 ;
     RECT  1.764 27.869 4.806 27.905 ;
     RECT  8.82 27.059 199.89 27.965 ;
     RECT  2.304 27.905 3.078 28.139 ;
     RECT  2.304 28.139 2.697 28.175 ;
     RECT  3.996 27.905 4.806 28.175 ;
     RECT  200.736 26.789 200.754 28.253 ;
     RECT  198.396 27.965 199.89 28.349 ;
     RECT  198.396 28.349 198.702 28.541 ;
     RECT  198.684 28.541 198.702 28.637 ;
     RECT  8.82 27.965 197.55 28.795 ;
     RECT  8.82 28.795 197.586 29.021 ;
     RECT  199.62 28.349 199.89 29.021 ;
     RECT  4.392 28.175 4.806 29.029 ;
     RECT  4.14 29.029 4.806 29.057 ;
     RECT  4.14 29.057 4.734 30.721 ;
     RECT  5.796 27.869 5.85 30.721 ;
     RECT  3.996 30.721 4.734 30.749 ;
     RECT  8.82 29.021 197.55 31.351 ;
     RECT  199.62 29.021 199.746 31.415 ;
     RECT  8.82 31.351 197.658 33.437 ;
     RECT  21.384 33.437 197.658 33.629 ;
     RECT  21.564 33.629 197.658 34.763 ;
     RECT  8.82 33.437 20.394 35.159 ;
     RECT  199.62 31.415 199.638 35.195 ;
     RECT  8.82 35.159 20.142 35.645 ;
     RECT  21.564 34.763 197.622 35.933 ;
     RECT  8.82 35.645 18.954 36.481 ;
     RECT  8.82 36.481 19.026 36.553 ;
     RECT  19.764 35.645 20.142 36.553 ;
     RECT  8.82 36.553 20.142 37.277 ;
     RECT  8.82 37.277 19.026 38.209 ;
     RECT  19.764 37.277 20.142 38.209 ;
     RECT  8.82 38.209 20.142 38.309 ;
     RECT  13.215 38.309 20.142 38.525 ;
     RECT  21.78 35.933 197.622 38.587 ;
     RECT  13.215 38.525 20.07 38.621 ;
     RECT  13.215 38.621 19.782 38.669 ;
     RECT  21.78 38.587 197.658 38.717 ;
     RECT  18.108 38.669 19.782 39.005 ;
     RECT  8.82 38.309 12.366 39.581 ;
     RECT  21.78 38.717 197.586 39.773 ;
     RECT  3.996 30.749 4.662 39.869 ;
     RECT  5.724 30.721 5.85 40.109 ;
     RECT  21.996 39.773 197.586 40.157 ;
     RECT  199.404 40.135 199.422 40.675 ;
     RECT  18.108 39.005 19.278 40.925 ;
     RECT  199.404 40.675 199.674 40.981 ;
     RECT  22.32 40.157 197.586 41.021 ;
     RECT  199.404 40.981 199.818 41.368 ;
     RECT  13.215 38.669 17.262 41.501 ;
     RECT  198.936 41.368 199.818 41.521 ;
     RECT  18.615 40.925 19.278 41.597 ;
     RECT  22.32 41.021 197.448 41.693 ;
     RECT  10.548 39.581 12.366 41.981 ;
     RECT  198.936 41.521 199.926 42.061 ;
     RECT  22.32 41.693 22.482 42.077 ;
     RECT  23.22 41.693 197.448 42.173 ;
     RECT  198.936 42.061 200.106 42.179 ;
     RECT  15.66 41.501 17.262 42.269 ;
     RECT  10.548 41.981 11.826 42.287 ;
     RECT  6.624 27.059 8.097 42.557 ;
     RECT  15.732 42.269 17.262 42.749 ;
     RECT  22.32 42.077 22.338 42.845 ;
     RECT  18.615 41.597 19.026 42.871 ;
     RECT  13.215 41.501 14.562 42.893 ;
     RECT  18.615 42.871 19.062 42.941 ;
     RECT  10.548 42.287 11.79 43.037 ;
     RECT  23.328 42.173 197.448 43.051 ;
     RECT  16.668 42.749 17.262 43.085 ;
     RECT  11.196 43.037 11.79 43.133 ;
     RECT  198.936 42.179 199.926 43.259 ;
     RECT  198.936 43.259 199.242 43.331 ;
     RECT  14.544 42.893 14.562 43.367 ;
     RECT  11.232 43.133 11.79 43.373 ;
     RECT  8.82 39.581 9.486 43.421 ;
     RECT  23.22 43.051 197.448 43.517 ;
     RECT  16.956 43.085 17.262 43.529 ;
     RECT  16.956 43.529 16.974 43.613 ;
     RECT  11.304 43.373 11.79 43.661 ;
     RECT  5.724 40.109 5.742 43.709 ;
     RECT  200.124 43.681 200.142 43.799 ;
     RECT  11.304 43.661 11.322 43.901 ;
     RECT  18.615 42.941 18.99 43.997 ;
     RECT  198.936 43.331 199.134 44.059 ;
     RECT  4.644 39.869 4.662 44.077 ;
     RECT  7.272 42.557 8.097 44.093 ;
     RECT  4.608 44.077 4.662 44.177 ;
     RECT  8.82 43.421 8.838 44.189 ;
     RECT  198.936 44.059 199.17 44.879 ;
     RECT  199.152 44.879 199.17 44.951 ;
     RECT  15.732 42.749 15.75 47.323 ;
     RECT  15.3 47.323 15.75 47.357 ;
     RECT  15.3 47.357 15.318 47.579 ;
     RECT  13.215 42.893 13.497 47.731 ;
     RECT  23.328 43.517 197.448 52.2 ;
     RECT  24.207 54.253 24.297 54.523 ;
     RECT  29.607 54.253 29.697 54.523 ;
     RECT  35.007 54.253 35.097 54.523 ;
     RECT  40.407 54.253 40.497 54.523 ;
     RECT  45.807 54.253 45.897 54.523 ;
     RECT  51.207 54.253 51.297 54.523 ;
     RECT  56.607 54.253 56.697 54.523 ;
     RECT  62.007 54.253 62.097 54.523 ;
     RECT  67.407 54.253 67.497 54.523 ;
     RECT  72.807 54.253 72.897 54.523 ;
     RECT  78.207 54.253 78.297 54.523 ;
     RECT  83.607 54.253 83.697 54.523 ;
     RECT  89.007 54.253 89.097 54.523 ;
     RECT  94.407 54.253 94.497 54.523 ;
     RECT  99.807 54.253 99.897 54.523 ;
     RECT  105.207 54.253 105.297 54.523 ;
     RECT  110.607 54.253 110.697 54.523 ;
     RECT  116.007 54.253 116.097 54.523 ;
     RECT  121.407 54.253 121.497 54.523 ;
     RECT  126.807 54.253 126.897 54.523 ;
     RECT  132.207 54.253 132.297 54.523 ;
     RECT  137.607 54.253 137.697 54.523 ;
     RECT  143.007 54.253 143.097 54.523 ;
     RECT  148.407 54.253 148.497 54.523 ;
     RECT  153.807 54.253 153.897 54.523 ;
     RECT  159.207 54.253 159.297 54.523 ;
     RECT  164.607 54.253 164.697 54.523 ;
     RECT  170.007 54.253 170.097 54.523 ;
     RECT  175.407 54.253 175.497 54.523 ;
     RECT  180.807 54.253 180.897 54.523 ;
     RECT  186.207 54.253 186.297 54.523 ;
     RECT  191.607 54.253 191.697 54.523 ;
     RECT  197.007 54.253 197.097 54.523 ;
     RECT  4.608 44.177 4.626 59.999 ;
     RECT  5.148 60.115 5.166 67.829 ;
     RECT  4.932 67.945 4.95 70.681 ;
     RECT  4.932 70.681 5.022 70.709 ;
     RECT  2.415 28.175 2.697 73.187 ;
     RECT  7.815 44.093 8.097 73.187 ;
     RECT  13.215 47.731 14.202 73.187 ;
     RECT  18.615 43.997 18.897 73.187 ;
     RECT  24.015 54.523 24.297 73.187 ;
     RECT  29.415 54.523 29.697 73.187 ;
     RECT  34.815 54.523 35.097 73.187 ;
     RECT  40.215 54.523 40.497 73.187 ;
     RECT  45.615 54.523 45.897 73.187 ;
     RECT  51.015 54.523 51.297 73.187 ;
     RECT  56.415 54.523 56.697 73.187 ;
     RECT  61.815 54.523 62.097 73.187 ;
     RECT  67.215 54.523 67.497 73.187 ;
     RECT  72.615 54.523 72.897 73.187 ;
     RECT  78.015 54.523 78.297 73.187 ;
     RECT  83.415 54.523 83.697 73.187 ;
     RECT  88.815 54.523 89.097 73.187 ;
     RECT  94.215 54.523 94.497 73.187 ;
     RECT  99.615 54.523 99.897 73.187 ;
     RECT  105.015 54.523 105.297 73.187 ;
     RECT  110.415 54.523 110.697 73.187 ;
     RECT  115.815 54.523 116.097 73.187 ;
     RECT  121.215 54.523 121.497 73.187 ;
     RECT  126.615 54.523 126.897 73.187 ;
     RECT  132.015 54.523 132.297 73.187 ;
     RECT  137.415 54.523 137.697 73.187 ;
     RECT  142.815 54.523 143.097 73.187 ;
     RECT  148.215 54.523 148.497 73.187 ;
     RECT  153.615 54.523 153.897 73.187 ;
     RECT  159.015 54.523 159.297 73.187 ;
     RECT  164.415 54.523 164.697 73.187 ;
     RECT  169.815 54.523 170.097 73.187 ;
     RECT  175.215 54.523 175.497 73.187 ;
     RECT  180.615 54.523 180.897 73.187 ;
     RECT  186.015 54.523 186.297 73.187 ;
     RECT  191.415 54.523 191.697 73.187 ;
     RECT  196.815 54.523 197.097 73.187 ;
     RECT  202.215 25.169 202.497 73.187 ;
     RECT  207.615 25.169 207.897 73.187 ;
     RECT  213.015 26.789 213.297 73.187 ;
     RECT  2.415 73.187 2.505 73.457 ;
     RECT  7.815 73.187 7.905 73.457 ;
     RECT  13.215 73.187 13.305 73.457 ;
     RECT  18.615 73.187 18.705 73.457 ;
     RECT  24.015 73.187 24.105 73.457 ;
     RECT  29.415 73.187 29.505 73.457 ;
     RECT  34.815 73.187 34.905 73.457 ;
     RECT  40.215 73.187 40.305 73.457 ;
     RECT  45.615 73.187 45.705 73.457 ;
     RECT  51.015 73.187 51.105 73.457 ;
     RECT  56.415 73.187 56.505 73.457 ;
     RECT  61.815 73.187 61.905 73.457 ;
     RECT  67.215 73.187 67.305 73.457 ;
     RECT  72.615 73.187 72.705 73.457 ;
     RECT  78.015 73.187 78.105 73.457 ;
     RECT  83.415 73.187 83.505 73.457 ;
     RECT  88.815 73.187 88.905 73.457 ;
     RECT  94.215 73.187 94.305 73.457 ;
     RECT  99.615 73.187 99.705 73.457 ;
     RECT  105.015 73.187 105.105 73.457 ;
     RECT  110.415 73.187 110.505 73.457 ;
     RECT  115.815 73.187 115.905 73.457 ;
     RECT  121.215 73.187 121.305 73.457 ;
     RECT  126.615 73.187 126.705 73.457 ;
     RECT  132.015 73.187 132.105 73.457 ;
     RECT  137.415 73.187 137.505 73.457 ;
     RECT  142.815 73.187 142.905 73.457 ;
     RECT  148.215 73.187 148.305 73.457 ;
     RECT  153.615 73.187 153.705 73.457 ;
     RECT  159.015 73.187 159.105 73.457 ;
     RECT  164.415 73.187 164.505 73.457 ;
     RECT  169.815 73.187 169.905 73.457 ;
     RECT  175.215 73.187 175.305 73.457 ;
     RECT  180.615 73.187 180.705 73.457 ;
     RECT  186.015 73.187 186.105 73.457 ;
     RECT  191.415 73.187 191.505 73.457 ;
     RECT  196.815 73.187 196.905 73.457 ;
     RECT  202.215 73.187 202.305 73.457 ;
     RECT  207.615 73.187 207.705 73.457 ;
     RECT  213.015 73.187 213.105 73.457 ;
     RECT  14.184 73.187 14.202 75.485 ;
    LAYER M4 ;
     RECT  0.06 11.52 0.097 23.736 ;
     RECT  0.06 24.768 0.097 25.08 ;
     RECT  0.06 9.696 2.329 10.488 ;
     RECT  0.097 11.52 2.329 25.08 ;
     RECT  0.06 5.088 2.408 5.88 ;
     RECT  0.06 6.912 2.408 7.608 ;
     RECT  2.329 9.696 2.408 25.08 ;
     RECT  0.06 26.112 2.408 26.808 ;
     RECT  2.408 2.148 2.512 73.452 ;
     RECT  2.512 2.418 2.704 73.182 ;
     RECT  2.704 6.768 3.521 26.28 ;
     RECT  3.521 7.92 3.697 26.28 ;
     RECT  2.704 4.896 4.561 5.448 ;
     RECT  3.521 6.768 4.561 6.84 ;
     RECT  3.697 7.92 4.601 26.424 ;
     RECT  4.601 7.92 4.637 26.376 ;
     RECT  4.637 7.968 4.709 26.376 ;
     RECT  4.561 4.896 4.925 6.84 ;
     RECT  4.709 8.208 5.177 26.376 ;
     RECT  5.177 8.496 5.249 26.376 ;
     RECT  5.249 15.312 5.609 26.376 ;
     RECT  5.609 23.376 5.821 26.376 ;
     RECT  3.985 39.84 5.821 39.864 ;
     RECT  4.925 4.896 5.825 6.024 ;
     RECT  5.825 5.472 5.965 6.024 ;
     RECT  5.857 7.392 5.965 7.416 ;
     RECT  5.821 23.376 6.149 26.52 ;
     RECT  5.249 8.496 6.437 14.28 ;
     RECT  6.437 8.496 6.473 13.272 ;
     RECT  6.149 24.528 6.581 26.52 ;
     RECT  5.609 15.312 6.649 22.296 ;
     RECT  6.149 23.376 6.649 23.496 ;
     RECT  6.473 8.496 6.653 10.248 ;
     RECT  6.473 11.232 6.725 13.272 ;
     RECT  6.581 24.528 6.833 25.224 ;
     RECT  5.821 39.84 6.865 40.104 ;
     RECT  6.437 14.256 6.901 14.28 ;
     RECT  6.649 15.312 6.901 23.496 ;
     RECT  6.865 39.552 6.901 40.104 ;
     RECT  6.901 39.552 7.225 40.632 ;
     RECT  5.713 43.68 7.261 43.704 ;
     RECT  6.613 42.528 7.441 42.552 ;
     RECT  7.261 43.68 7.441 44.088 ;
     RECT  5.965 5.472 7.808 7.416 ;
     RECT  6.653 9.408 7.808 10.248 ;
     RECT  6.725 11.232 7.808 11.976 ;
     RECT  6.725 13.104 7.808 13.272 ;
     RECT  6.901 14.256 7.808 23.496 ;
     RECT  6.833 24.528 7.808 25.128 ;
     RECT  6.581 26.208 7.808 26.52 ;
     RECT  7.225 38.784 7.808 40.632 ;
     RECT  7.441 42.528 7.808 44.088 ;
     RECT  7.808 2.148 7.912 73.452 ;
     RECT  7.912 2.418 8.104 73.182 ;
     RECT  8.104 5.472 8.165 7.416 ;
     RECT  8.104 16.32 8.201 23.352 ;
     RECT  8.104 9.504 8.273 10.104 ;
     RECT  8.201 23.136 8.273 23.352 ;
     RECT  8.165 5.472 8.309 6.552 ;
     RECT  8.104 11.232 8.309 11.976 ;
     RECT  8.273 9.504 8.381 9.576 ;
     RECT  8.201 16.32 8.453 22.056 ;
     RECT  8.104 26.352 8.489 26.376 ;
     RECT  8.309 11.232 8.525 11.688 ;
     RECT  8.104 15.216 9.461 15.24 ;
     RECT  8.273 23.136 9.961 23.304 ;
     RECT  8.104 35.712 10.141 35.736 ;
     RECT  8.104 38.928 10.573 40.632 ;
     RECT  10.573 38.928 10.645 40.728 ;
     RECT  8.104 42.528 11.653 44.184 ;
     RECT  10.645 38.688 11.725 40.728 ;
     RECT  11.725 37.92 12.229 40.728 ;
     RECT  11.653 41.76 12.229 44.184 ;
     RECT  12.445 26.016 12.481 26.04 ;
     RECT  11.905 34.368 12.517 34.392 ;
     RECT  10.141 35.52 12.733 35.736 ;
     RECT  12.481 26.016 12.949 26.616 ;
     RECT  12.949 26.016 13.021 26.808 ;
     RECT  8.309 6.048 13.208 6.552 ;
     RECT  8.381 9.504 13.208 9.528 ;
     RECT  8.525 11.664 13.208 11.688 ;
     RECT  8.453 16.512 13.208 22.056 ;
     RECT  9.961 23.136 13.208 23.64 ;
     RECT  13.021 25.248 13.208 26.808 ;
     RECT  11.941 28.704 13.208 28.728 ;
     RECT  11.365 30.912 13.208 30.936 ;
     RECT  12.517 34.08 13.208 34.392 ;
     RECT  12.733 35.52 13.208 36.072 ;
     RECT  12.229 37.92 13.208 44.184 ;
     RECT  13.208 2.148 13.312 73.452 ;
     RECT  13.312 2.418 13.504 73.182 ;
     RECT  4.021 75.456 14.213 75.48 ;
     RECT  13.504 23.136 14.569 23.64 ;
     RECT  13.504 25.248 14.893 26.808 ;
     RECT  14.749 32.064 14.929 32.088 ;
     RECT  13.504 28.56 15.289 28.584 ;
     RECT  15.289 47.328 15.761 47.352 ;
     RECT  13.504 16.512 15.865 22.056 ;
     RECT  14.929 32.064 15.865 32.28 ;
     RECT  14.893 25.248 16.117 27.384 ;
     RECT  15.289 28.56 16.117 29.304 ;
     RECT  13.504 34.08 16.369 44.184 ;
     RECT  13.504 30.912 16.441 30.936 ;
     RECT  15.865 32.064 16.441 32.808 ;
     RECT  15.865 15.744 16.801 22.056 ;
     RECT  14.569 23.136 16.801 24.12 ;
     RECT  16.441 30.912 17.341 32.808 ;
     RECT  16.369 33.888 17.341 44.184 ;
     RECT  16.117 25.248 17.377 29.304 ;
     RECT  17.341 30.912 17.377 44.184 ;
     RECT  16.801 15.744 18.169 24.12 ;
     RECT  17.377 25.248 18.169 44.184 ;
     RECT  16.837 14.736 18.529 14.76 ;
     RECT  13.504 6.048 18.608 6.552 ;
     RECT  13.504 9.504 18.608 9.528 ;
     RECT  13.504 11.664 18.608 11.688 ;
     RECT  13.504 13.056 18.608 13.08 ;
     RECT  18.529 14.688 18.608 14.76 ;
     RECT  18.169 15.744 18.608 44.184 ;
     RECT  18.608 2.148 18.712 73.452 ;
     RECT  18.712 2.418 18.904 73.182 ;
     RECT  18.904 14.688 19.001 44.184 ;
     RECT  18.904 11.664 21.773 11.688 ;
     RECT  19.001 14.736 23.4 44.184 ;
     RECT  18.904 6.048 24.008 6.552 ;
     RECT  18.904 9.504 24.008 9.528 ;
     RECT  18.904 13.056 24.008 13.08 ;
     RECT  23.4 14.736 24.008 52.2 ;
     RECT  24.008 2.148 24.112 52.2 ;
     RECT  24.008 54.528 24.112 73.452 ;
     RECT  24.112 54.528 24.2 73.182 ;
     RECT  24.112 2.418 24.304 52.2 ;
     RECT  24.2 54.258 24.304 73.182 ;
     RECT  24.304 6.048 29.408 6.6 ;
     RECT  24.304 9.504 29.408 9.528 ;
     RECT  25.909 11.952 29.408 11.976 ;
     RECT  24.304 13.056 29.408 13.08 ;
     RECT  24.304 14.736 29.408 52.2 ;
     RECT  29.408 2.148 29.512 52.2 ;
     RECT  29.408 54.528 29.512 73.452 ;
     RECT  29.512 54.528 29.6 73.182 ;
     RECT  29.512 2.418 29.704 52.2 ;
     RECT  29.6 54.258 29.704 73.182 ;
     RECT  29.704 6.048 34.808 6.6 ;
     RECT  29.704 9.504 34.808 9.528 ;
     RECT  29.704 11.952 34.808 11.976 ;
     RECT  29.704 13.056 34.808 13.08 ;
     RECT  29.704 14.736 34.808 52.2 ;
     RECT  34.808 2.148 34.912 52.2 ;
     RECT  34.808 54.528 34.912 73.452 ;
     RECT  34.912 54.528 35 73.182 ;
     RECT  34.912 2.418 35.104 52.2 ;
     RECT  35 54.258 35.104 73.182 ;
     RECT  35.104 6.048 40.208 6.6 ;
     RECT  35.104 9.504 40.208 9.528 ;
     RECT  35.104 11.952 40.208 11.976 ;
     RECT  35.104 13.056 40.208 13.08 ;
     RECT  35.104 14.736 40.208 52.2 ;
     RECT  40.208 2.148 40.312 52.2 ;
     RECT  40.208 54.528 40.312 73.452 ;
     RECT  40.312 54.528 40.4 73.182 ;
     RECT  40.312 2.418 40.504 52.2 ;
     RECT  40.4 54.258 40.504 73.182 ;
     RECT  40.504 6.048 45.608 6.6 ;
     RECT  40.504 9.504 45.608 9.528 ;
     RECT  40.504 11.952 45.608 11.976 ;
     RECT  40.504 13.056 45.608 13.08 ;
     RECT  40.504 14.736 45.608 52.2 ;
     RECT  45.608 2.148 45.712 52.2 ;
     RECT  45.608 54.528 45.712 73.452 ;
     RECT  45.712 54.528 45.8 73.182 ;
     RECT  45.712 2.418 45.904 52.2 ;
     RECT  45.8 54.258 45.904 73.182 ;
     RECT  45.904 11.952 47.725 11.976 ;
     RECT  45.904 13.056 47.725 13.08 ;
     RECT  45.904 6.048 51.008 6.6 ;
     RECT  45.904 9.504 51.008 9.528 ;
     RECT  47.725 11.952 51.008 13.08 ;
     RECT  45.904 14.736 51.008 52.2 ;
     RECT  51.008 2.148 51.112 52.2 ;
     RECT  51.008 54.528 51.112 73.452 ;
     RECT  51.112 54.528 51.2 73.182 ;
     RECT  51.112 2.418 51.304 52.2 ;
     RECT  51.2 54.258 51.304 73.182 ;
     RECT  51.304 6.048 56.408 6.6 ;
     RECT  51.304 9.504 56.408 9.528 ;
     RECT  51.304 11.952 56.408 13.08 ;
     RECT  51.304 14.736 56.408 52.2 ;
     RECT  56.408 2.148 56.512 52.2 ;
     RECT  56.408 54.528 56.512 73.452 ;
     RECT  56.512 54.528 56.6 73.182 ;
     RECT  56.512 2.418 56.704 52.2 ;
     RECT  56.6 54.258 56.704 73.182 ;
     RECT  56.704 11.952 59.533 13.08 ;
     RECT  56.704 6.048 59.825 6.6 ;
     RECT  59.533 11.952 60.577 13.368 ;
     RECT  59.825 6.576 61.808 6.6 ;
     RECT  56.704 9.504 61.808 9.528 ;
     RECT  60.577 11.136 61.808 13.368 ;
     RECT  56.704 14.736 61.808 52.2 ;
     RECT  61.808 2.148 61.912 52.2 ;
     RECT  61.808 54.528 61.912 73.452 ;
     RECT  61.912 54.528 62 73.182 ;
     RECT  61.912 2.418 62.104 52.2 ;
     RECT  62 54.258 62.104 73.182 ;
     RECT  62.104 6.576 67.208 6.6 ;
     RECT  62.104 9.504 67.208 9.528 ;
     RECT  62.104 11.136 67.208 13.368 ;
     RECT  62.104 14.736 67.208 52.2 ;
     RECT  67.208 2.148 67.312 52.2 ;
     RECT  67.208 54.528 67.312 73.452 ;
     RECT  67.312 54.528 67.4 73.182 ;
     RECT  67.312 2.418 67.504 52.2 ;
     RECT  67.4 54.258 67.504 73.182 ;
     RECT  67.504 6.576 72.608 6.6 ;
     RECT  67.504 9.504 72.608 9.528 ;
     RECT  67.504 11.136 72.608 13.368 ;
     RECT  67.504 14.736 72.608 52.2 ;
     RECT  72.608 2.148 72.712 52.2 ;
     RECT  72.608 54.528 72.712 73.452 ;
     RECT  72.712 54.528 72.8 73.182 ;
     RECT  72.712 2.418 72.904 52.2 ;
     RECT  72.8 54.258 72.904 73.182 ;
     RECT  72.904 9.504 73.001 9.528 ;
     RECT  72.904 6.576 78.008 6.6 ;
     RECT  72.904 11.136 78.008 13.368 ;
     RECT  72.904 14.736 78.008 52.2 ;
     RECT  78.008 2.148 78.112 52.2 ;
     RECT  78.008 54.528 78.112 73.452 ;
     RECT  78.112 54.528 78.2 73.182 ;
     RECT  78.112 2.418 78.304 52.2 ;
     RECT  78.2 54.258 78.304 73.182 ;
     RECT  78.304 6.576 83.408 6.6 ;
     RECT  78.304 11.136 83.408 13.368 ;
     RECT  78.304 14.736 83.408 52.2 ;
     RECT  83.408 2.148 83.512 52.2 ;
     RECT  83.408 54.528 83.512 73.452 ;
     RECT  83.512 54.528 83.6 73.182 ;
     RECT  83.512 2.418 83.704 52.2 ;
     RECT  83.6 54.258 83.704 73.182 ;
     RECT  83.704 6.576 88.808 6.6 ;
     RECT  83.704 11.136 88.808 13.368 ;
     RECT  83.704 14.736 88.808 52.2 ;
     RECT  88.808 2.148 88.912 52.2 ;
     RECT  88.808 54.528 88.912 73.452 ;
     RECT  88.912 54.528 89 73.182 ;
     RECT  88.912 2.418 89.104 52.2 ;
     RECT  89 54.258 89.104 73.182 ;
     RECT  89.104 11.136 92.725 13.368 ;
     RECT  89.104 14.736 92.725 52.2 ;
     RECT  89.104 6.576 94.208 6.6 ;
     RECT  92.725 11.136 94.208 52.2 ;
     RECT  94.208 2.148 94.312 52.2 ;
     RECT  94.208 54.528 94.312 73.452 ;
     RECT  94.312 54.528 94.4 73.182 ;
     RECT  94.312 2.418 94.504 52.2 ;
     RECT  94.4 54.258 94.504 73.182 ;
     RECT  94.504 6.576 99.608 6.6 ;
     RECT  94.504 11.136 99.608 52.2 ;
     RECT  99.608 2.148 99.712 52.2 ;
     RECT  99.608 54.528 99.712 73.452 ;
     RECT  99.712 54.528 99.8 73.182 ;
     RECT  99.712 2.418 99.904 52.2 ;
     RECT  99.8 54.258 99.904 73.182 ;
     RECT  99.904 6.576 105.008 6.6 ;
     RECT  99.904 11.136 105.008 52.2 ;
     RECT  105.008 2.148 105.112 52.2 ;
     RECT  105.008 54.528 105.112 73.452 ;
     RECT  105.112 54.528 105.2 73.182 ;
     RECT  105.112 2.418 105.304 52.2 ;
     RECT  105.2 54.258 105.304 73.182 ;
     RECT  105.304 6.576 110.408 6.6 ;
     RECT  105.304 11.136 110.408 52.2 ;
     RECT  110.408 2.148 110.512 52.2 ;
     RECT  110.408 54.528 110.512 73.452 ;
     RECT  110.512 54.528 110.6 73.182 ;
     RECT  110.512 2.418 110.704 52.2 ;
     RECT  110.6 54.258 110.704 73.182 ;
     RECT  110.704 6.576 115.808 6.6 ;
     RECT  110.704 11.136 115.808 52.2 ;
     RECT  115.808 2.148 115.912 52.2 ;
     RECT  115.808 54.528 115.912 73.452 ;
     RECT  115.912 54.528 116 73.182 ;
     RECT  115.912 2.418 116.104 52.2 ;
     RECT  116 54.258 116.104 73.182 ;
     RECT  116.104 6.576 121.208 6.6 ;
     RECT  116.104 11.136 121.208 13.08 ;
     RECT  116.104 14.112 121.208 52.2 ;
     RECT  121.208 2.148 121.312 52.2 ;
     RECT  121.208 54.528 121.312 73.452 ;
     RECT  121.312 54.528 121.4 73.182 ;
     RECT  121.312 2.418 121.504 52.2 ;
     RECT  121.4 54.258 121.504 73.182 ;
     RECT  121.504 14.112 124.733 52.2 ;
     RECT  121.504 11.136 124.949 13.08 ;
     RECT  124.733 15.696 125.453 52.2 ;
     RECT  121.504 6.576 126.608 6.6 ;
     RECT  124.949 11.136 126.608 12.216 ;
     RECT  124.733 14.112 126.608 14.664 ;
     RECT  125.453 15.696 126.608 16.344 ;
     RECT  125.453 17.472 126.608 52.2 ;
     RECT  126.608 2.148 126.712 52.2 ;
     RECT  126.608 54.528 126.712 73.452 ;
     RECT  126.712 54.528 126.8 73.182 ;
     RECT  126.712 2.418 126.904 52.2 ;
     RECT  126.8 54.258 126.904 73.182 ;
     RECT  126.904 17.472 128.045 52.2 ;
     RECT  126.904 6.576 132.008 6.6 ;
     RECT  126.904 11.136 132.008 12.216 ;
     RECT  126.904 14.112 132.008 14.664 ;
     RECT  126.904 15.696 132.008 16.344 ;
     RECT  128.045 18.192 132.008 52.2 ;
     RECT  132.008 2.148 132.112 52.2 ;
     RECT  132.008 54.528 132.112 73.452 ;
     RECT  132.112 54.528 132.2 73.182 ;
     RECT  132.112 2.418 132.304 52.2 ;
     RECT  132.2 54.258 132.304 73.182 ;
     RECT  132.304 6.576 137.408 6.6 ;
     RECT  132.304 11.136 137.408 12.216 ;
     RECT  132.304 14.112 137.408 14.664 ;
     RECT  132.304 15.696 137.408 16.344 ;
     RECT  132.304 18.192 137.408 52.2 ;
     RECT  137.408 2.148 137.512 52.2 ;
     RECT  137.408 54.528 137.512 73.452 ;
     RECT  137.512 54.528 137.6 73.182 ;
     RECT  137.512 2.418 137.704 52.2 ;
     RECT  137.6 54.258 137.704 73.182 ;
     RECT  137.704 11.136 142.808 12.216 ;
     RECT  137.704 14.112 142.808 14.664 ;
     RECT  137.704 15.696 142.808 16.344 ;
     RECT  137.704 18.192 142.808 52.2 ;
     RECT  142.808 2.148 142.912 52.2 ;
     RECT  142.808 54.528 142.912 73.452 ;
     RECT  142.912 54.528 143 73.182 ;
     RECT  142.912 2.418 143.104 52.2 ;
     RECT  143 54.258 143.104 73.182 ;
     RECT  143.104 11.136 148.208 12.216 ;
     RECT  143.104 14.112 148.208 14.664 ;
     RECT  143.104 15.696 148.208 16.344 ;
     RECT  143.104 18.192 148.208 52.2 ;
     RECT  148.208 2.148 148.312 52.2 ;
     RECT  148.208 54.528 148.312 73.452 ;
     RECT  148.312 54.528 148.4 73.182 ;
     RECT  148.312 2.418 148.504 52.2 ;
     RECT  148.4 54.258 148.504 73.182 ;
     RECT  148.504 11.136 153.608 12.216 ;
     RECT  148.504 14.112 153.608 14.664 ;
     RECT  148.504 15.696 153.608 16.344 ;
     RECT  148.504 18.192 153.608 52.2 ;
     RECT  153.608 2.148 153.712 52.2 ;
     RECT  153.608 54.528 153.712 73.452 ;
     RECT  153.712 54.528 153.8 73.182 ;
     RECT  153.712 2.418 153.904 52.2 ;
     RECT  153.8 54.258 153.904 73.182 ;
     RECT  153.904 11.136 157.637 12.216 ;
     RECT  157.637 11.136 159.008 11.976 ;
     RECT  153.904 14.112 159.008 14.664 ;
     RECT  153.904 15.696 159.008 16.344 ;
     RECT  153.904 18.192 159.008 52.2 ;
     RECT  159.008 2.148 159.112 52.2 ;
     RECT  159.008 54.528 159.112 73.452 ;
     RECT  159.112 54.528 159.2 73.182 ;
     RECT  159.112 2.418 159.304 52.2 ;
     RECT  159.2 54.258 159.304 73.182 ;
     RECT  159.304 11.136 163.289 11.976 ;
     RECT  163.289 11.136 164.408 11.688 ;
     RECT  159.304 14.112 164.408 14.664 ;
     RECT  159.304 15.696 164.408 16.344 ;
     RECT  159.304 18.192 164.408 52.2 ;
     RECT  164.408 2.148 164.512 52.2 ;
     RECT  164.408 54.528 164.512 73.452 ;
     RECT  164.512 54.528 164.6 73.182 ;
     RECT  164.512 2.418 164.704 52.2 ;
     RECT  164.6 54.258 164.704 73.182 ;
     RECT  164.704 11.136 169.808 11.688 ;
     RECT  164.704 14.112 169.808 14.664 ;
     RECT  164.704 15.696 169.808 16.344 ;
     RECT  164.704 18.192 169.808 52.2 ;
     RECT  169.808 2.148 169.912 52.2 ;
     RECT  169.808 54.528 169.912 73.452 ;
     RECT  169.912 54.528 170 73.182 ;
     RECT  169.912 2.418 170.104 52.2 ;
     RECT  170 54.258 170.104 73.182 ;
     RECT  170.104 11.664 175.208 11.688 ;
     RECT  170.104 14.112 175.208 14.664 ;
     RECT  170.104 15.696 175.208 16.344 ;
     RECT  170.104 18.192 175.208 52.2 ;
     RECT  175.208 2.148 175.312 52.2 ;
     RECT  175.208 54.528 175.312 73.452 ;
     RECT  175.312 54.528 175.4 73.182 ;
     RECT  175.312 2.418 175.504 52.2 ;
     RECT  175.4 54.258 175.504 73.182 ;
     RECT  175.504 15.792 177.833 16.344 ;
     RECT  175.504 11.664 180.608 11.688 ;
     RECT  175.504 14.112 180.608 14.664 ;
     RECT  177.833 16.128 180.608 16.344 ;
     RECT  175.504 18.192 180.608 52.2 ;
     RECT  180.608 2.148 180.712 52.2 ;
     RECT  180.608 54.528 180.712 73.452 ;
     RECT  180.712 54.528 180.8 73.182 ;
     RECT  180.712 2.418 180.904 52.2 ;
     RECT  180.8 54.258 180.904 73.182 ;
     RECT  180.904 11.664 186.008 11.688 ;
     RECT  180.904 14.112 186.008 14.664 ;
     RECT  180.904 16.128 186.008 16.344 ;
     RECT  180.904 18.192 186.008 52.2 ;
     RECT  186.008 2.148 186.112 52.2 ;
     RECT  186.008 54.528 186.112 73.452 ;
     RECT  186.112 54.528 186.2 73.182 ;
     RECT  186.112 2.418 186.304 52.2 ;
     RECT  186.2 54.258 186.304 73.182 ;
     RECT  186.304 11.664 191.408 11.688 ;
     RECT  186.304 14.112 191.408 14.664 ;
     RECT  186.304 16.128 191.408 16.344 ;
     RECT  186.304 18.192 191.408 52.2 ;
     RECT  191.408 2.148 191.512 52.2 ;
     RECT  191.408 54.528 191.512 73.452 ;
     RECT  191.512 54.528 191.6 73.182 ;
     RECT  191.512 2.418 191.704 52.2 ;
     RECT  191.6 54.258 191.704 73.182 ;
     RECT  191.704 11.664 196.808 11.688 ;
     RECT  191.704 14.112 196.808 14.664 ;
     RECT  191.704 16.128 196.808 16.344 ;
     RECT  191.704 18.192 196.808 52.2 ;
     RECT  196.808 2.148 196.912 52.2 ;
     RECT  196.808 54.528 196.912 73.452 ;
     RECT  196.912 54.528 197 73.182 ;
     RECT  196.912 2.418 197.104 52.2 ;
     RECT  197 54.258 197.104 73.182 ;
     RECT  197.104 18.192 197.376 52.2 ;
     RECT  197.376 23.232 197.561 44.088 ;
     RECT  197.561 31.872 197.597 32.088 ;
     RECT  197.561 34.656 197.597 44.088 ;
     RECT  197.597 34.656 197.633 38.712 ;
     RECT  197.561 23.232 197.669 29.016 ;
     RECT  197.633 38.592 197.669 38.712 ;
     RECT  197.669 23.328 197.741 29.016 ;
     RECT  197.741 23.424 198.461 29.016 ;
     RECT  198.461 23.712 198.641 29.016 ;
     RECT  197.376 18.192 198.785 22.152 ;
     RECT  198.785 20.832 199.037 22.152 ;
     RECT  197.597 41.088 199.181 44.088 ;
     RECT  199.181 41.088 199.253 43.224 ;
     RECT  198.641 23.808 199.577 29.016 ;
     RECT  199.253 41.088 199.685 42.84 ;
     RECT  199.577 27.744 199.721 29.016 ;
     RECT  197.104 16.128 199.757 16.344 ;
     RECT  199.685 41.568 199.793 42.84 ;
     RECT  199.577 23.808 199.829 26.712 ;
     RECT  199.793 41.568 199.829 42.36 ;
     RECT  199.721 28.224 199.901 29.016 ;
     RECT  197.104 14.112 199.937 14.664 ;
     RECT  199.829 41.664 199.937 42.36 ;
     RECT  199.829 23.808 200.081 24.408 ;
     RECT  199.829 25.632 200.081 26.712 ;
     RECT  199.037 20.832 200.117 22.056 ;
     RECT  200.081 25.632 200.153 25.656 ;
     RECT  200.081 26.688 200.693 26.712 ;
     RECT  199.901 28.224 200.765 28.248 ;
     RECT  200.081 24.384 201.233 24.408 ;
     RECT  197.104 11.664 202.208 11.688 ;
     RECT  199.937 14.64 202.208 14.664 ;
     RECT  199.757 16.128 202.208 16.296 ;
     RECT  198.785 18.192 202.208 19.8 ;
     RECT  200.117 21.408 202.208 22.056 ;
     RECT  202.208 2.148 202.312 73.452 ;
     RECT  202.312 2.418 202.504 73.182 ;
     RECT  202.504 6.912 202.529 6.936 ;
     RECT  202.504 15.984 202.961 16.296 ;
     RECT  202.504 18.96 202.961 19.8 ;
     RECT  202.504 14.64 203.285 14.808 ;
     RECT  202.961 18.96 203.789 18.984 ;
     RECT  202.504 21.408 204.469 22.056 ;
     RECT  205.765 6.288 205.873 6.312 ;
     RECT  202.504 11.664 205.873 11.688 ;
     RECT  202.961 15.984 206.017 16.152 ;
     RECT  206.017 15.984 206.309 17.064 ;
     RECT  203.285 14.784 206.341 14.808 ;
     RECT  204.469 20.496 206.381 22.056 ;
     RECT  205.873 6.288 206.413 7.224 ;
     RECT  205.873 11.664 206.413 12.312 ;
     RECT  206.413 6.288 206.453 7.944 ;
     RECT  206.413 10.992 206.917 12.312 ;
     RECT  206.917 10.992 207.205 12.792 ;
     RECT  206.413 18.528 207.457 18.552 ;
     RECT  206.453 6.288 207.608 6.312 ;
     RECT  206.453 7.92 207.608 7.944 ;
     RECT  207.205 10.128 207.608 12.792 ;
     RECT  206.341 14.4 207.608 14.808 ;
     RECT  206.309 15.984 207.608 16.68 ;
     RECT  207.457 18.432 207.608 18.552 ;
     RECT  206.381 21.408 207.608 22.056 ;
     RECT  206.629 23.136 207.608 23.16 ;
     RECT  207.608 2.148 207.712 73.452 ;
     RECT  207.712 2.418 207.904 73.182 ;
     RECT  207.904 12.768 207.965 14.52 ;
     RECT  207.965 13.68 208.037 14.424 ;
     RECT  207.904 15.984 208.037 16.824 ;
     RECT  207.904 18.432 208.181 18.552 ;
     RECT  208.037 15.984 209.005 16.392 ;
     RECT  208.181 18.528 209.081 18.552 ;
     RECT  207.904 10.992 209.225 11.016 ;
     RECT  207.904 21.408 209.437 21.432 ;
     RECT  208.037 13.68 209.473 14.28 ;
     RECT  209.473 13.68 209.653 14.568 ;
     RECT  207.904 7.92 209.693 8.664 ;
     RECT  207.904 23.136 209.765 23.16 ;
     RECT  209.005 15.984 210.017 16.536 ;
     RECT  209.725 10.368 210.121 10.392 ;
     RECT  207.904 6.288 210.485 6.312 ;
     RECT  209.693 8.112 210.733 8.664 ;
     RECT  209.653 11.376 210.733 11.4 ;
     RECT  209.437 21.408 210.737 21.672 ;
     RECT  209.653 13.68 210.773 14.952 ;
     RECT  210.121 9.888 211.237 10.392 ;
     RECT  210.733 11.376 211.237 11.976 ;
     RECT  211.237 9.888 211.277 11.976 ;
     RECT  211.277 9.936 211.345 11.976 ;
     RECT  211.201 13.056 211.345 13.08 ;
     RECT  207.904 24.624 211.345 24.648 ;
     RECT  210.373 18.768 211.349 18.792 ;
     RECT  211.345 24.528 211.349 24.648 ;
     RECT  211.345 9.936 211.565 13.08 ;
     RECT  210.017 15.984 211.565 16.008 ;
     RECT  210.733 8.112 211.669 8.712 ;
     RECT  211.565 11.184 211.745 13.08 ;
     RECT  211.381 18.336 211.781 18.744 ;
     RECT  211.781 18.336 211.889 18.36 ;
     RECT  211.745 12.192 212.029 13.08 ;
     RECT  210.773 14.544 212.605 14.952 ;
     RECT  211.525 17.088 212.605 17.112 ;
     RECT  211.921 5.712 212.713 5.736 ;
     RECT  212.029 12.192 212.893 13.56 ;
     RECT  212.605 14.544 212.893 15.24 ;
     RECT  212.713 5.28 213.008 5.736 ;
     RECT  211.669 7.776 213.008 8.712 ;
     RECT  211.565 9.936 213.008 9.96 ;
     RECT  211.745 11.184 213.008 11.208 ;
     RECT  212.893 12.192 213.008 15.24 ;
     RECT  212.605 17.088 213.008 17.496 ;
     RECT  211.165 21.12 213.008 21.144 ;
     RECT  211.349 24.528 213.008 24.552 ;
     RECT  213.008 2.148 213.112 73.452 ;
     RECT  213.112 2.418 213.304 73.182 ;
     RECT  213.304 14.64 213.365 16.056 ;
     RECT  213.304 17.472 213.365 17.496 ;
     RECT  213.365 15.552 213.689 16.056 ;
     RECT  213.304 13.296 213.797 13.656 ;
     RECT  213.797 13.296 213.977 13.32 ;
     RECT  213.689 16.032 214.297 16.056 ;
     RECT  214.297 16.032 214.337 17.016 ;
     RECT  213.304 5.28 214.373 5.304 ;
     RECT  213.304 11.904 214.373 11.928 ;
     RECT  214.337 16.464 214.733 17.016 ;
     RECT  213.304 6.864 214.981 6.888 ;
     RECT  214.981 6.864 215.197 7.032 ;
     RECT  214.733 16.992 215.201 17.016 ;
     RECT  215.341 13.584 215.377 13.608 ;
     RECT  215.197 6.624 215.557 7.032 ;
     RECT  215.557 6 215.629 7.032 ;
     RECT  215.485 10.656 215.737 10.68 ;
     RECT  215.737 10.656 215.773 10.776 ;
     RECT  215.377 13.584 215.773 14.184 ;
     RECT  215.773 10.56 215.881 10.776 ;
     RECT  215.917 9.36 215.953 9.528 ;
     RECT  215.953 9.12 215.989 9.528 ;
     RECT  215.881 10.56 215.989 10.824 ;
     RECT  215.773 13.584 215.989 14.376 ;
     RECT  215.989 9.12 216.097 10.824 ;
     RECT  215.629 6 216.205 7.08 ;
     RECT  215.773 16.8 216.205 16.824 ;
     RECT  216.205 5.472 216.313 7.08 ;
     RECT  216.097 9.12 216.353 10.872 ;
     RECT  216.313 5.232 216.421 7.08 ;
     RECT  216.353 9.12 216.425 9.528 ;
     RECT  216.205 16.752 216.425 16.824 ;
     RECT  216.421 5.232 216.461 7.944 ;
     RECT  216.425 16.8 216.713 16.824 ;
     RECT  215.989 13.536 216.749 14.376 ;
     RECT  216.749 13.536 217.249 13.56 ;
     RECT  215.089 18.672 217.253 18.696 ;
     RECT  216.425 9.36 217.325 9.528 ;
     RECT  216.461 5.472 217.753 7.944 ;
     RECT  216.353 10.56 217.753 10.872 ;
     RECT  217.249 13.344 217.753 13.56 ;
     RECT  217.429 14.832 217.753 14.856 ;
     RECT  217.753 13.152 217.789 15 ;
     RECT  217.325 9.408 218.221 9.528 ;
     RECT  217.753 10.56 218.221 11.256 ;
     RECT  218.041 18.624 218.257 18.648 ;
     RECT  217.753 5.472 218.293 8.088 ;
     RECT  218.221 9.408 218.293 11.256 ;
     RECT  217.789 13.152 218.293 15.48 ;
     RECT  216.709 21.504 218.293 21.528 ;
     RECT  218.257 18.336 218.833 18.648 ;
     RECT  218.293 5.472 218.869 15.48 ;
     RECT  218.293 21.216 218.869 21.528 ;
     RECT  218.833 24.288 218.869 24.792 ;
     RECT  218.869 21.216 218.905 21.624 ;
     RECT  218.869 5.472 219.229 16.248 ;
     RECT  218.833 18.336 219.373 18.84 ;
     RECT  218.293 23.136 219.373 23.16 ;
     RECT  218.905 21.216 219.409 21.72 ;
     RECT  219.373 23.04 219.409 23.256 ;
     RECT  219.229 5.472 219.481 17.304 ;
     RECT  219.445 4.032 220.165 4.056 ;
     RECT  219.481 5.184 220.165 17.304 ;
     RECT  219.409 21.216 220.201 21.912 ;
     RECT  220.165 4.032 220.277 17.304 ;
     RECT  220.277 5.088 220.284 17.304 ;
     RECT  219.373 18.336 220.284 19.032 ;
     RECT  220.201 21.12 220.284 21.912 ;
     RECT  219.409 22.944 220.284 23.256 ;
     RECT  218.869 24.288 220.284 24.984 ;
    LAYER M5 ;
     RECT  2.4 2.137 2.52 2.151 ;
     RECT  7.8 2.137 7.92 2.151 ;
     RECT  13.2 2.137 13.32 2.151 ;
     RECT  18.6 2.137 18.72 2.151 ;
     RECT  24 2.137 24.12 2.151 ;
     RECT  29.4 2.137 29.52 2.151 ;
     RECT  34.8 2.137 34.92 2.151 ;
     RECT  40.2 2.137 40.32 2.151 ;
     RECT  45.6 2.137 45.72 2.151 ;
     RECT  51 2.137 51.12 2.151 ;
     RECT  56.4 2.137 56.52 2.151 ;
     RECT  61.8 2.137 61.92 2.151 ;
     RECT  67.2 2.137 67.32 2.151 ;
     RECT  72.6 2.137 72.72 2.151 ;
     RECT  78 2.137 78.12 2.151 ;
     RECT  83.4 2.137 83.52 2.151 ;
     RECT  88.8 2.137 88.92 2.151 ;
     RECT  94.2 2.137 94.32 2.151 ;
     RECT  99.6 2.137 99.72 2.151 ;
     RECT  105 2.137 105.12 2.151 ;
     RECT  110.4 2.137 110.52 2.151 ;
     RECT  115.8 2.137 115.92 2.151 ;
     RECT  121.2 2.137 121.32 2.151 ;
     RECT  126.6 2.137 126.72 2.151 ;
     RECT  132 2.137 132.12 2.151 ;
     RECT  137.4 2.137 137.52 2.151 ;
     RECT  142.8 2.137 142.92 2.151 ;
     RECT  148.2 2.137 148.32 2.151 ;
     RECT  153.6 2.137 153.72 2.151 ;
     RECT  159 2.137 159.12 2.151 ;
     RECT  164.4 2.137 164.52 2.151 ;
     RECT  169.8 2.137 169.92 2.151 ;
     RECT  175.2 2.137 175.32 2.151 ;
     RECT  180.6 2.137 180.72 2.151 ;
     RECT  186 2.137 186.12 2.151 ;
     RECT  191.4 2.137 191.52 2.151 ;
     RECT  196.8 2.137 196.92 2.151 ;
     RECT  202.2 2.137 202.32 2.151 ;
     RECT  207.6 2.137 207.72 2.151 ;
     RECT  213 2.137 213.12 2.151 ;
     RECT  2.4 2.151 2.712 73.449 ;
     RECT  7.8 2.151 8.112 73.449 ;
     RECT  13.2 2.151 13.512 73.449 ;
     RECT  18.6 2.151 18.912 73.449 ;
     RECT  24 2.151 24.312 73.449 ;
     RECT  29.4 2.151 29.712 73.449 ;
     RECT  34.8 2.151 35.112 73.449 ;
     RECT  40.2 2.151 40.512 73.449 ;
     RECT  45.6 2.151 45.912 73.449 ;
     RECT  51 2.151 51.312 73.449 ;
     RECT  56.4 2.151 56.712 73.449 ;
     RECT  61.8 2.151 62.112 73.449 ;
     RECT  67.2 2.151 67.512 73.449 ;
     RECT  72.6 2.151 72.912 73.449 ;
     RECT  78 2.151 78.312 73.449 ;
     RECT  83.4 2.151 83.712 73.449 ;
     RECT  88.8 2.151 89.112 73.449 ;
     RECT  94.2 2.151 94.512 73.449 ;
     RECT  99.6 2.151 99.912 73.449 ;
     RECT  105 2.151 105.312 73.449 ;
     RECT  110.4 2.151 110.712 73.449 ;
     RECT  115.8 2.151 116.112 73.449 ;
     RECT  121.2 2.151 121.512 73.449 ;
     RECT  126.6 2.151 126.912 73.449 ;
     RECT  132 2.151 132.312 73.449 ;
     RECT  137.4 2.151 137.712 73.449 ;
     RECT  142.8 2.151 143.112 73.449 ;
     RECT  148.2 2.151 148.512 73.449 ;
     RECT  153.6 2.151 153.912 73.449 ;
     RECT  159 2.151 159.312 73.449 ;
     RECT  164.4 2.151 164.712 73.449 ;
     RECT  169.8 2.151 170.112 73.449 ;
     RECT  175.2 2.151 175.512 73.449 ;
     RECT  180.6 2.151 180.912 73.449 ;
     RECT  186 2.151 186.312 73.449 ;
     RECT  191.4 2.151 191.712 73.449 ;
     RECT  196.8 2.151 197.112 73.449 ;
     RECT  202.2 2.151 202.512 73.449 ;
     RECT  207.6 2.151 207.912 73.449 ;
     RECT  213 2.151 213.312 73.449 ;
     RECT  2.4 73.449 2.52 73.463 ;
     RECT  7.8 73.449 7.92 73.463 ;
     RECT  13.2 73.449 13.32 73.463 ;
     RECT  18.6 73.449 18.72 73.463 ;
     RECT  24 73.449 24.12 73.463 ;
     RECT  29.4 73.449 29.52 73.463 ;
     RECT  34.8 73.449 34.92 73.463 ;
     RECT  40.2 73.449 40.32 73.463 ;
     RECT  45.6 73.449 45.72 73.463 ;
     RECT  51 73.449 51.12 73.463 ;
     RECT  56.4 73.449 56.52 73.463 ;
     RECT  61.8 73.449 61.92 73.463 ;
     RECT  67.2 73.449 67.32 73.463 ;
     RECT  72.6 73.449 72.72 73.463 ;
     RECT  78 73.449 78.12 73.463 ;
     RECT  83.4 73.449 83.52 73.463 ;
     RECT  88.8 73.449 88.92 73.463 ;
     RECT  94.2 73.449 94.32 73.463 ;
     RECT  99.6 73.449 99.72 73.463 ;
     RECT  105 73.449 105.12 73.463 ;
     RECT  110.4 73.449 110.52 73.463 ;
     RECT  115.8 73.449 115.92 73.463 ;
     RECT  121.2 73.449 121.32 73.463 ;
     RECT  126.6 73.449 126.72 73.463 ;
     RECT  132 73.449 132.12 73.463 ;
     RECT  137.4 73.449 137.52 73.463 ;
     RECT  142.8 73.449 142.92 73.463 ;
     RECT  148.2 73.449 148.32 73.463 ;
     RECT  153.6 73.449 153.72 73.463 ;
     RECT  159 73.449 159.12 73.463 ;
     RECT  164.4 73.449 164.52 73.463 ;
     RECT  169.8 73.449 169.92 73.463 ;
     RECT  175.2 73.449 175.32 73.463 ;
     RECT  180.6 73.449 180.72 73.463 ;
     RECT  186 73.449 186.12 73.463 ;
     RECT  191.4 73.449 191.52 73.463 ;
     RECT  196.8 73.449 196.92 73.463 ;
     RECT  202.2 73.449 202.32 73.463 ;
     RECT  207.6 73.449 207.72 73.463 ;
     RECT  213 73.449 213.12 73.463 ;
  END
END dsfd_vm_static_bank128
END LIBRARY
